VERSION 5.8 ;
BUSBITCHARS "[]" ;
DIVIDERCHAR "/" ;
UNITS
    DATABASE MICRONS 1000 ;
END UNITS

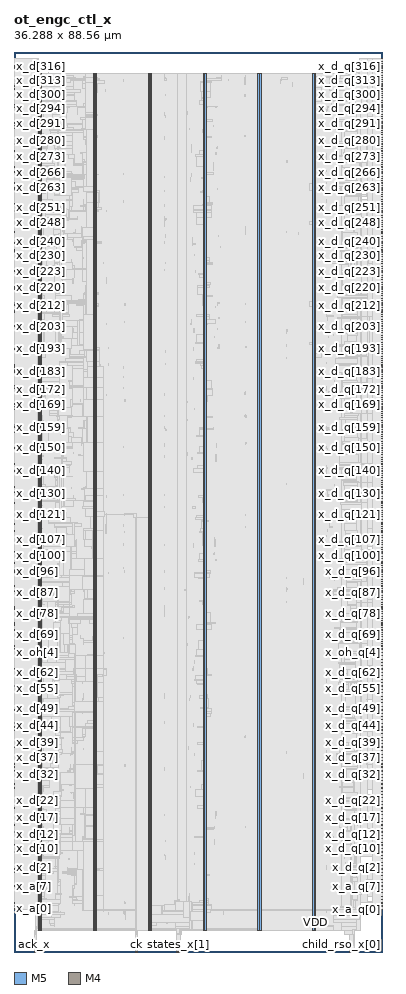
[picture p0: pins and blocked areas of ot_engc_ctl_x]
MACRO ot_engc_ctl_x
  FOREIGN ot_engc_ctl_x 0 0 ;
  CLASS BLOCK ;
  SIZE 36.288 BY 88.56 ;
  PIN ack_x
    DIRECTION OUTPUT ;
    USE SIGNAL ;
    PORT
      LAYER M5 ;
        RECT  2.016 0 2.04 0.084 ;
    END
  END ack_x
  PIN child_rso_x[0]
    DIRECTION INPUT ;
    USE SIGNAL ;
    PORT
      LAYER M5 ;
        RECT  33.024 0 33.048 0.084 ;
    END
  END child_rso_x[0]
  PIN child_rso_x[1]
    DIRECTION INPUT ;
    USE SIGNAL ;
    PORT
      LAYER M5 ;
        RECT  2.208 0 2.232 0.084 ;
    END
  END child_rso_x[1]
  PIN child_rso_x[2]
    DIRECTION INPUT ;
    USE SIGNAL ;
    PORT
      LAYER M5 ;
        RECT  33.12 0 33.144 0.084 ;
    END
  END child_rso_x[2]
  PIN child_rso_x[3]
    DIRECTION INPUT ;
    USE SIGNAL ;
    PORT
      LAYER M5 ;
        RECT  33.504 0 33.528 0.084 ;
    END
  END child_rso_x[3]
  PIN ck
    DIRECTION INPUT ;
    USE SIGNAL ;
    PORT
      LAYER M5 ;
        RECT  12 0 12.024 0.084 ;
    END
  END ck
  PIN rst
    DIRECTION INPUT ;
    USE SIGNAL ;
    PORT
      LAYER M5 ;
        RECT  12.096 0 12.12 0.084 ;
    END
  END rst
  PIN rst_io_n
    DIRECTION OUTPUT ;
    USE SIGNAL ;
    PORT
      LAYER M5 ;
        RECT  33.216 0 33.24 0.084 ;
    END
  END rst_io_n
  PIN rst_pb0_n
    DIRECTION OUTPUT ;
    USE SIGNAL ;
    PORT
      LAYER M5 ;
        RECT  33.312 0 33.336 0.084 ;
    END
  END rst_pb0_n
  PIN rst_pb1_n
    DIRECTION OUTPUT ;
    USE SIGNAL ;
    PORT
      LAYER M5 ;
        RECT  2.112 0 2.136 0.084 ;
    END
  END rst_pb1_n
  PIN rst_pb2_n
    DIRECTION OUTPUT ;
    USE SIGNAL ;
    PORT
      LAYER M5 ;
        RECT  33.408 0 33.432 0.084 ;
    END
  END rst_pb2_n
  PIN states_x[0]
    DIRECTION OUTPUT ;
    USE SIGNAL ;
    PORT
      LAYER M5 ;
        RECT  16.032 0 16.056 0.084 ;
    END
  END states_x[0]
  PIN states_x[1]
    DIRECTION OUTPUT ;
    USE SIGNAL ;
    PORT
      LAYER M5 ;
        RECT  16.128 0 16.152 0.084 ;
    END
  END states_x[1]
  PIN states_x[2]
    DIRECTION OUTPUT ;
    USE SIGNAL ;
    PORT
      LAYER M5 ;
        RECT  16.224 0 16.248 0.084 ;
    END
  END states_x[2]
  PIN states_x[3]
    DIRECTION OUTPUT ;
    USE SIGNAL ;
    PORT
      LAYER M5 ;
        RECT  16.32 0 16.344 0.084 ;
    END
  END states_x[3]
  PIN x_a[0]
    DIRECTION INPUT ;
    USE SIGNAL ;
    PORT
      LAYER M4 ;
        RECT  0 4.224 0.084 4.248 ;
    END
  END x_a[0]
  PIN x_a[1]
    DIRECTION INPUT ;
    USE SIGNAL ;
    PORT
      LAYER M4 ;
        RECT  0 4.512 0.084 4.536 ;
    END
  END x_a[1]
  PIN x_a[2]
    DIRECTION INPUT ;
    USE SIGNAL ;
    PORT
      LAYER M4 ;
        RECT  0 4.8 0.084 4.824 ;
    END
  END x_a[2]
  PIN x_a[3]
    DIRECTION INPUT ;
    USE SIGNAL ;
    PORT
      LAYER M4 ;
        RECT  0 5.136 0.084 5.16 ;
    END
  END x_a[3]
  PIN x_a[4]
    DIRECTION INPUT ;
    USE SIGNAL ;
    PORT
      LAYER M4 ;
        RECT  0 5.472 0.084 5.496 ;
    END
  END x_a[4]
  PIN x_a[5]
    DIRECTION INPUT ;
    USE SIGNAL ;
    PORT
      LAYER M4 ;
        RECT  0 5.856 0.084 5.88 ;
    END
  END x_a[5]
  PIN x_a[6]
    DIRECTION INPUT ;
    USE SIGNAL ;
    PORT
      LAYER M4 ;
        RECT  0 6.144 0.084 6.168 ;
    END
  END x_a[6]
  PIN x_a[7]
    DIRECTION INPUT ;
    USE SIGNAL ;
    PORT
      LAYER M4 ;
        RECT  0 6.48 0.084 6.504 ;
    END
  END x_a[7]
  PIN x_a_q[0]
    DIRECTION OUTPUT ;
    USE SIGNAL ;
    PORT
      LAYER M4 ;
        RECT  36.204 4.176 36.288 4.2 ;
    END
  END x_a_q[0]
  PIN x_a_q[1]
    DIRECTION OUTPUT ;
    USE SIGNAL ;
    PORT
      LAYER M4 ;
        RECT  36.204 4.512 36.288 4.536 ;
    END
  END x_a_q[1]
  PIN x_a_q[2]
    DIRECTION OUTPUT ;
    USE SIGNAL ;
    PORT
      LAYER M4 ;
        RECT  36.204 4.8 36.288 4.824 ;
    END
  END x_a_q[2]
  PIN x_a_q[3]
    DIRECTION OUTPUT ;
    USE SIGNAL ;
    PORT
      LAYER M4 ;
        RECT  36.204 5.136 36.288 5.16 ;
    END
  END x_a_q[3]
  PIN x_a_q[4]
    DIRECTION OUTPUT ;
    USE SIGNAL ;
    PORT
      LAYER M4 ;
        RECT  36.204 5.472 36.288 5.496 ;
    END
  END x_a_q[4]
  PIN x_a_q[5]
    DIRECTION OUTPUT ;
    USE SIGNAL ;
    PORT
      LAYER M4 ;
        RECT  36.204 5.808 36.288 5.832 ;
    END
  END x_a_q[5]
  PIN x_a_q[6]
    DIRECTION OUTPUT ;
    USE SIGNAL ;
    PORT
      LAYER M4 ;
        RECT  36.204 6.144 36.288 6.168 ;
    END
  END x_a_q[6]
  PIN x_a_q[7]
    DIRECTION OUTPUT ;
    USE SIGNAL ;
    PORT
      LAYER M4 ;
        RECT  36.204 6.48 36.288 6.504 ;
    END
  END x_a_q[7]
  PIN x_d[0]
    DIRECTION INPUT ;
    USE SIGNAL ;
    PORT
      LAYER M4 ;
        RECT  0 6.816 0.084 6.84 ;
    END
  END x_d[0]
  PIN x_d[100]
    DIRECTION INPUT ;
    USE SIGNAL ;
    PORT
      LAYER M4 ;
        RECT  0 38.256 0.084 38.28 ;
    END
  END x_d[100]
  PIN x_d[101]
    DIRECTION INPUT ;
    USE SIGNAL ;
    PORT
      LAYER M4 ;
        RECT  0 38.448 0.084 38.472 ;
    END
  END x_d[101]
  PIN x_d[102]
    DIRECTION INPUT ;
    USE SIGNAL ;
    PORT
      LAYER M4 ;
        RECT  0 38.736 0.084 38.76 ;
    END
  END x_d[102]
  PIN x_d[103]
    DIRECTION INPUT ;
    USE SIGNAL ;
    PORT
      LAYER M4 ;
        RECT  0 38.928 0.084 38.952 ;
    END
  END x_d[103]
  PIN x_d[104]
    DIRECTION INPUT ;
    USE SIGNAL ;
    PORT
      LAYER M4 ;
        RECT  0 39.168 0.084 39.192 ;
    END
  END x_d[104]
  PIN x_d[105]
    DIRECTION INPUT ;
    USE SIGNAL ;
    PORT
      LAYER M4 ;
        RECT  0 39.36 0.084 39.384 ;
    END
  END x_d[105]
  PIN x_d[106]
    DIRECTION INPUT ;
    USE SIGNAL ;
    PORT
      LAYER M4 ;
        RECT  0 39.6 0.084 39.624 ;
    END
  END x_d[106]
  PIN x_d[107]
    DIRECTION INPUT ;
    USE SIGNAL ;
    PORT
      LAYER M4 ;
        RECT  0 39.792 0.084 39.816 ;
    END
  END x_d[107]
  PIN x_d[108]
    DIRECTION INPUT ;
    USE SIGNAL ;
    PORT
      LAYER M4 ;
        RECT  0 40.08 0.084 40.104 ;
    END
  END x_d[108]
  PIN x_d[109]
    DIRECTION INPUT ;
    USE SIGNAL ;
    PORT
      LAYER M4 ;
        RECT  0 40.32 0.084 40.344 ;
    END
  END x_d[109]
  PIN x_d[10]
    DIRECTION INPUT ;
    USE SIGNAL ;
    PORT
      LAYER M4 ;
        RECT  0 10.176 0.084 10.2 ;
    END
  END x_d[10]
  PIN x_d[110]
    DIRECTION INPUT ;
    USE SIGNAL ;
    PORT
      LAYER M4 ;
        RECT  0 40.512 0.084 40.536 ;
    END
  END x_d[110]
  PIN x_d[111]
    DIRECTION INPUT ;
    USE SIGNAL ;
    PORT
      LAYER M4 ;
        RECT  0 40.752 0.084 40.776 ;
    END
  END x_d[111]
  PIN x_d[112]
    DIRECTION INPUT ;
    USE SIGNAL ;
    PORT
      LAYER M4 ;
        RECT  0 40.944 0.084 40.968 ;
    END
  END x_d[112]
  PIN x_d[113]
    DIRECTION INPUT ;
    USE SIGNAL ;
    PORT
      LAYER M4 ;
        RECT  0 41.232 0.084 41.256 ;
    END
  END x_d[113]
  PIN x_d[114]
    DIRECTION INPUT ;
    USE SIGNAL ;
    PORT
      LAYER M4 ;
        RECT  0 41.424 0.084 41.448 ;
    END
  END x_d[114]
  PIN x_d[115]
    DIRECTION INPUT ;
    USE SIGNAL ;
    PORT
      LAYER M4 ;
        RECT  0 41.664 0.084 41.688 ;
    END
  END x_d[115]
  PIN x_d[116]
    DIRECTION INPUT ;
    USE SIGNAL ;
    PORT
      LAYER M4 ;
        RECT  0 41.856 0.084 41.88 ;
    END
  END x_d[116]
  PIN x_d[117]
    DIRECTION INPUT ;
    USE SIGNAL ;
    PORT
      LAYER M4 ;
        RECT  0 42.096 0.084 42.12 ;
    END
  END x_d[117]
  PIN x_d[118]
    DIRECTION INPUT ;
    USE SIGNAL ;
    PORT
      LAYER M4 ;
        RECT  0 42.288 0.084 42.312 ;
    END
  END x_d[118]
  PIN x_d[119]
    DIRECTION INPUT ;
    USE SIGNAL ;
    PORT
      LAYER M4 ;
        RECT  0 42.576 0.084 42.6 ;
    END
  END x_d[119]
  PIN x_d[11]
    DIRECTION INPUT ;
    USE SIGNAL ;
    PORT
      LAYER M4 ;
        RECT  0 10.512 0.084 10.536 ;
    END
  END x_d[11]
  PIN x_d[120]
    DIRECTION INPUT ;
    USE SIGNAL ;
    PORT
      LAYER M4 ;
        RECT  0 42.816 0.084 42.84 ;
    END
  END x_d[120]
  PIN x_d[121]
    DIRECTION INPUT ;
    USE SIGNAL ;
    PORT
      LAYER M4 ;
        RECT  0 43.008 0.084 43.032 ;
    END
  END x_d[121]
  PIN x_d[122]
    DIRECTION INPUT ;
    USE SIGNAL ;
    PORT
      LAYER M4 ;
        RECT  0 43.248 0.084 43.272 ;
    END
  END x_d[122]
  PIN x_d[123]
    DIRECTION INPUT ;
    USE SIGNAL ;
    PORT
      LAYER M4 ;
        RECT  0 43.44 0.084 43.464 ;
    END
  END x_d[123]
  PIN x_d[124]
    DIRECTION INPUT ;
    USE SIGNAL ;
    PORT
      LAYER M4 ;
        RECT  0 43.728 0.084 43.752 ;
    END
  END x_d[124]
  PIN x_d[125]
    DIRECTION INPUT ;
    USE SIGNAL ;
    PORT
      LAYER M4 ;
        RECT  0 43.92 0.084 43.944 ;
    END
  END x_d[125]
  PIN x_d[126]
    DIRECTION INPUT ;
    USE SIGNAL ;
    PORT
      LAYER M4 ;
        RECT  0 44.16 0.084 44.184 ;
    END
  END x_d[126]
  PIN x_d[127]
    DIRECTION INPUT ;
    USE SIGNAL ;
    PORT
      LAYER M4 ;
        RECT  0 44.352 0.084 44.376 ;
    END
  END x_d[127]
  PIN x_d[128]
    DIRECTION INPUT ;
    USE SIGNAL ;
    PORT
      LAYER M4 ;
        RECT  0 44.592 0.084 44.616 ;
    END
  END x_d[128]
  PIN x_d[129]
    DIRECTION INPUT ;
    USE SIGNAL ;
    PORT
      LAYER M4 ;
        RECT  0 44.832 0.084 44.856 ;
    END
  END x_d[129]
  PIN x_d[12]
    DIRECTION INPUT ;
    USE SIGNAL ;
    PORT
      LAYER M4 ;
        RECT  0 10.8 0.084 10.824 ;
    END
  END x_d[12]
  PIN x_d[130]
    DIRECTION INPUT ;
    USE SIGNAL ;
    PORT
      LAYER M4 ;
        RECT  0 45.072 0.084 45.096 ;
    END
  END x_d[130]
  PIN x_d[131]
    DIRECTION INPUT ;
    USE SIGNAL ;
    PORT
      LAYER M4 ;
        RECT  0 45.264 0.084 45.288 ;
    END
  END x_d[131]
  PIN x_d[132]
    DIRECTION INPUT ;
    USE SIGNAL ;
    PORT
      LAYER M4 ;
        RECT  0 45.504 0.084 45.528 ;
    END
  END x_d[132]
  PIN x_d[133]
    DIRECTION INPUT ;
    USE SIGNAL ;
    PORT
      LAYER M4 ;
        RECT  0 45.744 0.084 45.768 ;
    END
  END x_d[133]
  PIN x_d[134]
    DIRECTION INPUT ;
    USE SIGNAL ;
    PORT
      LAYER M4 ;
        RECT  0 45.984 0.084 46.008 ;
    END
  END x_d[134]
  PIN x_d[135]
    DIRECTION INPUT ;
    USE SIGNAL ;
    PORT
      LAYER M4 ;
        RECT  0 46.176 0.084 46.2 ;
    END
  END x_d[135]
  PIN x_d[136]
    DIRECTION INPUT ;
    USE SIGNAL ;
    PORT
      LAYER M4 ;
        RECT  0 46.416 0.084 46.44 ;
    END
  END x_d[136]
  PIN x_d[137]
    DIRECTION INPUT ;
    USE SIGNAL ;
    PORT
      LAYER M4 ;
        RECT  0 46.656 0.084 46.68 ;
    END
  END x_d[137]
  PIN x_d[138]
    DIRECTION INPUT ;
    USE SIGNAL ;
    PORT
      LAYER M4 ;
        RECT  0 46.848 0.084 46.872 ;
    END
  END x_d[138]
  PIN x_d[139]
    DIRECTION INPUT ;
    USE SIGNAL ;
    PORT
      LAYER M4 ;
        RECT  0 47.088 0.084 47.112 ;
    END
  END x_d[139]
  PIN x_d[13]
    DIRECTION INPUT ;
    USE SIGNAL ;
    PORT
      LAYER M4 ;
        RECT  0 11.136 0.084 11.16 ;
    END
  END x_d[13]
  PIN x_d[140]
    DIRECTION INPUT ;
    USE SIGNAL ;
    PORT
      LAYER M4 ;
        RECT  0 47.328 0.084 47.352 ;
    END
  END x_d[140]
  PIN x_d[141]
    DIRECTION INPUT ;
    USE SIGNAL ;
    PORT
      LAYER M4 ;
        RECT  0 47.568 0.084 47.592 ;
    END
  END x_d[141]
  PIN x_d[142]
    DIRECTION INPUT ;
    USE SIGNAL ;
    PORT
      LAYER M4 ;
        RECT  0 47.76 0.084 47.784 ;
    END
  END x_d[142]
  PIN x_d[143]
    DIRECTION INPUT ;
    USE SIGNAL ;
    PORT
      LAYER M4 ;
        RECT  0 48 0.084 48.024 ;
    END
  END x_d[143]
  PIN x_d[144]
    DIRECTION INPUT ;
    USE SIGNAL ;
    PORT
      LAYER M4 ;
        RECT  0 48.24 0.084 48.264 ;
    END
  END x_d[144]
  PIN x_d[145]
    DIRECTION INPUT ;
    USE SIGNAL ;
    PORT
      LAYER M4 ;
        RECT  0 48.432 0.084 48.456 ;
    END
  END x_d[145]
  PIN x_d[146]
    DIRECTION INPUT ;
    USE SIGNAL ;
    PORT
      LAYER M4 ;
        RECT  0 48.672 0.084 48.696 ;
    END
  END x_d[146]
  PIN x_d[147]
    DIRECTION INPUT ;
    USE SIGNAL ;
    PORT
      LAYER M4 ;
        RECT  0 48.912 0.084 48.936 ;
    END
  END x_d[147]
  PIN x_d[148]
    DIRECTION INPUT ;
    USE SIGNAL ;
    PORT
      LAYER M4 ;
        RECT  0 49.152 0.084 49.176 ;
    END
  END x_d[148]
  PIN x_d[149]
    DIRECTION INPUT ;
    USE SIGNAL ;
    PORT
      LAYER M4 ;
        RECT  0 49.344 0.084 49.368 ;
    END
  END x_d[149]
  PIN x_d[14]
    DIRECTION INPUT ;
    USE SIGNAL ;
    PORT
      LAYER M4 ;
        RECT  0 11.472 0.084 11.496 ;
    END
  END x_d[14]
  PIN x_d[150]
    DIRECTION INPUT ;
    USE SIGNAL ;
    PORT
      LAYER M4 ;
        RECT  0 49.584 0.084 49.608 ;
    END
  END x_d[150]
  PIN x_d[151]
    DIRECTION INPUT ;
    USE SIGNAL ;
    PORT
      LAYER M4 ;
        RECT  0 49.824 0.084 49.848 ;
    END
  END x_d[151]
  PIN x_d[152]
    DIRECTION INPUT ;
    USE SIGNAL ;
    PORT
      LAYER M4 ;
        RECT  0 50.016 0.084 50.04 ;
    END
  END x_d[152]
  PIN x_d[153]
    DIRECTION INPUT ;
    USE SIGNAL ;
    PORT
      LAYER M4 ;
        RECT  0 50.256 0.084 50.28 ;
    END
  END x_d[153]
  PIN x_d[154]
    DIRECTION INPUT ;
    USE SIGNAL ;
    PORT
      LAYER M4 ;
        RECT  0 50.496 0.084 50.52 ;
    END
  END x_d[154]
  PIN x_d[155]
    DIRECTION INPUT ;
    USE SIGNAL ;
    PORT
      LAYER M4 ;
        RECT  0 50.736 0.084 50.76 ;
    END
  END x_d[155]
  PIN x_d[156]
    DIRECTION INPUT ;
    USE SIGNAL ;
    PORT
      LAYER M4 ;
        RECT  0 50.928 0.084 50.952 ;
    END
  END x_d[156]
  PIN x_d[157]
    DIRECTION INPUT ;
    USE SIGNAL ;
    PORT
      LAYER M4 ;
        RECT  0 51.168 0.084 51.192 ;
    END
  END x_d[157]
  PIN x_d[158]
    DIRECTION INPUT ;
    USE SIGNAL ;
    PORT
      LAYER M4 ;
        RECT  0 51.408 0.084 51.432 ;
    END
  END x_d[158]
  PIN x_d[159]
    DIRECTION INPUT ;
    USE SIGNAL ;
    PORT
      LAYER M4 ;
        RECT  0 51.648 0.084 51.672 ;
    END
  END x_d[159]
  PIN x_d[15]
    DIRECTION INPUT ;
    USE SIGNAL ;
    PORT
      LAYER M4 ;
        RECT  0 11.808 0.084 11.832 ;
    END
  END x_d[15]
  PIN x_d[160]
    DIRECTION INPUT ;
    USE SIGNAL ;
    PORT
      LAYER M4 ;
        RECT  0 51.84 0.084 51.864 ;
    END
  END x_d[160]
  PIN x_d[161]
    DIRECTION INPUT ;
    USE SIGNAL ;
    PORT
      LAYER M4 ;
        RECT  0 52.08 0.084 52.104 ;
    END
  END x_d[161]
  PIN x_d[162]
    DIRECTION INPUT ;
    USE SIGNAL ;
    PORT
      LAYER M4 ;
        RECT  0 52.272 0.084 52.296 ;
    END
  END x_d[162]
  PIN x_d[163]
    DIRECTION INPUT ;
    USE SIGNAL ;
    PORT
      LAYER M4 ;
        RECT  0 52.56 0.084 52.584 ;
    END
  END x_d[163]
  PIN x_d[164]
    DIRECTION INPUT ;
    USE SIGNAL ;
    PORT
      LAYER M4 ;
        RECT  0 52.752 0.084 52.776 ;
    END
  END x_d[164]
  PIN x_d[165]
    DIRECTION INPUT ;
    USE SIGNAL ;
    PORT
      LAYER M4 ;
        RECT  0 52.992 0.084 53.016 ;
    END
  END x_d[165]
  PIN x_d[166]
    DIRECTION INPUT ;
    USE SIGNAL ;
    PORT
      LAYER M4 ;
        RECT  0 53.184 0.084 53.208 ;
    END
  END x_d[166]
  PIN x_d[167]
    DIRECTION INPUT ;
    USE SIGNAL ;
    PORT
      LAYER M4 ;
        RECT  0 53.424 0.084 53.448 ;
    END
  END x_d[167]
  PIN x_d[168]
    DIRECTION INPUT ;
    USE SIGNAL ;
    PORT
      LAYER M4 ;
        RECT  0 53.616 0.084 53.64 ;
    END
  END x_d[168]
  PIN x_d[169]
    DIRECTION INPUT ;
    USE SIGNAL ;
    PORT
      LAYER M4 ;
        RECT  0 53.904 0.084 53.928 ;
    END
  END x_d[169]
  PIN x_d[16]
    DIRECTION INPUT ;
    USE SIGNAL ;
    PORT
      LAYER M4 ;
        RECT  0 12.144 0.084 12.168 ;
    END
  END x_d[16]
  PIN x_d[170]
    DIRECTION INPUT ;
    USE SIGNAL ;
    PORT
      LAYER M4 ;
        RECT  0 54.144 0.084 54.168 ;
    END
  END x_d[170]
  PIN x_d[171]
    DIRECTION INPUT ;
    USE SIGNAL ;
    PORT
      LAYER M4 ;
        RECT  0 54.336 0.084 54.36 ;
    END
  END x_d[171]
  PIN x_d[172]
    DIRECTION INPUT ;
    USE SIGNAL ;
    PORT
      LAYER M4 ;
        RECT  0 54.576 0.084 54.6 ;
    END
  END x_d[172]
  PIN x_d[173]
    DIRECTION INPUT ;
    USE SIGNAL ;
    PORT
      LAYER M4 ;
        RECT  0 54.768 0.084 54.792 ;
    END
  END x_d[173]
  PIN x_d[174]
    DIRECTION INPUT ;
    USE SIGNAL ;
    PORT
      LAYER M4 ;
        RECT  0 55.056 0.084 55.08 ;
    END
  END x_d[174]
  PIN x_d[175]
    DIRECTION INPUT ;
    USE SIGNAL ;
    PORT
      LAYER M4 ;
        RECT  0 55.248 0.084 55.272 ;
    END
  END x_d[175]
  PIN x_d[176]
    DIRECTION INPUT ;
    USE SIGNAL ;
    PORT
      LAYER M4 ;
        RECT  0 55.488 0.084 55.512 ;
    END
  END x_d[176]
  PIN x_d[177]
    DIRECTION INPUT ;
    USE SIGNAL ;
    PORT
      LAYER M4 ;
        RECT  0 55.68 0.084 55.704 ;
    END
  END x_d[177]
  PIN x_d[178]
    DIRECTION INPUT ;
    USE SIGNAL ;
    PORT
      LAYER M4 ;
        RECT  0 55.92 0.084 55.944 ;
    END
  END x_d[178]
  PIN x_d[179]
    DIRECTION INPUT ;
    USE SIGNAL ;
    PORT
      LAYER M4 ;
        RECT  0 56.112 0.084 56.136 ;
    END
  END x_d[179]
  PIN x_d[17]
    DIRECTION INPUT ;
    USE SIGNAL ;
    PORT
      LAYER M4 ;
        RECT  0 12.48 0.084 12.504 ;
    END
  END x_d[17]
  PIN x_d[180]
    DIRECTION INPUT ;
    USE SIGNAL ;
    PORT
      LAYER M4 ;
        RECT  0 56.4 0.084 56.424 ;
    END
  END x_d[180]
  PIN x_d[181]
    DIRECTION INPUT ;
    USE SIGNAL ;
    PORT
      LAYER M4 ;
        RECT  0 56.592 0.084 56.616 ;
    END
  END x_d[181]
  PIN x_d[182]
    DIRECTION INPUT ;
    USE SIGNAL ;
    PORT
      LAYER M4 ;
        RECT  0 56.832 0.084 56.856 ;
    END
  END x_d[182]
  PIN x_d[183]
    DIRECTION INPUT ;
    USE SIGNAL ;
    PORT
      LAYER M4 ;
        RECT  0 57.072 0.084 57.096 ;
    END
  END x_d[183]
  PIN x_d[184]
    DIRECTION INPUT ;
    USE SIGNAL ;
    PORT
      LAYER M4 ;
        RECT  0 57.264 0.084 57.288 ;
    END
  END x_d[184]
  PIN x_d[185]
    DIRECTION INPUT ;
    USE SIGNAL ;
    PORT
      LAYER M4 ;
        RECT  0 57.552 0.084 57.576 ;
    END
  END x_d[185]
  PIN x_d[186]
    DIRECTION INPUT ;
    USE SIGNAL ;
    PORT
      LAYER M4 ;
        RECT  0 57.744 0.084 57.768 ;
    END
  END x_d[186]
  PIN x_d[187]
    DIRECTION INPUT ;
    USE SIGNAL ;
    PORT
      LAYER M4 ;
        RECT  0 57.984 0.084 58.008 ;
    END
  END x_d[187]
  PIN x_d[188]
    DIRECTION INPUT ;
    USE SIGNAL ;
    PORT
      LAYER M4 ;
        RECT  0 58.176 0.084 58.2 ;
    END
  END x_d[188]
  PIN x_d[189]
    DIRECTION INPUT ;
    USE SIGNAL ;
    PORT
      LAYER M4 ;
        RECT  0 58.416 0.084 58.44 ;
    END
  END x_d[189]
  PIN x_d[18]
    DIRECTION INPUT ;
    USE SIGNAL ;
    PORT
      LAYER M4 ;
        RECT  0 12.816 0.084 12.84 ;
    END
  END x_d[18]
  PIN x_d[190]
    DIRECTION INPUT ;
    USE SIGNAL ;
    PORT
      LAYER M4 ;
        RECT  0 58.608 0.084 58.632 ;
    END
  END x_d[190]
  PIN x_d[191]
    DIRECTION INPUT ;
    USE SIGNAL ;
    PORT
      LAYER M4 ;
        RECT  0 58.896 0.084 58.92 ;
    END
  END x_d[191]
  PIN x_d[192]
    DIRECTION INPUT ;
    USE SIGNAL ;
    PORT
      LAYER M4 ;
        RECT  0 59.088 0.084 59.112 ;
    END
  END x_d[192]
  PIN x_d[193]
    DIRECTION INPUT ;
    USE SIGNAL ;
    PORT
      LAYER M4 ;
        RECT  0 59.328 0.084 59.352 ;
    END
  END x_d[193]
  PIN x_d[194]
    DIRECTION INPUT ;
    USE SIGNAL ;
    PORT
      LAYER M4 ;
        RECT  0 59.568 0.084 59.592 ;
    END
  END x_d[194]
  PIN x_d[195]
    DIRECTION INPUT ;
    USE SIGNAL ;
    PORT
      LAYER M4 ;
        RECT  0 59.76 0.084 59.784 ;
    END
  END x_d[195]
  PIN x_d[196]
    DIRECTION INPUT ;
    USE SIGNAL ;
    PORT
      LAYER M4 ;
        RECT  0 60 0.084 60.024 ;
    END
  END x_d[196]
  PIN x_d[197]
    DIRECTION INPUT ;
    USE SIGNAL ;
    PORT
      LAYER M4 ;
        RECT  0 60.24 0.084 60.264 ;
    END
  END x_d[197]
  PIN x_d[198]
    DIRECTION INPUT ;
    USE SIGNAL ;
    PORT
      LAYER M4 ;
        RECT  0 60.48 0.084 60.504 ;
    END
  END x_d[198]
  PIN x_d[199]
    DIRECTION INPUT ;
    USE SIGNAL ;
    PORT
      LAYER M4 ;
        RECT  0 60.672 0.084 60.696 ;
    END
  END x_d[199]
  PIN x_d[19]
    DIRECTION INPUT ;
    USE SIGNAL ;
    PORT
      LAYER M4 ;
        RECT  0 13.2 0.084 13.224 ;
    END
  END x_d[19]
  PIN x_d[1]
    DIRECTION INPUT ;
    USE SIGNAL ;
    PORT
      LAYER M4 ;
        RECT  0 7.152 0.084 7.176 ;
    END
  END x_d[1]
  PIN x_d[200]
    DIRECTION INPUT ;
    USE SIGNAL ;
    PORT
      LAYER M4 ;
        RECT  0 60.912 0.084 60.936 ;
    END
  END x_d[200]
  PIN x_d[201]
    DIRECTION INPUT ;
    USE SIGNAL ;
    PORT
      LAYER M4 ;
        RECT  0 61.152 0.084 61.176 ;
    END
  END x_d[201]
  PIN x_d[202]
    DIRECTION INPUT ;
    USE SIGNAL ;
    PORT
      LAYER M4 ;
        RECT  0 61.344 0.084 61.368 ;
    END
  END x_d[202]
  PIN x_d[203]
    DIRECTION INPUT ;
    USE SIGNAL ;
    PORT
      LAYER M4 ;
        RECT  0 61.584 0.084 61.608 ;
    END
  END x_d[203]
  PIN x_d[204]
    DIRECTION INPUT ;
    USE SIGNAL ;
    PORT
      LAYER M4 ;
        RECT  0 61.824 0.084 61.848 ;
    END
  END x_d[204]
  PIN x_d[205]
    DIRECTION INPUT ;
    USE SIGNAL ;
    PORT
      LAYER M4 ;
        RECT  0 62.064 0.084 62.088 ;
    END
  END x_d[205]
  PIN x_d[206]
    DIRECTION INPUT ;
    USE SIGNAL ;
    PORT
      LAYER M4 ;
        RECT  0 62.256 0.084 62.28 ;
    END
  END x_d[206]
  PIN x_d[207]
    DIRECTION INPUT ;
    USE SIGNAL ;
    PORT
      LAYER M4 ;
        RECT  0 62.496 0.084 62.52 ;
    END
  END x_d[207]
  PIN x_d[208]
    DIRECTION INPUT ;
    USE SIGNAL ;
    PORT
      LAYER M4 ;
        RECT  0 62.736 0.084 62.76 ;
    END
  END x_d[208]
  PIN x_d[209]
    DIRECTION INPUT ;
    USE SIGNAL ;
    PORT
      LAYER M4 ;
        RECT  0 62.976 0.084 63 ;
    END
  END x_d[209]
  PIN x_d[20]
    DIRECTION INPUT ;
    USE SIGNAL ;
    PORT
      LAYER M4 ;
        RECT  0 13.488 0.084 13.512 ;
    END
  END x_d[20]
  PIN x_d[210]
    DIRECTION INPUT ;
    USE SIGNAL ;
    PORT
      LAYER M4 ;
        RECT  0 63.168 0.084 63.192 ;
    END
  END x_d[210]
  PIN x_d[211]
    DIRECTION INPUT ;
    USE SIGNAL ;
    PORT
      LAYER M4 ;
        RECT  0 63.408 0.084 63.432 ;
    END
  END x_d[211]
  PIN x_d[212]
    DIRECTION INPUT ;
    USE SIGNAL ;
    PORT
      LAYER M4 ;
        RECT  0 63.648 0.084 63.672 ;
    END
  END x_d[212]
  PIN x_d[213]
    DIRECTION INPUT ;
    USE SIGNAL ;
    PORT
      LAYER M4 ;
        RECT  0 63.84 0.084 63.864 ;
    END
  END x_d[213]
  PIN x_d[214]
    DIRECTION INPUT ;
    USE SIGNAL ;
    PORT
      LAYER M4 ;
        RECT  0 64.08 0.084 64.104 ;
    END
  END x_d[214]
  PIN x_d[215]
    DIRECTION INPUT ;
    USE SIGNAL ;
    PORT
      LAYER M4 ;
        RECT  0 64.32 0.084 64.344 ;
    END
  END x_d[215]
  PIN x_d[216]
    DIRECTION INPUT ;
    USE SIGNAL ;
    PORT
      LAYER M4 ;
        RECT  0 64.56 0.084 64.584 ;
    END
  END x_d[216]
  PIN x_d[217]
    DIRECTION INPUT ;
    USE SIGNAL ;
    PORT
      LAYER M4 ;
        RECT  0 64.752 0.084 64.776 ;
    END
  END x_d[217]
  PIN x_d[218]
    DIRECTION INPUT ;
    USE SIGNAL ;
    PORT
      LAYER M4 ;
        RECT  0 64.992 0.084 65.016 ;
    END
  END x_d[218]
  PIN x_d[219]
    DIRECTION INPUT ;
    USE SIGNAL ;
    PORT
      LAYER M4 ;
        RECT  0 65.232 0.084 65.256 ;
    END
  END x_d[219]
  PIN x_d[21]
    DIRECTION INPUT ;
    USE SIGNAL ;
    PORT
      LAYER M4 ;
        RECT  0 13.824 0.084 13.848 ;
    END
  END x_d[21]
  PIN x_d[220]
    DIRECTION INPUT ;
    USE SIGNAL ;
    PORT
      LAYER M4 ;
        RECT  0 65.424 0.084 65.448 ;
    END
  END x_d[220]
  PIN x_d[221]
    DIRECTION INPUT ;
    USE SIGNAL ;
    PORT
      LAYER M4 ;
        RECT  0 65.664 0.084 65.688 ;
    END
  END x_d[221]
  PIN x_d[222]
    DIRECTION INPUT ;
    USE SIGNAL ;
    PORT
      LAYER M4 ;
        RECT  0 65.904 0.084 65.928 ;
    END
  END x_d[222]
  PIN x_d[223]
    DIRECTION INPUT ;
    USE SIGNAL ;
    PORT
      LAYER M4 ;
        RECT  0 66.144 0.084 66.168 ;
    END
  END x_d[223]
  PIN x_d[224]
    DIRECTION INPUT ;
    USE SIGNAL ;
    PORT
      LAYER M4 ;
        RECT  0 66.384 0.084 66.408 ;
    END
  END x_d[224]
  PIN x_d[225]
    DIRECTION INPUT ;
    USE SIGNAL ;
    PORT
      LAYER M4 ;
        RECT  0 66.576 0.084 66.6 ;
    END
  END x_d[225]
  PIN x_d[226]
    DIRECTION INPUT ;
    USE SIGNAL ;
    PORT
      LAYER M4 ;
        RECT  0 66.816 0.084 66.84 ;
    END
  END x_d[226]
  PIN x_d[227]
    DIRECTION INPUT ;
    USE SIGNAL ;
    PORT
      LAYER M4 ;
        RECT  0 67.008 0.084 67.032 ;
    END
  END x_d[227]
  PIN x_d[228]
    DIRECTION INPUT ;
    USE SIGNAL ;
    PORT
      LAYER M4 ;
        RECT  0 67.248 0.084 67.272 ;
    END
  END x_d[228]
  PIN x_d[229]
    DIRECTION INPUT ;
    USE SIGNAL ;
    PORT
      LAYER M4 ;
        RECT  0 67.44 0.084 67.464 ;
    END
  END x_d[229]
  PIN x_d[22]
    DIRECTION INPUT ;
    USE SIGNAL ;
    PORT
      LAYER M4 ;
        RECT  0 14.16 0.084 14.184 ;
    END
  END x_d[22]
  PIN x_d[230]
    DIRECTION INPUT ;
    USE SIGNAL ;
    PORT
      LAYER M4 ;
        RECT  0 67.728 0.084 67.752 ;
    END
  END x_d[230]
  PIN x_d[231]
    DIRECTION INPUT ;
    USE SIGNAL ;
    PORT
      LAYER M4 ;
        RECT  0 67.92 0.084 67.944 ;
    END
  END x_d[231]
  PIN x_d[232]
    DIRECTION INPUT ;
    USE SIGNAL ;
    PORT
      LAYER M4 ;
        RECT  0 68.16 0.084 68.184 ;
    END
  END x_d[232]
  PIN x_d[233]
    DIRECTION INPUT ;
    USE SIGNAL ;
    PORT
      LAYER M4 ;
        RECT  0 68.4 0.084 68.424 ;
    END
  END x_d[233]
  PIN x_d[234]
    DIRECTION INPUT ;
    USE SIGNAL ;
    PORT
      LAYER M4 ;
        RECT  0 68.592 0.084 68.616 ;
    END
  END x_d[234]
  PIN x_d[235]
    DIRECTION INPUT ;
    USE SIGNAL ;
    PORT
      LAYER M4 ;
        RECT  0 68.88 0.084 68.904 ;
    END
  END x_d[235]
  PIN x_d[236]
    DIRECTION INPUT ;
    USE SIGNAL ;
    PORT
      LAYER M4 ;
        RECT  0 69.072 0.084 69.096 ;
    END
  END x_d[236]
  PIN x_d[237]
    DIRECTION INPUT ;
    USE SIGNAL ;
    PORT
      LAYER M4 ;
        RECT  0 69.312 0.084 69.336 ;
    END
  END x_d[237]
  PIN x_d[238]
    DIRECTION INPUT ;
    USE SIGNAL ;
    PORT
      LAYER M4 ;
        RECT  0 69.504 0.084 69.528 ;
    END
  END x_d[238]
  PIN x_d[239]
    DIRECTION INPUT ;
    USE SIGNAL ;
    PORT
      LAYER M4 ;
        RECT  0 69.744 0.084 69.768 ;
    END
  END x_d[239]
  PIN x_d[23]
    DIRECTION INPUT ;
    USE SIGNAL ;
    PORT
      LAYER M4 ;
        RECT  0 14.496 0.084 14.52 ;
    END
  END x_d[23]
  PIN x_d[240]
    DIRECTION INPUT ;
    USE SIGNAL ;
    PORT
      LAYER M4 ;
        RECT  0 69.936 0.084 69.96 ;
    END
  END x_d[240]
  PIN x_d[241]
    DIRECTION INPUT ;
    USE SIGNAL ;
    PORT
      LAYER M4 ;
        RECT  0 70.224 0.084 70.248 ;
    END
  END x_d[241]
  PIN x_d[242]
    DIRECTION INPUT ;
    USE SIGNAL ;
    PORT
      LAYER M4 ;
        RECT  0 70.416 0.084 70.44 ;
    END
  END x_d[242]
  PIN x_d[243]
    DIRECTION INPUT ;
    USE SIGNAL ;
    PORT
      LAYER M4 ;
        RECT  0 70.656 0.084 70.68 ;
    END
  END x_d[243]
  PIN x_d[244]
    DIRECTION INPUT ;
    USE SIGNAL ;
    PORT
      LAYER M4 ;
        RECT  0 70.848 0.084 70.872 ;
    END
  END x_d[244]
  PIN x_d[245]
    DIRECTION INPUT ;
    USE SIGNAL ;
    PORT
      LAYER M4 ;
        RECT  0 71.088 0.084 71.112 ;
    END
  END x_d[245]
  PIN x_d[246]
    DIRECTION INPUT ;
    USE SIGNAL ;
    PORT
      LAYER M4 ;
        RECT  0 71.376 0.084 71.4 ;
    END
  END x_d[246]
  PIN x_d[247]
    DIRECTION INPUT ;
    USE SIGNAL ;
    PORT
      LAYER M4 ;
        RECT  0 71.568 0.084 71.592 ;
    END
  END x_d[247]
  PIN x_d[248]
    DIRECTION INPUT ;
    USE SIGNAL ;
    PORT
      LAYER M4 ;
        RECT  0 71.808 0.084 71.832 ;
    END
  END x_d[248]
  PIN x_d[249]
    DIRECTION INPUT ;
    USE SIGNAL ;
    PORT
      LAYER M4 ;
        RECT  0 72 0.084 72.024 ;
    END
  END x_d[249]
  PIN x_d[24]
    DIRECTION INPUT ;
    USE SIGNAL ;
    PORT
      LAYER M4 ;
        RECT  0 14.832 0.084 14.856 ;
    END
  END x_d[24]
  PIN x_d[250]
    DIRECTION INPUT ;
    USE SIGNAL ;
    PORT
      LAYER M4 ;
        RECT  0 72.24 0.084 72.264 ;
    END
  END x_d[250]
  PIN x_d[251]
    DIRECTION INPUT ;
    USE SIGNAL ;
    PORT
      LAYER M4 ;
        RECT  0 72.432 0.084 72.456 ;
    END
  END x_d[251]
  PIN x_d[252]
    DIRECTION INPUT ;
    USE SIGNAL ;
    PORT
      LAYER M4 ;
        RECT  0 72.72 0.084 72.744 ;
    END
  END x_d[252]
  PIN x_d[253]
    DIRECTION INPUT ;
    USE SIGNAL ;
    PORT
      LAYER M4 ;
        RECT  0 72.912 0.084 72.936 ;
    END
  END x_d[253]
  PIN x_d[254]
    DIRECTION INPUT ;
    USE SIGNAL ;
    PORT
      LAYER M4 ;
        RECT  0 73.152 0.084 73.176 ;
    END
  END x_d[254]
  PIN x_d[255]
    DIRECTION INPUT ;
    USE SIGNAL ;
    PORT
      LAYER M4 ;
        RECT  0 73.344 0.084 73.368 ;
    END
  END x_d[255]
  PIN x_d[256]
    DIRECTION INPUT ;
    USE SIGNAL ;
    PORT
      LAYER M4 ;
        RECT  0 73.584 0.084 73.608 ;
    END
  END x_d[256]
  PIN x_d[257]
    DIRECTION INPUT ;
    USE SIGNAL ;
    PORT
      LAYER M4 ;
        RECT  0 73.824 0.084 73.848 ;
    END
  END x_d[257]
  PIN x_d[258]
    DIRECTION INPUT ;
    USE SIGNAL ;
    PORT
      LAYER M4 ;
        RECT  0 74.064 0.084 74.088 ;
    END
  END x_d[258]
  PIN x_d[259]
    DIRECTION INPUT ;
    USE SIGNAL ;
    PORT
      LAYER M4 ;
        RECT  0 74.304 0.084 74.328 ;
    END
  END x_d[259]
  PIN x_d[25]
    DIRECTION INPUT ;
    USE SIGNAL ;
    PORT
      LAYER M4 ;
        RECT  0 15.168 0.084 15.192 ;
    END
  END x_d[25]
  PIN x_d[260]
    DIRECTION INPUT ;
    USE SIGNAL ;
    PORT
      LAYER M4 ;
        RECT  0 74.496 0.084 74.52 ;
    END
  END x_d[260]
  PIN x_d[261]
    DIRECTION INPUT ;
    USE SIGNAL ;
    PORT
      LAYER M4 ;
        RECT  0 74.736 0.084 74.76 ;
    END
  END x_d[261]
  PIN x_d[262]
    DIRECTION INPUT ;
    USE SIGNAL ;
    PORT
      LAYER M4 ;
        RECT  0 74.976 0.084 75 ;
    END
  END x_d[262]
  PIN x_d[263]
    DIRECTION INPUT ;
    USE SIGNAL ;
    PORT
      LAYER M4 ;
        RECT  0 75.168 0.084 75.192 ;
    END
  END x_d[263]
  PIN x_d[264]
    DIRECTION INPUT ;
    USE SIGNAL ;
    PORT
      LAYER M4 ;
        RECT  0 75.408 0.084 75.432 ;
    END
  END x_d[264]
  PIN x_d[265]
    DIRECTION INPUT ;
    USE SIGNAL ;
    PORT
      LAYER M4 ;
        RECT  0 75.648 0.084 75.672 ;
    END
  END x_d[265]
  PIN x_d[266]
    DIRECTION INPUT ;
    USE SIGNAL ;
    PORT
      LAYER M4 ;
        RECT  0 75.888 0.084 75.912 ;
    END
  END x_d[266]
  PIN x_d[267]
    DIRECTION INPUT ;
    USE SIGNAL ;
    PORT
      LAYER M4 ;
        RECT  0 76.08 0.084 76.104 ;
    END
  END x_d[267]
  PIN x_d[268]
    DIRECTION INPUT ;
    USE SIGNAL ;
    PORT
      LAYER M4 ;
        RECT  0 76.32 0.084 76.344 ;
    END
  END x_d[268]
  PIN x_d[269]
    DIRECTION INPUT ;
    USE SIGNAL ;
    PORT
      LAYER M4 ;
        RECT  0 76.56 0.084 76.584 ;
    END
  END x_d[269]
  PIN x_d[26]
    DIRECTION INPUT ;
    USE SIGNAL ;
    PORT
      LAYER M4 ;
        RECT  0 15.504 0.084 15.528 ;
    END
  END x_d[26]
  PIN x_d[270]
    DIRECTION INPUT ;
    USE SIGNAL ;
    PORT
      LAYER M4 ;
        RECT  0 76.752 0.084 76.776 ;
    END
  END x_d[270]
  PIN x_d[271]
    DIRECTION INPUT ;
    USE SIGNAL ;
    PORT
      LAYER M4 ;
        RECT  0 76.992 0.084 77.016 ;
    END
  END x_d[271]
  PIN x_d[272]
    DIRECTION INPUT ;
    USE SIGNAL ;
    PORT
      LAYER M4 ;
        RECT  0 77.232 0.084 77.256 ;
    END
  END x_d[272]
  PIN x_d[273]
    DIRECTION INPUT ;
    USE SIGNAL ;
    PORT
      LAYER M4 ;
        RECT  0 77.472 0.084 77.496 ;
    END
  END x_d[273]
  PIN x_d[274]
    DIRECTION INPUT ;
    USE SIGNAL ;
    PORT
      LAYER M4 ;
        RECT  0 77.664 0.084 77.688 ;
    END
  END x_d[274]
  PIN x_d[275]
    DIRECTION INPUT ;
    USE SIGNAL ;
    PORT
      LAYER M4 ;
        RECT  0 77.904 0.084 77.928 ;
    END
  END x_d[275]
  PIN x_d[276]
    DIRECTION INPUT ;
    USE SIGNAL ;
    PORT
      LAYER M4 ;
        RECT  0 78.144 0.084 78.168 ;
    END
  END x_d[276]
  PIN x_d[277]
    DIRECTION INPUT ;
    USE SIGNAL ;
    PORT
      LAYER M4 ;
        RECT  0 78.336 0.084 78.36 ;
    END
  END x_d[277]
  PIN x_d[278]
    DIRECTION INPUT ;
    USE SIGNAL ;
    PORT
      LAYER M4 ;
        RECT  0 78.576 0.084 78.6 ;
    END
  END x_d[278]
  PIN x_d[279]
    DIRECTION INPUT ;
    USE SIGNAL ;
    PORT
      LAYER M4 ;
        RECT  0 78.816 0.084 78.84 ;
    END
  END x_d[279]
  PIN x_d[27]
    DIRECTION INPUT ;
    USE SIGNAL ;
    PORT
      LAYER M4 ;
        RECT  0 15.792 0.084 15.816 ;
    END
  END x_d[27]
  PIN x_d[280]
    DIRECTION INPUT ;
    USE SIGNAL ;
    PORT
      LAYER M4 ;
        RECT  0 79.056 0.084 79.08 ;
    END
  END x_d[280]
  PIN x_d[281]
    DIRECTION INPUT ;
    USE SIGNAL ;
    PORT
      LAYER M4 ;
        RECT  0 79.248 0.084 79.272 ;
    END
  END x_d[281]
  PIN x_d[282]
    DIRECTION INPUT ;
    USE SIGNAL ;
    PORT
      LAYER M4 ;
        RECT  0 79.488 0.084 79.512 ;
    END
  END x_d[282]
  PIN x_d[283]
    DIRECTION INPUT ;
    USE SIGNAL ;
    PORT
      LAYER M4 ;
        RECT  0 79.728 0.084 79.752 ;
    END
  END x_d[283]
  PIN x_d[284]
    DIRECTION INPUT ;
    USE SIGNAL ;
    PORT
      LAYER M4 ;
        RECT  0 79.968 0.084 79.992 ;
    END
  END x_d[284]
  PIN x_d[285]
    DIRECTION INPUT ;
    USE SIGNAL ;
    PORT
      LAYER M4 ;
        RECT  0 80.16 0.084 80.184 ;
    END
  END x_d[285]
  PIN x_d[286]
    DIRECTION INPUT ;
    USE SIGNAL ;
    PORT
      LAYER M4 ;
        RECT  0 80.4 0.084 80.424 ;
    END
  END x_d[286]
  PIN x_d[287]
    DIRECTION INPUT ;
    USE SIGNAL ;
    PORT
      LAYER M4 ;
        RECT  0 80.64 0.084 80.664 ;
    END
  END x_d[287]
  PIN x_d[288]
    DIRECTION INPUT ;
    USE SIGNAL ;
    PORT
      LAYER M4 ;
        RECT  0 80.832 0.084 80.856 ;
    END
  END x_d[288]
  PIN x_d[289]
    DIRECTION INPUT ;
    USE SIGNAL ;
    PORT
      LAYER M4 ;
        RECT  0 81.072 0.084 81.096 ;
    END
  END x_d[289]
  PIN x_d[28]
    DIRECTION INPUT ;
    USE SIGNAL ;
    PORT
      LAYER M4 ;
        RECT  0 16.128 0.084 16.152 ;
    END
  END x_d[28]
  PIN x_d[290]
    DIRECTION INPUT ;
    USE SIGNAL ;
    PORT
      LAYER M4 ;
        RECT  0 81.264 0.084 81.288 ;
    END
  END x_d[290]
  PIN x_d[291]
    DIRECTION INPUT ;
    USE SIGNAL ;
    PORT
      LAYER M4 ;
        RECT  0 81.552 0.084 81.576 ;
    END
  END x_d[291]
  PIN x_d[292]
    DIRECTION INPUT ;
    USE SIGNAL ;
    PORT
      LAYER M4 ;
        RECT  0 81.744 0.084 81.768 ;
    END
  END x_d[292]
  PIN x_d[293]
    DIRECTION INPUT ;
    USE SIGNAL ;
    PORT
      LAYER M4 ;
        RECT  0 81.984 0.084 82.008 ;
    END
  END x_d[293]
  PIN x_d[294]
    DIRECTION INPUT ;
    USE SIGNAL ;
    PORT
      LAYER M4 ;
        RECT  0 82.176 0.084 82.2 ;
    END
  END x_d[294]
  PIN x_d[295]
    DIRECTION INPUT ;
    USE SIGNAL ;
    PORT
      LAYER M4 ;
        RECT  0 82.416 0.084 82.44 ;
    END
  END x_d[295]
  PIN x_d[296]
    DIRECTION INPUT ;
    USE SIGNAL ;
    PORT
      LAYER M4 ;
        RECT  0 82.704 0.084 82.728 ;
    END
  END x_d[296]
  PIN x_d[297]
    DIRECTION INPUT ;
    USE SIGNAL ;
    PORT
      LAYER M4 ;
        RECT  0 82.896 0.084 82.92 ;
    END
  END x_d[297]
  PIN x_d[298]
    DIRECTION INPUT ;
    USE SIGNAL ;
    PORT
      LAYER M4 ;
        RECT  0 83.136 0.084 83.16 ;
    END
  END x_d[298]
  PIN x_d[299]
    DIRECTION INPUT ;
    USE SIGNAL ;
    PORT
      LAYER M4 ;
        RECT  0 83.328 0.084 83.352 ;
    END
  END x_d[299]
  PIN x_d[29]
    DIRECTION INPUT ;
    USE SIGNAL ;
    PORT
      LAYER M4 ;
        RECT  0 16.512 0.084 16.536 ;
    END
  END x_d[29]
  PIN x_d[2]
    DIRECTION INPUT ;
    USE SIGNAL ;
    PORT
      LAYER M4 ;
        RECT  0 7.488 0.084 7.512 ;
    END
  END x_d[2]
  PIN x_d[300]
    DIRECTION INPUT ;
    USE SIGNAL ;
    PORT
      LAYER M4 ;
        RECT  0 83.568 0.084 83.592 ;
    END
  END x_d[300]
  PIN x_d[301]
    DIRECTION INPUT ;
    USE SIGNAL ;
    PORT
      LAYER M4 ;
        RECT  0 83.76 0.084 83.784 ;
    END
  END x_d[301]
  PIN x_d[302]
    DIRECTION INPUT ;
    USE SIGNAL ;
    PORT
      LAYER M4 ;
        RECT  0 84.048 0.084 84.072 ;
    END
  END x_d[302]
  PIN x_d[303]
    DIRECTION INPUT ;
    USE SIGNAL ;
    PORT
      LAYER M4 ;
        RECT  0 84.24 0.084 84.264 ;
    END
  END x_d[303]
  PIN x_d[304]
    DIRECTION INPUT ;
    USE SIGNAL ;
    PORT
      LAYER M4 ;
        RECT  0 84.48 0.084 84.504 ;
    END
  END x_d[304]
  PIN x_d[305]
    DIRECTION INPUT ;
    USE SIGNAL ;
    PORT
      LAYER M4 ;
        RECT  0 84.672 0.084 84.696 ;
    END
  END x_d[305]
  PIN x_d[306]
    DIRECTION INPUT ;
    USE SIGNAL ;
    PORT
      LAYER M4 ;
        RECT  0 84.912 0.084 84.936 ;
    END
  END x_d[306]
  PIN x_d[307]
    DIRECTION INPUT ;
    USE SIGNAL ;
    PORT
      LAYER M4 ;
        RECT  0 85.2 0.084 85.224 ;
    END
  END x_d[307]
  PIN x_d[308]
    DIRECTION INPUT ;
    USE SIGNAL ;
    PORT
      LAYER M4 ;
        RECT  0 85.392 0.084 85.416 ;
    END
  END x_d[308]
  PIN x_d[309]
    DIRECTION INPUT ;
    USE SIGNAL ;
    PORT
      LAYER M4 ;
        RECT  0 85.632 0.084 85.656 ;
    END
  END x_d[309]
  PIN x_d[30]
    DIRECTION INPUT ;
    USE SIGNAL ;
    PORT
      LAYER M4 ;
        RECT  0 16.848 0.084 16.872 ;
    END
  END x_d[30]
  PIN x_d[310]
    DIRECTION INPUT ;
    USE SIGNAL ;
    PORT
      LAYER M4 ;
        RECT  0 85.824 0.084 85.848 ;
    END
  END x_d[310]
  PIN x_d[311]
    DIRECTION INPUT ;
    USE SIGNAL ;
    PORT
      LAYER M4 ;
        RECT  0 86.064 0.084 86.088 ;
    END
  END x_d[311]
  PIN x_d[312]
    DIRECTION INPUT ;
    USE SIGNAL ;
    PORT
      LAYER M4 ;
        RECT  0 86.256 0.084 86.28 ;
    END
  END x_d[312]
  PIN x_d[313]
    DIRECTION INPUT ;
    USE SIGNAL ;
    PORT
      LAYER M4 ;
        RECT  0 86.544 0.084 86.568 ;
    END
  END x_d[313]
  PIN x_d[314]
    DIRECTION INPUT ;
    USE SIGNAL ;
    PORT
      LAYER M4 ;
        RECT  0 86.736 0.084 86.76 ;
    END
  END x_d[314]
  PIN x_d[315]
    DIRECTION INPUT ;
    USE SIGNAL ;
    PORT
      LAYER M4 ;
        RECT  0 86.976 0.084 87 ;
    END
  END x_d[315]
  PIN x_d[316]
    DIRECTION INPUT ;
    USE SIGNAL ;
    PORT
      LAYER M4 ;
        RECT  0 87.168 0.084 87.192 ;
    END
  END x_d[316]
  PIN x_d[317]
    DIRECTION INPUT ;
    USE SIGNAL ;
    PORT
      LAYER M4 ;
        RECT  0 87.408 0.084 87.432 ;
    END
  END x_d[317]
  PIN x_d[318]
    DIRECTION INPUT ;
    USE SIGNAL ;
    PORT
      LAYER M4 ;
        RECT  0 87.6 0.084 87.624 ;
    END
  END x_d[318]
  PIN x_d[319]
    DIRECTION INPUT ;
    USE SIGNAL ;
    PORT
      LAYER M4 ;
        RECT  0 87.888 0.084 87.912 ;
    END
  END x_d[319]
  PIN x_d[31]
    DIRECTION INPUT ;
    USE SIGNAL ;
    PORT
      LAYER M4 ;
        RECT  0 17.136 0.084 17.16 ;
    END
  END x_d[31]
  PIN x_d[32]
    DIRECTION INPUT ;
    USE SIGNAL ;
    PORT
      LAYER M4 ;
        RECT  0 17.472 0.084 17.496 ;
    END
  END x_d[32]
  PIN x_d[33]
    DIRECTION INPUT ;
    USE SIGNAL ;
    PORT
      LAYER M4 ;
        RECT  0 17.808 0.084 17.832 ;
    END
  END x_d[33]
  PIN x_d[34]
    DIRECTION INPUT ;
    USE SIGNAL ;
    PORT
      LAYER M4 ;
        RECT  0 18.192 0.084 18.216 ;
    END
  END x_d[34]
  PIN x_d[35]
    DIRECTION INPUT ;
    USE SIGNAL ;
    PORT
      LAYER M4 ;
        RECT  0 18.48 0.084 18.504 ;
    END
  END x_d[35]
  PIN x_d[36]
    DIRECTION INPUT ;
    USE SIGNAL ;
    PORT
      LAYER M4 ;
        RECT  0 18.864 0.084 18.888 ;
    END
  END x_d[36]
  PIN x_d[37]
    DIRECTION INPUT ;
    USE SIGNAL ;
    PORT
      LAYER M4 ;
        RECT  0 19.152 0.084 19.176 ;
    END
  END x_d[37]
  PIN x_d[38]
    DIRECTION INPUT ;
    USE SIGNAL ;
    PORT
      LAYER M4 ;
        RECT  0 19.44 0.084 19.464 ;
    END
  END x_d[38]
  PIN x_d[39]
    DIRECTION INPUT ;
    USE SIGNAL ;
    PORT
      LAYER M4 ;
        RECT  0 19.824 0.084 19.848 ;
    END
  END x_d[39]
  PIN x_d[3]
    DIRECTION INPUT ;
    USE SIGNAL ;
    PORT
      LAYER M4 ;
        RECT  0 7.872 0.084 7.896 ;
    END
  END x_d[3]
  PIN x_d[40]
    DIRECTION INPUT ;
    USE SIGNAL ;
    PORT
      LAYER M4 ;
        RECT  0 20.16 0.084 20.184 ;
    END
  END x_d[40]
  PIN x_d[41]
    DIRECTION INPUT ;
    USE SIGNAL ;
    PORT
      LAYER M4 ;
        RECT  0 20.496 0.084 20.52 ;
    END
  END x_d[41]
  PIN x_d[42]
    DIRECTION INPUT ;
    USE SIGNAL ;
    PORT
      LAYER M4 ;
        RECT  0 20.784 0.084 20.808 ;
    END
  END x_d[42]
  PIN x_d[43]
    DIRECTION INPUT ;
    USE SIGNAL ;
    PORT
      LAYER M4 ;
        RECT  0 21.12 0.084 21.144 ;
    END
  END x_d[43]
  PIN x_d[44]
    DIRECTION INPUT ;
    USE SIGNAL ;
    PORT
      LAYER M4 ;
        RECT  0 21.504 0.084 21.528 ;
    END
  END x_d[44]
  PIN x_d[45]
    DIRECTION INPUT ;
    USE SIGNAL ;
    PORT
      LAYER M4 ;
        RECT  0 21.84 0.084 21.864 ;
    END
  END x_d[45]
  PIN x_d[46]
    DIRECTION INPUT ;
    USE SIGNAL ;
    PORT
      LAYER M4 ;
        RECT  0 22.128 0.084 22.152 ;
    END
  END x_d[46]
  PIN x_d[47]
    DIRECTION INPUT ;
    USE SIGNAL ;
    PORT
      LAYER M4 ;
        RECT  0 22.512 0.084 22.536 ;
    END
  END x_d[47]
  PIN x_d[48]
    DIRECTION INPUT ;
    USE SIGNAL ;
    PORT
      LAYER M4 ;
        RECT  0 22.896 0.084 22.92 ;
    END
  END x_d[48]
  PIN x_d[49]
    DIRECTION INPUT ;
    USE SIGNAL ;
    PORT
      LAYER M4 ;
        RECT  0 23.184 0.084 23.208 ;
    END
  END x_d[49]
  PIN x_d[4]
    DIRECTION INPUT ;
    USE SIGNAL ;
    PORT
      LAYER M4 ;
        RECT  0 8.16 0.084 8.184 ;
    END
  END x_d[4]
  PIN x_d[50]
    DIRECTION INPUT ;
    USE SIGNAL ;
    PORT
      LAYER M4 ;
        RECT  0 23.472 0.084 23.496 ;
    END
  END x_d[50]
  PIN x_d[51]
    DIRECTION INPUT ;
    USE SIGNAL ;
    PORT
      LAYER M4 ;
        RECT  0 23.808 0.084 23.832 ;
    END
  END x_d[51]
  PIN x_d[52]
    DIRECTION INPUT ;
    USE SIGNAL ;
    PORT
      LAYER M4 ;
        RECT  0 24.144 0.084 24.168 ;
    END
  END x_d[52]
  PIN x_d[53]
    DIRECTION INPUT ;
    USE SIGNAL ;
    PORT
      LAYER M4 ;
        RECT  0 24.576 0.084 24.6 ;
    END
  END x_d[53]
  PIN x_d[54]
    DIRECTION INPUT ;
    USE SIGNAL ;
    PORT
      LAYER M4 ;
        RECT  0 24.816 0.084 24.84 ;
    END
  END x_d[54]
  PIN x_d[55]
    DIRECTION INPUT ;
    USE SIGNAL ;
    PORT
      LAYER M4 ;
        RECT  0 25.152 0.084 25.176 ;
    END
  END x_d[55]
  PIN x_d[56]
    DIRECTION INPUT ;
    USE SIGNAL ;
    PORT
      LAYER M4 ;
        RECT  0 25.488 0.084 25.512 ;
    END
  END x_d[56]
  PIN x_d[57]
    DIRECTION INPUT ;
    USE SIGNAL ;
    PORT
      LAYER M4 ;
        RECT  0 25.824 0.084 25.848 ;
    END
  END x_d[57]
  PIN x_d[58]
    DIRECTION INPUT ;
    USE SIGNAL ;
    PORT
      LAYER M4 ;
        RECT  0 26.16 0.084 26.184 ;
    END
  END x_d[58]
  PIN x_d[59]
    DIRECTION INPUT ;
    USE SIGNAL ;
    PORT
      LAYER M4 ;
        RECT  0 26.496 0.084 26.52 ;
    END
  END x_d[59]
  PIN x_d[5]
    DIRECTION INPUT ;
    USE SIGNAL ;
    PORT
      LAYER M4 ;
        RECT  0 8.496 0.084 8.52 ;
    END
  END x_d[5]
  PIN x_d[60]
    DIRECTION INPUT ;
    USE SIGNAL ;
    PORT
      LAYER M4 ;
        RECT  0 26.832 0.084 26.856 ;
    END
  END x_d[60]
  PIN x_d[61]
    DIRECTION INPUT ;
    USE SIGNAL ;
    PORT
      LAYER M4 ;
        RECT  0 27.168 0.084 27.192 ;
    END
  END x_d[61]
  PIN x_d[62]
    DIRECTION INPUT ;
    USE SIGNAL ;
    PORT
      LAYER M4 ;
        RECT  0 27.504 0.084 27.528 ;
    END
  END x_d[62]
  PIN x_d[63]
    DIRECTION INPUT ;
    USE SIGNAL ;
    PORT
      LAYER M4 ;
        RECT  0 27.84 0.084 27.864 ;
    END
  END x_d[63]
  PIN x_d[64]
    DIRECTION INPUT ;
    USE SIGNAL ;
    PORT
      LAYER M4 ;
        RECT  0 30.096 0.084 30.12 ;
    END
  END x_d[64]
  PIN x_d[65]
    DIRECTION INPUT ;
    USE SIGNAL ;
    PORT
      LAYER M4 ;
        RECT  0 30.336 0.084 30.36 ;
    END
  END x_d[65]
  PIN x_d[66]
    DIRECTION INPUT ;
    USE SIGNAL ;
    PORT
      LAYER M4 ;
        RECT  0 30.576 0.084 30.6 ;
    END
  END x_d[66]
  PIN x_d[67]
    DIRECTION INPUT ;
    USE SIGNAL ;
    PORT
      LAYER M4 ;
        RECT  0 30.768 0.084 30.792 ;
    END
  END x_d[67]
  PIN x_d[68]
    DIRECTION INPUT ;
    USE SIGNAL ;
    PORT
      LAYER M4 ;
        RECT  0 31.008 0.084 31.032 ;
    END
  END x_d[68]
  PIN x_d[69]
    DIRECTION INPUT ;
    USE SIGNAL ;
    PORT
      LAYER M4 ;
        RECT  0 31.248 0.084 31.272 ;
    END
  END x_d[69]
  PIN x_d[6]
    DIRECTION INPUT ;
    USE SIGNAL ;
    PORT
      LAYER M4 ;
        RECT  0 8.832 0.084 8.856 ;
    END
  END x_d[6]
  PIN x_d[70]
    DIRECTION INPUT ;
    USE SIGNAL ;
    PORT
      LAYER M4 ;
        RECT  0 31.44 0.084 31.464 ;
    END
  END x_d[70]
  PIN x_d[71]
    DIRECTION INPUT ;
    USE SIGNAL ;
    PORT
      LAYER M4 ;
        RECT  0 31.68 0.084 31.704 ;
    END
  END x_d[71]
  PIN x_d[72]
    DIRECTION INPUT ;
    USE SIGNAL ;
    PORT
      LAYER M4 ;
        RECT  0 31.92 0.084 31.944 ;
    END
  END x_d[72]
  PIN x_d[73]
    DIRECTION INPUT ;
    USE SIGNAL ;
    PORT
      LAYER M4 ;
        RECT  0 32.16 0.084 32.184 ;
    END
  END x_d[73]
  PIN x_d[74]
    DIRECTION INPUT ;
    USE SIGNAL ;
    PORT
      LAYER M4 ;
        RECT  0 32.352 0.084 32.376 ;
    END
  END x_d[74]
  PIN x_d[75]
    DIRECTION INPUT ;
    USE SIGNAL ;
    PORT
      LAYER M4 ;
        RECT  0 32.592 0.084 32.616 ;
    END
  END x_d[75]
  PIN x_d[76]
    DIRECTION INPUT ;
    USE SIGNAL ;
    PORT
      LAYER M4 ;
        RECT  0 32.832 0.084 32.856 ;
    END
  END x_d[76]
  PIN x_d[77]
    DIRECTION INPUT ;
    USE SIGNAL ;
    PORT
      LAYER M4 ;
        RECT  0 33.024 0.084 33.048 ;
    END
  END x_d[77]
  PIN x_d[78]
    DIRECTION INPUT ;
    USE SIGNAL ;
    PORT
      LAYER M4 ;
        RECT  0 33.264 0.084 33.288 ;
    END
  END x_d[78]
  PIN x_d[79]
    DIRECTION INPUT ;
    USE SIGNAL ;
    PORT
      LAYER M4 ;
        RECT  0 33.504 0.084 33.528 ;
    END
  END x_d[79]
  PIN x_d[7]
    DIRECTION INPUT ;
    USE SIGNAL ;
    PORT
      LAYER M4 ;
        RECT  0 9.168 0.084 9.192 ;
    END
  END x_d[7]
  PIN x_d[80]
    DIRECTION INPUT ;
    USE SIGNAL ;
    PORT
      LAYER M4 ;
        RECT  0 33.744 0.084 33.768 ;
    END
  END x_d[80]
  PIN x_d[81]
    DIRECTION INPUT ;
    USE SIGNAL ;
    PORT
      LAYER M4 ;
        RECT  0 33.936 0.084 33.96 ;
    END
  END x_d[81]
  PIN x_d[82]
    DIRECTION INPUT ;
    USE SIGNAL ;
    PORT
      LAYER M4 ;
        RECT  0 34.176 0.084 34.2 ;
    END
  END x_d[82]
  PIN x_d[83]
    DIRECTION INPUT ;
    USE SIGNAL ;
    PORT
      LAYER M4 ;
        RECT  0 34.416 0.084 34.44 ;
    END
  END x_d[83]
  PIN x_d[84]
    DIRECTION INPUT ;
    USE SIGNAL ;
    PORT
      LAYER M4 ;
        RECT  0 34.656 0.084 34.68 ;
    END
  END x_d[84]
  PIN x_d[85]
    DIRECTION INPUT ;
    USE SIGNAL ;
    PORT
      LAYER M4 ;
        RECT  0 34.848 0.084 34.872 ;
    END
  END x_d[85]
  PIN x_d[86]
    DIRECTION INPUT ;
    USE SIGNAL ;
    PORT
      LAYER M4 ;
        RECT  0 35.088 0.084 35.112 ;
    END
  END x_d[86]
  PIN x_d[87]
    DIRECTION INPUT ;
    USE SIGNAL ;
    PORT
      LAYER M4 ;
        RECT  0 35.328 0.084 35.352 ;
    END
  END x_d[87]
  PIN x_d[88]
    DIRECTION INPUT ;
    USE SIGNAL ;
    PORT
      LAYER M4 ;
        RECT  0 35.52 0.084 35.544 ;
    END
  END x_d[88]
  PIN x_d[89]
    DIRECTION INPUT ;
    USE SIGNAL ;
    PORT
      LAYER M4 ;
        RECT  0 35.76 0.084 35.784 ;
    END
  END x_d[89]
  PIN x_d[8]
    DIRECTION INPUT ;
    USE SIGNAL ;
    PORT
      LAYER M4 ;
        RECT  0 9.504 0.084 9.528 ;
    END
  END x_d[8]
  PIN x_d[90]
    DIRECTION INPUT ;
    USE SIGNAL ;
    PORT
      LAYER M4 ;
        RECT  0 36 0.084 36.024 ;
    END
  END x_d[90]
  PIN x_d[91]
    DIRECTION INPUT ;
    USE SIGNAL ;
    PORT
      LAYER M4 ;
        RECT  0 36.24 0.084 36.264 ;
    END
  END x_d[91]
  PIN x_d[92]
    DIRECTION INPUT ;
    USE SIGNAL ;
    PORT
      LAYER M4 ;
        RECT  0 36.432 0.084 36.456 ;
    END
  END x_d[92]
  PIN x_d[93]
    DIRECTION INPUT ;
    USE SIGNAL ;
    PORT
      LAYER M4 ;
        RECT  0 36.672 0.084 36.696 ;
    END
  END x_d[93]
  PIN x_d[94]
    DIRECTION INPUT ;
    USE SIGNAL ;
    PORT
      LAYER M4 ;
        RECT  0 36.912 0.084 36.936 ;
    END
  END x_d[94]
  PIN x_d[95]
    DIRECTION INPUT ;
    USE SIGNAL ;
    PORT
      LAYER M4 ;
        RECT  0 37.104 0.084 37.128 ;
    END
  END x_d[95]
  PIN x_d[96]
    DIRECTION INPUT ;
    USE SIGNAL ;
    PORT
      LAYER M4 ;
        RECT  0 37.392 0.084 37.416 ;
    END
  END x_d[96]
  PIN x_d[97]
    DIRECTION INPUT ;
    USE SIGNAL ;
    PORT
      LAYER M4 ;
        RECT  0 37.584 0.084 37.608 ;
    END
  END x_d[97]
  PIN x_d[98]
    DIRECTION INPUT ;
    USE SIGNAL ;
    PORT
      LAYER M4 ;
        RECT  0 37.824 0.084 37.848 ;
    END
  END x_d[98]
  PIN x_d[99]
    DIRECTION INPUT ;
    USE SIGNAL ;
    PORT
      LAYER M4 ;
        RECT  0 38.016 0.084 38.04 ;
    END
  END x_d[99]
  PIN x_d[9]
    DIRECTION INPUT ;
    USE SIGNAL ;
    PORT
      LAYER M4 ;
        RECT  0 9.84 0.084 9.864 ;
    END
  END x_d[9]
  PIN x_d_q[0]
    DIRECTION OUTPUT ;
    USE SIGNAL ;
    PORT
      LAYER M4 ;
        RECT  36.204 6.816 36.288 6.84 ;
    END
  END x_d_q[0]
  PIN x_d_q[100]
    DIRECTION OUTPUT ;
    USE SIGNAL ;
    PORT
      LAYER M4 ;
        RECT  36.204 38.256 36.288 38.28 ;
    END
  END x_d_q[100]
  PIN x_d_q[101]
    DIRECTION OUTPUT ;
    USE SIGNAL ;
    PORT
      LAYER M4 ;
        RECT  36.204 38.448 36.288 38.472 ;
    END
  END x_d_q[101]
  PIN x_d_q[102]
    DIRECTION OUTPUT ;
    USE SIGNAL ;
    PORT
      LAYER M4 ;
        RECT  36.204 38.736 36.288 38.76 ;
    END
  END x_d_q[102]
  PIN x_d_q[103]
    DIRECTION OUTPUT ;
    USE SIGNAL ;
    PORT
      LAYER M4 ;
        RECT  36.204 38.928 36.288 38.952 ;
    END
  END x_d_q[103]
  PIN x_d_q[104]
    DIRECTION OUTPUT ;
    USE SIGNAL ;
    PORT
      LAYER M4 ;
        RECT  36.204 39.168 36.288 39.192 ;
    END
  END x_d_q[104]
  PIN x_d_q[105]
    DIRECTION OUTPUT ;
    USE SIGNAL ;
    PORT
      LAYER M4 ;
        RECT  36.204 39.36 36.288 39.384 ;
    END
  END x_d_q[105]
  PIN x_d_q[106]
    DIRECTION OUTPUT ;
    USE SIGNAL ;
    PORT
      LAYER M4 ;
        RECT  36.204 39.6 36.288 39.624 ;
    END
  END x_d_q[106]
  PIN x_d_q[107]
    DIRECTION OUTPUT ;
    USE SIGNAL ;
    PORT
      LAYER M4 ;
        RECT  36.204 39.792 36.288 39.816 ;
    END
  END x_d_q[107]
  PIN x_d_q[108]
    DIRECTION OUTPUT ;
    USE SIGNAL ;
    PORT
      LAYER M4 ;
        RECT  36.204 40.08 36.288 40.104 ;
    END
  END x_d_q[108]
  PIN x_d_q[109]
    DIRECTION OUTPUT ;
    USE SIGNAL ;
    PORT
      LAYER M4 ;
        RECT  36.204 40.32 36.288 40.344 ;
    END
  END x_d_q[109]
  PIN x_d_q[10]
    DIRECTION OUTPUT ;
    USE SIGNAL ;
    PORT
      LAYER M4 ;
        RECT  36.204 10.176 36.288 10.2 ;
    END
  END x_d_q[10]
  PIN x_d_q[110]
    DIRECTION OUTPUT ;
    USE SIGNAL ;
    PORT
      LAYER M4 ;
        RECT  36.204 40.512 36.288 40.536 ;
    END
  END x_d_q[110]
  PIN x_d_q[111]
    DIRECTION OUTPUT ;
    USE SIGNAL ;
    PORT
      LAYER M4 ;
        RECT  36.204 40.752 36.288 40.776 ;
    END
  END x_d_q[111]
  PIN x_d_q[112]
    DIRECTION OUTPUT ;
    USE SIGNAL ;
    PORT
      LAYER M4 ;
        RECT  36.204 40.944 36.288 40.968 ;
    END
  END x_d_q[112]
  PIN x_d_q[113]
    DIRECTION OUTPUT ;
    USE SIGNAL ;
    PORT
      LAYER M4 ;
        RECT  36.204 41.232 36.288 41.256 ;
    END
  END x_d_q[113]
  PIN x_d_q[114]
    DIRECTION OUTPUT ;
    USE SIGNAL ;
    PORT
      LAYER M4 ;
        RECT  36.204 41.424 36.288 41.448 ;
    END
  END x_d_q[114]
  PIN x_d_q[115]
    DIRECTION OUTPUT ;
    USE SIGNAL ;
    PORT
      LAYER M4 ;
        RECT  36.204 41.664 36.288 41.688 ;
    END
  END x_d_q[115]
  PIN x_d_q[116]
    DIRECTION OUTPUT ;
    USE SIGNAL ;
    PORT
      LAYER M4 ;
        RECT  36.204 41.856 36.288 41.88 ;
    END
  END x_d_q[116]
  PIN x_d_q[117]
    DIRECTION OUTPUT ;
    USE SIGNAL ;
    PORT
      LAYER M4 ;
        RECT  36.204 42.096 36.288 42.12 ;
    END
  END x_d_q[117]
  PIN x_d_q[118]
    DIRECTION OUTPUT ;
    USE SIGNAL ;
    PORT
      LAYER M4 ;
        RECT  36.204 42.288 36.288 42.312 ;
    END
  END x_d_q[118]
  PIN x_d_q[119]
    DIRECTION OUTPUT ;
    USE SIGNAL ;
    PORT
      LAYER M4 ;
        RECT  36.204 42.576 36.288 42.6 ;
    END
  END x_d_q[119]
  PIN x_d_q[11]
    DIRECTION OUTPUT ;
    USE SIGNAL ;
    PORT
      LAYER M4 ;
        RECT  36.204 10.512 36.288 10.536 ;
    END
  END x_d_q[11]
  PIN x_d_q[120]
    DIRECTION OUTPUT ;
    USE SIGNAL ;
    PORT
      LAYER M4 ;
        RECT  36.204 42.816 36.288 42.84 ;
    END
  END x_d_q[120]
  PIN x_d_q[121]
    DIRECTION OUTPUT ;
    USE SIGNAL ;
    PORT
      LAYER M4 ;
        RECT  36.204 43.008 36.288 43.032 ;
    END
  END x_d_q[121]
  PIN x_d_q[122]
    DIRECTION OUTPUT ;
    USE SIGNAL ;
    PORT
      LAYER M4 ;
        RECT  36.204 43.248 36.288 43.272 ;
    END
  END x_d_q[122]
  PIN x_d_q[123]
    DIRECTION OUTPUT ;
    USE SIGNAL ;
    PORT
      LAYER M4 ;
        RECT  36.204 43.44 36.288 43.464 ;
    END
  END x_d_q[123]
  PIN x_d_q[124]
    DIRECTION OUTPUT ;
    USE SIGNAL ;
    PORT
      LAYER M4 ;
        RECT  36.204 43.728 36.288 43.752 ;
    END
  END x_d_q[124]
  PIN x_d_q[125]
    DIRECTION OUTPUT ;
    USE SIGNAL ;
    PORT
      LAYER M4 ;
        RECT  36.204 43.92 36.288 43.944 ;
    END
  END x_d_q[125]
  PIN x_d_q[126]
    DIRECTION OUTPUT ;
    USE SIGNAL ;
    PORT
      LAYER M4 ;
        RECT  36.204 44.16 36.288 44.184 ;
    END
  END x_d_q[126]
  PIN x_d_q[127]
    DIRECTION OUTPUT ;
    USE SIGNAL ;
    PORT
      LAYER M4 ;
        RECT  36.204 44.352 36.288 44.376 ;
    END
  END x_d_q[127]
  PIN x_d_q[128]
    DIRECTION OUTPUT ;
    USE SIGNAL ;
    PORT
      LAYER M4 ;
        RECT  36.204 44.592 36.288 44.616 ;
    END
  END x_d_q[128]
  PIN x_d_q[129]
    DIRECTION OUTPUT ;
    USE SIGNAL ;
    PORT
      LAYER M4 ;
        RECT  36.204 44.832 36.288 44.856 ;
    END
  END x_d_q[129]
  PIN x_d_q[12]
    DIRECTION OUTPUT ;
    USE SIGNAL ;
    PORT
      LAYER M4 ;
        RECT  36.204 10.8 36.288 10.824 ;
    END
  END x_d_q[12]
  PIN x_d_q[130]
    DIRECTION OUTPUT ;
    USE SIGNAL ;
    PORT
      LAYER M4 ;
        RECT  36.204 45.072 36.288 45.096 ;
    END
  END x_d_q[130]
  PIN x_d_q[131]
    DIRECTION OUTPUT ;
    USE SIGNAL ;
    PORT
      LAYER M4 ;
        RECT  36.204 45.264 36.288 45.288 ;
    END
  END x_d_q[131]
  PIN x_d_q[132]
    DIRECTION OUTPUT ;
    USE SIGNAL ;
    PORT
      LAYER M4 ;
        RECT  36.204 45.504 36.288 45.528 ;
    END
  END x_d_q[132]
  PIN x_d_q[133]
    DIRECTION OUTPUT ;
    USE SIGNAL ;
    PORT
      LAYER M4 ;
        RECT  36.204 45.744 36.288 45.768 ;
    END
  END x_d_q[133]
  PIN x_d_q[134]
    DIRECTION OUTPUT ;
    USE SIGNAL ;
    PORT
      LAYER M4 ;
        RECT  36.204 45.984 36.288 46.008 ;
    END
  END x_d_q[134]
  PIN x_d_q[135]
    DIRECTION OUTPUT ;
    USE SIGNAL ;
    PORT
      LAYER M4 ;
        RECT  36.204 46.176 36.288 46.2 ;
    END
  END x_d_q[135]
  PIN x_d_q[136]
    DIRECTION OUTPUT ;
    USE SIGNAL ;
    PORT
      LAYER M4 ;
        RECT  36.204 46.416 36.288 46.44 ;
    END
  END x_d_q[136]
  PIN x_d_q[137]
    DIRECTION OUTPUT ;
    USE SIGNAL ;
    PORT
      LAYER M4 ;
        RECT  36.204 46.656 36.288 46.68 ;
    END
  END x_d_q[137]
  PIN x_d_q[138]
    DIRECTION OUTPUT ;
    USE SIGNAL ;
    PORT
      LAYER M4 ;
        RECT  36.204 46.848 36.288 46.872 ;
    END
  END x_d_q[138]
  PIN x_d_q[139]
    DIRECTION OUTPUT ;
    USE SIGNAL ;
    PORT
      LAYER M4 ;
        RECT  36.204 47.088 36.288 47.112 ;
    END
  END x_d_q[139]
  PIN x_d_q[13]
    DIRECTION OUTPUT ;
    USE SIGNAL ;
    PORT
      LAYER M4 ;
        RECT  36.204 11.136 36.288 11.16 ;
    END
  END x_d_q[13]
  PIN x_d_q[140]
    DIRECTION OUTPUT ;
    USE SIGNAL ;
    PORT
      LAYER M4 ;
        RECT  36.204 47.328 36.288 47.352 ;
    END
  END x_d_q[140]
  PIN x_d_q[141]
    DIRECTION OUTPUT ;
    USE SIGNAL ;
    PORT
      LAYER M4 ;
        RECT  36.204 47.568 36.288 47.592 ;
    END
  END x_d_q[141]
  PIN x_d_q[142]
    DIRECTION OUTPUT ;
    USE SIGNAL ;
    PORT
      LAYER M4 ;
        RECT  36.204 47.76 36.288 47.784 ;
    END
  END x_d_q[142]
  PIN x_d_q[143]
    DIRECTION OUTPUT ;
    USE SIGNAL ;
    PORT
      LAYER M4 ;
        RECT  36.204 48 36.288 48.024 ;
    END
  END x_d_q[143]
  PIN x_d_q[144]
    DIRECTION OUTPUT ;
    USE SIGNAL ;
    PORT
      LAYER M4 ;
        RECT  36.204 48.24 36.288 48.264 ;
    END
  END x_d_q[144]
  PIN x_d_q[145]
    DIRECTION OUTPUT ;
    USE SIGNAL ;
    PORT
      LAYER M4 ;
        RECT  36.204 48.432 36.288 48.456 ;
    END
  END x_d_q[145]
  PIN x_d_q[146]
    DIRECTION OUTPUT ;
    USE SIGNAL ;
    PORT
      LAYER M4 ;
        RECT  36.204 48.672 36.288 48.696 ;
    END
  END x_d_q[146]
  PIN x_d_q[147]
    DIRECTION OUTPUT ;
    USE SIGNAL ;
    PORT
      LAYER M4 ;
        RECT  36.204 48.912 36.288 48.936 ;
    END
  END x_d_q[147]
  PIN x_d_q[148]
    DIRECTION OUTPUT ;
    USE SIGNAL ;
    PORT
      LAYER M4 ;
        RECT  36.204 49.152 36.288 49.176 ;
    END
  END x_d_q[148]
  PIN x_d_q[149]
    DIRECTION OUTPUT ;
    USE SIGNAL ;
    PORT
      LAYER M4 ;
        RECT  36.204 49.344 36.288 49.368 ;
    END
  END x_d_q[149]
  PIN x_d_q[14]
    DIRECTION OUTPUT ;
    USE SIGNAL ;
    PORT
      LAYER M4 ;
        RECT  36.204 11.472 36.288 11.496 ;
    END
  END x_d_q[14]
  PIN x_d_q[150]
    DIRECTION OUTPUT ;
    USE SIGNAL ;
    PORT
      LAYER M4 ;
        RECT  36.204 49.584 36.288 49.608 ;
    END
  END x_d_q[150]
  PIN x_d_q[151]
    DIRECTION OUTPUT ;
    USE SIGNAL ;
    PORT
      LAYER M4 ;
        RECT  36.204 49.824 36.288 49.848 ;
    END
  END x_d_q[151]
  PIN x_d_q[152]
    DIRECTION OUTPUT ;
    USE SIGNAL ;
    PORT
      LAYER M4 ;
        RECT  36.204 50.016 36.288 50.04 ;
    END
  END x_d_q[152]
  PIN x_d_q[153]
    DIRECTION OUTPUT ;
    USE SIGNAL ;
    PORT
      LAYER M4 ;
        RECT  36.204 50.256 36.288 50.28 ;
    END
  END x_d_q[153]
  PIN x_d_q[154]
    DIRECTION OUTPUT ;
    USE SIGNAL ;
    PORT
      LAYER M4 ;
        RECT  36.204 50.496 36.288 50.52 ;
    END
  END x_d_q[154]
  PIN x_d_q[155]
    DIRECTION OUTPUT ;
    USE SIGNAL ;
    PORT
      LAYER M4 ;
        RECT  36.204 50.736 36.288 50.76 ;
    END
  END x_d_q[155]
  PIN x_d_q[156]
    DIRECTION OUTPUT ;
    USE SIGNAL ;
    PORT
      LAYER M4 ;
        RECT  36.204 50.928 36.288 50.952 ;
    END
  END x_d_q[156]
  PIN x_d_q[157]
    DIRECTION OUTPUT ;
    USE SIGNAL ;
    PORT
      LAYER M4 ;
        RECT  36.204 51.168 36.288 51.192 ;
    END
  END x_d_q[157]
  PIN x_d_q[158]
    DIRECTION OUTPUT ;
    USE SIGNAL ;
    PORT
      LAYER M4 ;
        RECT  36.204 51.408 36.288 51.432 ;
    END
  END x_d_q[158]
  PIN x_d_q[159]
    DIRECTION OUTPUT ;
    USE SIGNAL ;
    PORT
      LAYER M4 ;
        RECT  36.204 51.648 36.288 51.672 ;
    END
  END x_d_q[159]
  PIN x_d_q[15]
    DIRECTION OUTPUT ;
    USE SIGNAL ;
    PORT
      LAYER M4 ;
        RECT  36.204 11.808 36.288 11.832 ;
    END
  END x_d_q[15]
  PIN x_d_q[160]
    DIRECTION OUTPUT ;
    USE SIGNAL ;
    PORT
      LAYER M4 ;
        RECT  36.204 51.84 36.288 51.864 ;
    END
  END x_d_q[160]
  PIN x_d_q[161]
    DIRECTION OUTPUT ;
    USE SIGNAL ;
    PORT
      LAYER M4 ;
        RECT  36.204 52.08 36.288 52.104 ;
    END
  END x_d_q[161]
  PIN x_d_q[162]
    DIRECTION OUTPUT ;
    USE SIGNAL ;
    PORT
      LAYER M4 ;
        RECT  36.204 52.272 36.288 52.296 ;
    END
  END x_d_q[162]
  PIN x_d_q[163]
    DIRECTION OUTPUT ;
    USE SIGNAL ;
    PORT
      LAYER M4 ;
        RECT  36.204 52.56 36.288 52.584 ;
    END
  END x_d_q[163]
  PIN x_d_q[164]
    DIRECTION OUTPUT ;
    USE SIGNAL ;
    PORT
      LAYER M4 ;
        RECT  36.204 52.752 36.288 52.776 ;
    END
  END x_d_q[164]
  PIN x_d_q[165]
    DIRECTION OUTPUT ;
    USE SIGNAL ;
    PORT
      LAYER M4 ;
        RECT  36.204 52.992 36.288 53.016 ;
    END
  END x_d_q[165]
  PIN x_d_q[166]
    DIRECTION OUTPUT ;
    USE SIGNAL ;
    PORT
      LAYER M4 ;
        RECT  36.204 53.184 36.288 53.208 ;
    END
  END x_d_q[166]
  PIN x_d_q[167]
    DIRECTION OUTPUT ;
    USE SIGNAL ;
    PORT
      LAYER M4 ;
        RECT  36.204 53.424 36.288 53.448 ;
    END
  END x_d_q[167]
  PIN x_d_q[168]
    DIRECTION OUTPUT ;
    USE SIGNAL ;
    PORT
      LAYER M4 ;
        RECT  36.204 53.616 36.288 53.64 ;
    END
  END x_d_q[168]
  PIN x_d_q[169]
    DIRECTION OUTPUT ;
    USE SIGNAL ;
    PORT
      LAYER M4 ;
        RECT  36.204 53.904 36.288 53.928 ;
    END
  END x_d_q[169]
  PIN x_d_q[16]
    DIRECTION OUTPUT ;
    USE SIGNAL ;
    PORT
      LAYER M4 ;
        RECT  36.204 12.144 36.288 12.168 ;
    END
  END x_d_q[16]
  PIN x_d_q[170]
    DIRECTION OUTPUT ;
    USE SIGNAL ;
    PORT
      LAYER M4 ;
        RECT  36.204 54.144 36.288 54.168 ;
    END
  END x_d_q[170]
  PIN x_d_q[171]
    DIRECTION OUTPUT ;
    USE SIGNAL ;
    PORT
      LAYER M4 ;
        RECT  36.204 54.336 36.288 54.36 ;
    END
  END x_d_q[171]
  PIN x_d_q[172]
    DIRECTION OUTPUT ;
    USE SIGNAL ;
    PORT
      LAYER M4 ;
        RECT  36.204 54.576 36.288 54.6 ;
    END
  END x_d_q[172]
  PIN x_d_q[173]
    DIRECTION OUTPUT ;
    USE SIGNAL ;
    PORT
      LAYER M4 ;
        RECT  36.204 54.768 36.288 54.792 ;
    END
  END x_d_q[173]
  PIN x_d_q[174]
    DIRECTION OUTPUT ;
    USE SIGNAL ;
    PORT
      LAYER M4 ;
        RECT  36.204 55.056 36.288 55.08 ;
    END
  END x_d_q[174]
  PIN x_d_q[175]
    DIRECTION OUTPUT ;
    USE SIGNAL ;
    PORT
      LAYER M4 ;
        RECT  36.204 55.248 36.288 55.272 ;
    END
  END x_d_q[175]
  PIN x_d_q[176]
    DIRECTION OUTPUT ;
    USE SIGNAL ;
    PORT
      LAYER M4 ;
        RECT  36.204 55.488 36.288 55.512 ;
    END
  END x_d_q[176]
  PIN x_d_q[177]
    DIRECTION OUTPUT ;
    USE SIGNAL ;
    PORT
      LAYER M4 ;
        RECT  36.204 55.68 36.288 55.704 ;
    END
  END x_d_q[177]
  PIN x_d_q[178]
    DIRECTION OUTPUT ;
    USE SIGNAL ;
    PORT
      LAYER M4 ;
        RECT  36.204 55.92 36.288 55.944 ;
    END
  END x_d_q[178]
  PIN x_d_q[179]
    DIRECTION OUTPUT ;
    USE SIGNAL ;
    PORT
      LAYER M4 ;
        RECT  36.204 56.112 36.288 56.136 ;
    END
  END x_d_q[179]
  PIN x_d_q[17]
    DIRECTION OUTPUT ;
    USE SIGNAL ;
    PORT
      LAYER M4 ;
        RECT  36.204 12.48 36.288 12.504 ;
    END
  END x_d_q[17]
  PIN x_d_q[180]
    DIRECTION OUTPUT ;
    USE SIGNAL ;
    PORT
      LAYER M4 ;
        RECT  36.204 56.4 36.288 56.424 ;
    END
  END x_d_q[180]
  PIN x_d_q[181]
    DIRECTION OUTPUT ;
    USE SIGNAL ;
    PORT
      LAYER M4 ;
        RECT  36.204 56.592 36.288 56.616 ;
    END
  END x_d_q[181]
  PIN x_d_q[182]
    DIRECTION OUTPUT ;
    USE SIGNAL ;
    PORT
      LAYER M4 ;
        RECT  36.204 56.832 36.288 56.856 ;
    END
  END x_d_q[182]
  PIN x_d_q[183]
    DIRECTION OUTPUT ;
    USE SIGNAL ;
    PORT
      LAYER M4 ;
        RECT  36.204 57.072 36.288 57.096 ;
    END
  END x_d_q[183]
  PIN x_d_q[184]
    DIRECTION OUTPUT ;
    USE SIGNAL ;
    PORT
      LAYER M4 ;
        RECT  36.204 57.264 36.288 57.288 ;
    END
  END x_d_q[184]
  PIN x_d_q[185]
    DIRECTION OUTPUT ;
    USE SIGNAL ;
    PORT
      LAYER M4 ;
        RECT  36.204 57.552 36.288 57.576 ;
    END
  END x_d_q[185]
  PIN x_d_q[186]
    DIRECTION OUTPUT ;
    USE SIGNAL ;
    PORT
      LAYER M4 ;
        RECT  36.204 57.744 36.288 57.768 ;
    END
  END x_d_q[186]
  PIN x_d_q[187]
    DIRECTION OUTPUT ;
    USE SIGNAL ;
    PORT
      LAYER M4 ;
        RECT  36.204 57.984 36.288 58.008 ;
    END
  END x_d_q[187]
  PIN x_d_q[188]
    DIRECTION OUTPUT ;
    USE SIGNAL ;
    PORT
      LAYER M4 ;
        RECT  36.204 58.176 36.288 58.2 ;
    END
  END x_d_q[188]
  PIN x_d_q[189]
    DIRECTION OUTPUT ;
    USE SIGNAL ;
    PORT
      LAYER M4 ;
        RECT  36.204 58.416 36.288 58.44 ;
    END
  END x_d_q[189]
  PIN x_d_q[18]
    DIRECTION OUTPUT ;
    USE SIGNAL ;
    PORT
      LAYER M4 ;
        RECT  36.204 12.816 36.288 12.84 ;
    END
  END x_d_q[18]
  PIN x_d_q[190]
    DIRECTION OUTPUT ;
    USE SIGNAL ;
    PORT
      LAYER M4 ;
        RECT  36.204 58.608 36.288 58.632 ;
    END
  END x_d_q[190]
  PIN x_d_q[191]
    DIRECTION OUTPUT ;
    USE SIGNAL ;
    PORT
      LAYER M4 ;
        RECT  36.204 58.896 36.288 58.92 ;
    END
  END x_d_q[191]
  PIN x_d_q[192]
    DIRECTION OUTPUT ;
    USE SIGNAL ;
    PORT
      LAYER M4 ;
        RECT  36.204 59.088 36.288 59.112 ;
    END
  END x_d_q[192]
  PIN x_d_q[193]
    DIRECTION OUTPUT ;
    USE SIGNAL ;
    PORT
      LAYER M4 ;
        RECT  36.204 59.328 36.288 59.352 ;
    END
  END x_d_q[193]
  PIN x_d_q[194]
    DIRECTION OUTPUT ;
    USE SIGNAL ;
    PORT
      LAYER M4 ;
        RECT  36.204 59.568 36.288 59.592 ;
    END
  END x_d_q[194]
  PIN x_d_q[195]
    DIRECTION OUTPUT ;
    USE SIGNAL ;
    PORT
      LAYER M4 ;
        RECT  36.204 59.76 36.288 59.784 ;
    END
  END x_d_q[195]
  PIN x_d_q[196]
    DIRECTION OUTPUT ;
    USE SIGNAL ;
    PORT
      LAYER M4 ;
        RECT  36.204 60 36.288 60.024 ;
    END
  END x_d_q[196]
  PIN x_d_q[197]
    DIRECTION OUTPUT ;
    USE SIGNAL ;
    PORT
      LAYER M4 ;
        RECT  36.204 60.24 36.288 60.264 ;
    END
  END x_d_q[197]
  PIN x_d_q[198]
    DIRECTION OUTPUT ;
    USE SIGNAL ;
    PORT
      LAYER M4 ;
        RECT  36.204 60.48 36.288 60.504 ;
    END
  END x_d_q[198]
  PIN x_d_q[199]
    DIRECTION OUTPUT ;
    USE SIGNAL ;
    PORT
      LAYER M4 ;
        RECT  36.204 60.672 36.288 60.696 ;
    END
  END x_d_q[199]
  PIN x_d_q[19]
    DIRECTION OUTPUT ;
    USE SIGNAL ;
    PORT
      LAYER M4 ;
        RECT  36.204 13.152 36.288 13.176 ;
    END
  END x_d_q[19]
  PIN x_d_q[1]
    DIRECTION OUTPUT ;
    USE SIGNAL ;
    PORT
      LAYER M4 ;
        RECT  36.204 7.152 36.288 7.176 ;
    END
  END x_d_q[1]
  PIN x_d_q[200]
    DIRECTION OUTPUT ;
    USE SIGNAL ;
    PORT
      LAYER M4 ;
        RECT  36.204 60.912 36.288 60.936 ;
    END
  END x_d_q[200]
  PIN x_d_q[201]
    DIRECTION OUTPUT ;
    USE SIGNAL ;
    PORT
      LAYER M4 ;
        RECT  36.204 61.152 36.288 61.176 ;
    END
  END x_d_q[201]
  PIN x_d_q[202]
    DIRECTION OUTPUT ;
    USE SIGNAL ;
    PORT
      LAYER M4 ;
        RECT  36.204 61.344 36.288 61.368 ;
    END
  END x_d_q[202]
  PIN x_d_q[203]
    DIRECTION OUTPUT ;
    USE SIGNAL ;
    PORT
      LAYER M4 ;
        RECT  36.204 61.584 36.288 61.608 ;
    END
  END x_d_q[203]
  PIN x_d_q[204]
    DIRECTION OUTPUT ;
    USE SIGNAL ;
    PORT
      LAYER M4 ;
        RECT  36.204 61.824 36.288 61.848 ;
    END
  END x_d_q[204]
  PIN x_d_q[205]
    DIRECTION OUTPUT ;
    USE SIGNAL ;
    PORT
      LAYER M4 ;
        RECT  36.204 62.064 36.288 62.088 ;
    END
  END x_d_q[205]
  PIN x_d_q[206]
    DIRECTION OUTPUT ;
    USE SIGNAL ;
    PORT
      LAYER M4 ;
        RECT  36.204 62.256 36.288 62.28 ;
    END
  END x_d_q[206]
  PIN x_d_q[207]
    DIRECTION OUTPUT ;
    USE SIGNAL ;
    PORT
      LAYER M4 ;
        RECT  36.204 62.496 36.288 62.52 ;
    END
  END x_d_q[207]
  PIN x_d_q[208]
    DIRECTION OUTPUT ;
    USE SIGNAL ;
    PORT
      LAYER M4 ;
        RECT  36.204 62.736 36.288 62.76 ;
    END
  END x_d_q[208]
  PIN x_d_q[209]
    DIRECTION OUTPUT ;
    USE SIGNAL ;
    PORT
      LAYER M4 ;
        RECT  36.204 62.976 36.288 63 ;
    END
  END x_d_q[209]
  PIN x_d_q[20]
    DIRECTION OUTPUT ;
    USE SIGNAL ;
    PORT
      LAYER M4 ;
        RECT  36.204 13.488 36.288 13.512 ;
    END
  END x_d_q[20]
  PIN x_d_q[210]
    DIRECTION OUTPUT ;
    USE SIGNAL ;
    PORT
      LAYER M4 ;
        RECT  36.204 63.168 36.288 63.192 ;
    END
  END x_d_q[210]
  PIN x_d_q[211]
    DIRECTION OUTPUT ;
    USE SIGNAL ;
    PORT
      LAYER M4 ;
        RECT  36.204 63.408 36.288 63.432 ;
    END
  END x_d_q[211]
  PIN x_d_q[212]
    DIRECTION OUTPUT ;
    USE SIGNAL ;
    PORT
      LAYER M4 ;
        RECT  36.204 63.648 36.288 63.672 ;
    END
  END x_d_q[212]
  PIN x_d_q[213]
    DIRECTION OUTPUT ;
    USE SIGNAL ;
    PORT
      LAYER M4 ;
        RECT  36.204 63.84 36.288 63.864 ;
    END
  END x_d_q[213]
  PIN x_d_q[214]
    DIRECTION OUTPUT ;
    USE SIGNAL ;
    PORT
      LAYER M4 ;
        RECT  36.204 64.08 36.288 64.104 ;
    END
  END x_d_q[214]
  PIN x_d_q[215]
    DIRECTION OUTPUT ;
    USE SIGNAL ;
    PORT
      LAYER M4 ;
        RECT  36.204 64.32 36.288 64.344 ;
    END
  END x_d_q[215]
  PIN x_d_q[216]
    DIRECTION OUTPUT ;
    USE SIGNAL ;
    PORT
      LAYER M4 ;
        RECT  36.204 64.56 36.288 64.584 ;
    END
  END x_d_q[216]
  PIN x_d_q[217]
    DIRECTION OUTPUT ;
    USE SIGNAL ;
    PORT
      LAYER M4 ;
        RECT  36.204 64.752 36.288 64.776 ;
    END
  END x_d_q[217]
  PIN x_d_q[218]
    DIRECTION OUTPUT ;
    USE SIGNAL ;
    PORT
      LAYER M4 ;
        RECT  36.204 64.992 36.288 65.016 ;
    END
  END x_d_q[218]
  PIN x_d_q[219]
    DIRECTION OUTPUT ;
    USE SIGNAL ;
    PORT
      LAYER M4 ;
        RECT  36.204 65.232 36.288 65.256 ;
    END
  END x_d_q[219]
  PIN x_d_q[21]
    DIRECTION OUTPUT ;
    USE SIGNAL ;
    PORT
      LAYER M4 ;
        RECT  36.204 13.824 36.288 13.848 ;
    END
  END x_d_q[21]
  PIN x_d_q[220]
    DIRECTION OUTPUT ;
    USE SIGNAL ;
    PORT
      LAYER M4 ;
        RECT  36.204 65.424 36.288 65.448 ;
    END
  END x_d_q[220]
  PIN x_d_q[221]
    DIRECTION OUTPUT ;
    USE SIGNAL ;
    PORT
      LAYER M4 ;
        RECT  36.204 65.664 36.288 65.688 ;
    END
  END x_d_q[221]
  PIN x_d_q[222]
    DIRECTION OUTPUT ;
    USE SIGNAL ;
    PORT
      LAYER M4 ;
        RECT  36.204 65.904 36.288 65.928 ;
    END
  END x_d_q[222]
  PIN x_d_q[223]
    DIRECTION OUTPUT ;
    USE SIGNAL ;
    PORT
      LAYER M4 ;
        RECT  36.204 66.144 36.288 66.168 ;
    END
  END x_d_q[223]
  PIN x_d_q[224]
    DIRECTION OUTPUT ;
    USE SIGNAL ;
    PORT
      LAYER M4 ;
        RECT  36.204 66.384 36.288 66.408 ;
    END
  END x_d_q[224]
  PIN x_d_q[225]
    DIRECTION OUTPUT ;
    USE SIGNAL ;
    PORT
      LAYER M4 ;
        RECT  36.204 66.576 36.288 66.6 ;
    END
  END x_d_q[225]
  PIN x_d_q[226]
    DIRECTION OUTPUT ;
    USE SIGNAL ;
    PORT
      LAYER M4 ;
        RECT  36.204 66.816 36.288 66.84 ;
    END
  END x_d_q[226]
  PIN x_d_q[227]
    DIRECTION OUTPUT ;
    USE SIGNAL ;
    PORT
      LAYER M4 ;
        RECT  36.204 67.008 36.288 67.032 ;
    END
  END x_d_q[227]
  PIN x_d_q[228]
    DIRECTION OUTPUT ;
    USE SIGNAL ;
    PORT
      LAYER M4 ;
        RECT  36.204 67.248 36.288 67.272 ;
    END
  END x_d_q[228]
  PIN x_d_q[229]
    DIRECTION OUTPUT ;
    USE SIGNAL ;
    PORT
      LAYER M4 ;
        RECT  36.204 67.44 36.288 67.464 ;
    END
  END x_d_q[229]
  PIN x_d_q[22]
    DIRECTION OUTPUT ;
    USE SIGNAL ;
    PORT
      LAYER M4 ;
        RECT  36.204 14.16 36.288 14.184 ;
    END
  END x_d_q[22]
  PIN x_d_q[230]
    DIRECTION OUTPUT ;
    USE SIGNAL ;
    PORT
      LAYER M4 ;
        RECT  36.204 67.728 36.288 67.752 ;
    END
  END x_d_q[230]
  PIN x_d_q[231]
    DIRECTION OUTPUT ;
    USE SIGNAL ;
    PORT
      LAYER M4 ;
        RECT  36.204 67.92 36.288 67.944 ;
    END
  END x_d_q[231]
  PIN x_d_q[232]
    DIRECTION OUTPUT ;
    USE SIGNAL ;
    PORT
      LAYER M4 ;
        RECT  36.204 68.16 36.288 68.184 ;
    END
  END x_d_q[232]
  PIN x_d_q[233]
    DIRECTION OUTPUT ;
    USE SIGNAL ;
    PORT
      LAYER M4 ;
        RECT  36.204 68.4 36.288 68.424 ;
    END
  END x_d_q[233]
  PIN x_d_q[234]
    DIRECTION OUTPUT ;
    USE SIGNAL ;
    PORT
      LAYER M4 ;
        RECT  36.204 68.592 36.288 68.616 ;
    END
  END x_d_q[234]
  PIN x_d_q[235]
    DIRECTION OUTPUT ;
    USE SIGNAL ;
    PORT
      LAYER M4 ;
        RECT  36.204 68.88 36.288 68.904 ;
    END
  END x_d_q[235]
  PIN x_d_q[236]
    DIRECTION OUTPUT ;
    USE SIGNAL ;
    PORT
      LAYER M4 ;
        RECT  36.204 69.072 36.288 69.096 ;
    END
  END x_d_q[236]
  PIN x_d_q[237]
    DIRECTION OUTPUT ;
    USE SIGNAL ;
    PORT
      LAYER M4 ;
        RECT  36.204 69.312 36.288 69.336 ;
    END
  END x_d_q[237]
  PIN x_d_q[238]
    DIRECTION OUTPUT ;
    USE SIGNAL ;
    PORT
      LAYER M4 ;
        RECT  36.204 69.504 36.288 69.528 ;
    END
  END x_d_q[238]
  PIN x_d_q[239]
    DIRECTION OUTPUT ;
    USE SIGNAL ;
    PORT
      LAYER M4 ;
        RECT  36.204 69.744 36.288 69.768 ;
    END
  END x_d_q[239]
  PIN x_d_q[23]
    DIRECTION OUTPUT ;
    USE SIGNAL ;
    PORT
      LAYER M4 ;
        RECT  36.204 14.496 36.288 14.52 ;
    END
  END x_d_q[23]
  PIN x_d_q[240]
    DIRECTION OUTPUT ;
    USE SIGNAL ;
    PORT
      LAYER M4 ;
        RECT  36.204 69.936 36.288 69.96 ;
    END
  END x_d_q[240]
  PIN x_d_q[241]
    DIRECTION OUTPUT ;
    USE SIGNAL ;
    PORT
      LAYER M4 ;
        RECT  36.204 70.224 36.288 70.248 ;
    END
  END x_d_q[241]
  PIN x_d_q[242]
    DIRECTION OUTPUT ;
    USE SIGNAL ;
    PORT
      LAYER M4 ;
        RECT  36.204 70.416 36.288 70.44 ;
    END
  END x_d_q[242]
  PIN x_d_q[243]
    DIRECTION OUTPUT ;
    USE SIGNAL ;
    PORT
      LAYER M4 ;
        RECT  36.204 70.656 36.288 70.68 ;
    END
  END x_d_q[243]
  PIN x_d_q[244]
    DIRECTION OUTPUT ;
    USE SIGNAL ;
    PORT
      LAYER M4 ;
        RECT  36.204 70.848 36.288 70.872 ;
    END
  END x_d_q[244]
  PIN x_d_q[245]
    DIRECTION OUTPUT ;
    USE SIGNAL ;
    PORT
      LAYER M4 ;
        RECT  36.204 71.088 36.288 71.112 ;
    END
  END x_d_q[245]
  PIN x_d_q[246]
    DIRECTION OUTPUT ;
    USE SIGNAL ;
    PORT
      LAYER M4 ;
        RECT  36.204 71.376 36.288 71.4 ;
    END
  END x_d_q[246]
  PIN x_d_q[247]
    DIRECTION OUTPUT ;
    USE SIGNAL ;
    PORT
      LAYER M4 ;
        RECT  36.204 71.568 36.288 71.592 ;
    END
  END x_d_q[247]
  PIN x_d_q[248]
    DIRECTION OUTPUT ;
    USE SIGNAL ;
    PORT
      LAYER M4 ;
        RECT  36.204 71.808 36.288 71.832 ;
    END
  END x_d_q[248]
  PIN x_d_q[249]
    DIRECTION OUTPUT ;
    USE SIGNAL ;
    PORT
      LAYER M4 ;
        RECT  36.204 72 36.288 72.024 ;
    END
  END x_d_q[249]
  PIN x_d_q[24]
    DIRECTION OUTPUT ;
    USE SIGNAL ;
    PORT
      LAYER M4 ;
        RECT  36.204 14.832 36.288 14.856 ;
    END
  END x_d_q[24]
  PIN x_d_q[250]
    DIRECTION OUTPUT ;
    USE SIGNAL ;
    PORT
      LAYER M4 ;
        RECT  36.204 72.24 36.288 72.264 ;
    END
  END x_d_q[250]
  PIN x_d_q[251]
    DIRECTION OUTPUT ;
    USE SIGNAL ;
    PORT
      LAYER M4 ;
        RECT  36.204 72.432 36.288 72.456 ;
    END
  END x_d_q[251]
  PIN x_d_q[252]
    DIRECTION OUTPUT ;
    USE SIGNAL ;
    PORT
      LAYER M4 ;
        RECT  36.204 72.72 36.288 72.744 ;
    END
  END x_d_q[252]
  PIN x_d_q[253]
    DIRECTION OUTPUT ;
    USE SIGNAL ;
    PORT
      LAYER M4 ;
        RECT  36.204 72.912 36.288 72.936 ;
    END
  END x_d_q[253]
  PIN x_d_q[254]
    DIRECTION OUTPUT ;
    USE SIGNAL ;
    PORT
      LAYER M4 ;
        RECT  36.204 73.152 36.288 73.176 ;
    END
  END x_d_q[254]
  PIN x_d_q[255]
    DIRECTION OUTPUT ;
    USE SIGNAL ;
    PORT
      LAYER M4 ;
        RECT  36.204 73.344 36.288 73.368 ;
    END
  END x_d_q[255]
  PIN x_d_q[256]
    DIRECTION OUTPUT ;
    USE SIGNAL ;
    PORT
      LAYER M4 ;
        RECT  36.204 73.584 36.288 73.608 ;
    END
  END x_d_q[256]
  PIN x_d_q[257]
    DIRECTION OUTPUT ;
    USE SIGNAL ;
    PORT
      LAYER M4 ;
        RECT  36.204 73.824 36.288 73.848 ;
    END
  END x_d_q[257]
  PIN x_d_q[258]
    DIRECTION OUTPUT ;
    USE SIGNAL ;
    PORT
      LAYER M4 ;
        RECT  36.204 74.064 36.288 74.088 ;
    END
  END x_d_q[258]
  PIN x_d_q[259]
    DIRECTION OUTPUT ;
    USE SIGNAL ;
    PORT
      LAYER M4 ;
        RECT  36.204 74.304 36.288 74.328 ;
    END
  END x_d_q[259]
  PIN x_d_q[25]
    DIRECTION OUTPUT ;
    USE SIGNAL ;
    PORT
      LAYER M4 ;
        RECT  36.204 15.168 36.288 15.192 ;
    END
  END x_d_q[25]
  PIN x_d_q[260]
    DIRECTION OUTPUT ;
    USE SIGNAL ;
    PORT
      LAYER M4 ;
        RECT  36.204 74.496 36.288 74.52 ;
    END
  END x_d_q[260]
  PIN x_d_q[261]
    DIRECTION OUTPUT ;
    USE SIGNAL ;
    PORT
      LAYER M4 ;
        RECT  36.204 74.736 36.288 74.76 ;
    END
  END x_d_q[261]
  PIN x_d_q[262]
    DIRECTION OUTPUT ;
    USE SIGNAL ;
    PORT
      LAYER M4 ;
        RECT  36.204 74.976 36.288 75 ;
    END
  END x_d_q[262]
  PIN x_d_q[263]
    DIRECTION OUTPUT ;
    USE SIGNAL ;
    PORT
      LAYER M4 ;
        RECT  36.204 75.168 36.288 75.192 ;
    END
  END x_d_q[263]
  PIN x_d_q[264]
    DIRECTION OUTPUT ;
    USE SIGNAL ;
    PORT
      LAYER M4 ;
        RECT  36.204 75.408 36.288 75.432 ;
    END
  END x_d_q[264]
  PIN x_d_q[265]
    DIRECTION OUTPUT ;
    USE SIGNAL ;
    PORT
      LAYER M4 ;
        RECT  36.204 75.648 36.288 75.672 ;
    END
  END x_d_q[265]
  PIN x_d_q[266]
    DIRECTION OUTPUT ;
    USE SIGNAL ;
    PORT
      LAYER M4 ;
        RECT  36.204 75.888 36.288 75.912 ;
    END
  END x_d_q[266]
  PIN x_d_q[267]
    DIRECTION OUTPUT ;
    USE SIGNAL ;
    PORT
      LAYER M4 ;
        RECT  36.204 76.08 36.288 76.104 ;
    END
  END x_d_q[267]
  PIN x_d_q[268]
    DIRECTION OUTPUT ;
    USE SIGNAL ;
    PORT
      LAYER M4 ;
        RECT  36.204 76.32 36.288 76.344 ;
    END
  END x_d_q[268]
  PIN x_d_q[269]
    DIRECTION OUTPUT ;
    USE SIGNAL ;
    PORT
      LAYER M4 ;
        RECT  36.204 76.56 36.288 76.584 ;
    END
  END x_d_q[269]
  PIN x_d_q[26]
    DIRECTION OUTPUT ;
    USE SIGNAL ;
    PORT
      LAYER M4 ;
        RECT  36.204 15.504 36.288 15.528 ;
    END
  END x_d_q[26]
  PIN x_d_q[270]
    DIRECTION OUTPUT ;
    USE SIGNAL ;
    PORT
      LAYER M4 ;
        RECT  36.204 76.752 36.288 76.776 ;
    END
  END x_d_q[270]
  PIN x_d_q[271]
    DIRECTION OUTPUT ;
    USE SIGNAL ;
    PORT
      LAYER M4 ;
        RECT  36.204 76.992 36.288 77.016 ;
    END
  END x_d_q[271]
  PIN x_d_q[272]
    DIRECTION OUTPUT ;
    USE SIGNAL ;
    PORT
      LAYER M4 ;
        RECT  36.204 77.232 36.288 77.256 ;
    END
  END x_d_q[272]
  PIN x_d_q[273]
    DIRECTION OUTPUT ;
    USE SIGNAL ;
    PORT
      LAYER M4 ;
        RECT  36.204 77.472 36.288 77.496 ;
    END
  END x_d_q[273]
  PIN x_d_q[274]
    DIRECTION OUTPUT ;
    USE SIGNAL ;
    PORT
      LAYER M4 ;
        RECT  36.204 77.664 36.288 77.688 ;
    END
  END x_d_q[274]
  PIN x_d_q[275]
    DIRECTION OUTPUT ;
    USE SIGNAL ;
    PORT
      LAYER M4 ;
        RECT  36.204 77.904 36.288 77.928 ;
    END
  END x_d_q[275]
  PIN x_d_q[276]
    DIRECTION OUTPUT ;
    USE SIGNAL ;
    PORT
      LAYER M4 ;
        RECT  36.204 78.144 36.288 78.168 ;
    END
  END x_d_q[276]
  PIN x_d_q[277]
    DIRECTION OUTPUT ;
    USE SIGNAL ;
    PORT
      LAYER M4 ;
        RECT  36.204 78.336 36.288 78.36 ;
    END
  END x_d_q[277]
  PIN x_d_q[278]
    DIRECTION OUTPUT ;
    USE SIGNAL ;
    PORT
      LAYER M4 ;
        RECT  36.204 78.576 36.288 78.6 ;
    END
  END x_d_q[278]
  PIN x_d_q[279]
    DIRECTION OUTPUT ;
    USE SIGNAL ;
    PORT
      LAYER M4 ;
        RECT  36.204 78.816 36.288 78.84 ;
    END
  END x_d_q[279]
  PIN x_d_q[27]
    DIRECTION OUTPUT ;
    USE SIGNAL ;
    PORT
      LAYER M4 ;
        RECT  36.204 15.792 36.288 15.816 ;
    END
  END x_d_q[27]
  PIN x_d_q[280]
    DIRECTION OUTPUT ;
    USE SIGNAL ;
    PORT
      LAYER M4 ;
        RECT  36.204 79.056 36.288 79.08 ;
    END
  END x_d_q[280]
  PIN x_d_q[281]
    DIRECTION OUTPUT ;
    USE SIGNAL ;
    PORT
      LAYER M4 ;
        RECT  36.204 79.248 36.288 79.272 ;
    END
  END x_d_q[281]
  PIN x_d_q[282]
    DIRECTION OUTPUT ;
    USE SIGNAL ;
    PORT
      LAYER M4 ;
        RECT  36.204 79.488 36.288 79.512 ;
    END
  END x_d_q[282]
  PIN x_d_q[283]
    DIRECTION OUTPUT ;
    USE SIGNAL ;
    PORT
      LAYER M4 ;
        RECT  36.204 79.728 36.288 79.752 ;
    END
  END x_d_q[283]
  PIN x_d_q[284]
    DIRECTION OUTPUT ;
    USE SIGNAL ;
    PORT
      LAYER M4 ;
        RECT  36.204 79.968 36.288 79.992 ;
    END
  END x_d_q[284]
  PIN x_d_q[285]
    DIRECTION OUTPUT ;
    USE SIGNAL ;
    PORT
      LAYER M4 ;
        RECT  36.204 80.16 36.288 80.184 ;
    END
  END x_d_q[285]
  PIN x_d_q[286]
    DIRECTION OUTPUT ;
    USE SIGNAL ;
    PORT
      LAYER M4 ;
        RECT  36.204 80.4 36.288 80.424 ;
    END
  END x_d_q[286]
  PIN x_d_q[287]
    DIRECTION OUTPUT ;
    USE SIGNAL ;
    PORT
      LAYER M4 ;
        RECT  36.204 80.64 36.288 80.664 ;
    END
  END x_d_q[287]
  PIN x_d_q[288]
    DIRECTION OUTPUT ;
    USE SIGNAL ;
    PORT
      LAYER M4 ;
        RECT  36.204 80.832 36.288 80.856 ;
    END
  END x_d_q[288]
  PIN x_d_q[289]
    DIRECTION OUTPUT ;
    USE SIGNAL ;
    PORT
      LAYER M4 ;
        RECT  36.204 81.072 36.288 81.096 ;
    END
  END x_d_q[289]
  PIN x_d_q[28]
    DIRECTION OUTPUT ;
    USE SIGNAL ;
    PORT
      LAYER M4 ;
        RECT  36.204 16.128 36.288 16.152 ;
    END
  END x_d_q[28]
  PIN x_d_q[290]
    DIRECTION OUTPUT ;
    USE SIGNAL ;
    PORT
      LAYER M4 ;
        RECT  36.204 81.264 36.288 81.288 ;
    END
  END x_d_q[290]
  PIN x_d_q[291]
    DIRECTION OUTPUT ;
    USE SIGNAL ;
    PORT
      LAYER M4 ;
        RECT  36.204 81.552 36.288 81.576 ;
    END
  END x_d_q[291]
  PIN x_d_q[292]
    DIRECTION OUTPUT ;
    USE SIGNAL ;
    PORT
      LAYER M4 ;
        RECT  36.204 81.744 36.288 81.768 ;
    END
  END x_d_q[292]
  PIN x_d_q[293]
    DIRECTION OUTPUT ;
    USE SIGNAL ;
    PORT
      LAYER M4 ;
        RECT  36.204 81.984 36.288 82.008 ;
    END
  END x_d_q[293]
  PIN x_d_q[294]
    DIRECTION OUTPUT ;
    USE SIGNAL ;
    PORT
      LAYER M4 ;
        RECT  36.204 82.176 36.288 82.2 ;
    END
  END x_d_q[294]
  PIN x_d_q[295]
    DIRECTION OUTPUT ;
    USE SIGNAL ;
    PORT
      LAYER M4 ;
        RECT  36.204 82.416 36.288 82.44 ;
    END
  END x_d_q[295]
  PIN x_d_q[296]
    DIRECTION OUTPUT ;
    USE SIGNAL ;
    PORT
      LAYER M4 ;
        RECT  36.204 82.704 36.288 82.728 ;
    END
  END x_d_q[296]
  PIN x_d_q[297]
    DIRECTION OUTPUT ;
    USE SIGNAL ;
    PORT
      LAYER M4 ;
        RECT  36.204 82.896 36.288 82.92 ;
    END
  END x_d_q[297]
  PIN x_d_q[298]
    DIRECTION OUTPUT ;
    USE SIGNAL ;
    PORT
      LAYER M4 ;
        RECT  36.204 83.136 36.288 83.16 ;
    END
  END x_d_q[298]
  PIN x_d_q[299]
    DIRECTION OUTPUT ;
    USE SIGNAL ;
    PORT
      LAYER M4 ;
        RECT  36.204 83.328 36.288 83.352 ;
    END
  END x_d_q[299]
  PIN x_d_q[29]
    DIRECTION OUTPUT ;
    USE SIGNAL ;
    PORT
      LAYER M4 ;
        RECT  36.204 16.512 36.288 16.536 ;
    END
  END x_d_q[29]
  PIN x_d_q[2]
    DIRECTION OUTPUT ;
    USE SIGNAL ;
    PORT
      LAYER M4 ;
        RECT  36.204 7.488 36.288 7.512 ;
    END
  END x_d_q[2]
  PIN x_d_q[300]
    DIRECTION OUTPUT ;
    USE SIGNAL ;
    PORT
      LAYER M4 ;
        RECT  36.204 83.568 36.288 83.592 ;
    END
  END x_d_q[300]
  PIN x_d_q[301]
    DIRECTION OUTPUT ;
    USE SIGNAL ;
    PORT
      LAYER M4 ;
        RECT  36.204 83.76 36.288 83.784 ;
    END
  END x_d_q[301]
  PIN x_d_q[302]
    DIRECTION OUTPUT ;
    USE SIGNAL ;
    PORT
      LAYER M4 ;
        RECT  36.204 84.048 36.288 84.072 ;
    END
  END x_d_q[302]
  PIN x_d_q[303]
    DIRECTION OUTPUT ;
    USE SIGNAL ;
    PORT
      LAYER M4 ;
        RECT  36.204 84.24 36.288 84.264 ;
    END
  END x_d_q[303]
  PIN x_d_q[304]
    DIRECTION OUTPUT ;
    USE SIGNAL ;
    PORT
      LAYER M4 ;
        RECT  36.204 84.48 36.288 84.504 ;
    END
  END x_d_q[304]
  PIN x_d_q[305]
    DIRECTION OUTPUT ;
    USE SIGNAL ;
    PORT
      LAYER M4 ;
        RECT  36.204 84.672 36.288 84.696 ;
    END
  END x_d_q[305]
  PIN x_d_q[306]
    DIRECTION OUTPUT ;
    USE SIGNAL ;
    PORT
      LAYER M4 ;
        RECT  36.204 84.912 36.288 84.936 ;
    END
  END x_d_q[306]
  PIN x_d_q[307]
    DIRECTION OUTPUT ;
    USE SIGNAL ;
    PORT
      LAYER M4 ;
        RECT  36.204 85.2 36.288 85.224 ;
    END
  END x_d_q[307]
  PIN x_d_q[308]
    DIRECTION OUTPUT ;
    USE SIGNAL ;
    PORT
      LAYER M4 ;
        RECT  36.204 85.392 36.288 85.416 ;
    END
  END x_d_q[308]
  PIN x_d_q[309]
    DIRECTION OUTPUT ;
    USE SIGNAL ;
    PORT
      LAYER M4 ;
        RECT  36.204 85.632 36.288 85.656 ;
    END
  END x_d_q[309]
  PIN x_d_q[30]
    DIRECTION OUTPUT ;
    USE SIGNAL ;
    PORT
      LAYER M4 ;
        RECT  36.204 16.848 36.288 16.872 ;
    END
  END x_d_q[30]
  PIN x_d_q[310]
    DIRECTION OUTPUT ;
    USE SIGNAL ;
    PORT
      LAYER M4 ;
        RECT  36.204 85.824 36.288 85.848 ;
    END
  END x_d_q[310]
  PIN x_d_q[311]
    DIRECTION OUTPUT ;
    USE SIGNAL ;
    PORT
      LAYER M4 ;
        RECT  36.204 86.064 36.288 86.088 ;
    END
  END x_d_q[311]
  PIN x_d_q[312]
    DIRECTION OUTPUT ;
    USE SIGNAL ;
    PORT
      LAYER M4 ;
        RECT  36.204 86.256 36.288 86.28 ;
    END
  END x_d_q[312]
  PIN x_d_q[313]
    DIRECTION OUTPUT ;
    USE SIGNAL ;
    PORT
      LAYER M4 ;
        RECT  36.204 86.544 36.288 86.568 ;
    END
  END x_d_q[313]
  PIN x_d_q[314]
    DIRECTION OUTPUT ;
    USE SIGNAL ;
    PORT
      LAYER M4 ;
        RECT  36.204 86.736 36.288 86.76 ;
    END
  END x_d_q[314]
  PIN x_d_q[315]
    DIRECTION OUTPUT ;
    USE SIGNAL ;
    PORT
      LAYER M4 ;
        RECT  36.204 86.976 36.288 87 ;
    END
  END x_d_q[315]
  PIN x_d_q[316]
    DIRECTION OUTPUT ;
    USE SIGNAL ;
    PORT
      LAYER M4 ;
        RECT  36.204 87.168 36.288 87.192 ;
    END
  END x_d_q[316]
  PIN x_d_q[317]
    DIRECTION OUTPUT ;
    USE SIGNAL ;
    PORT
      LAYER M4 ;
        RECT  36.204 87.408 36.288 87.432 ;
    END
  END x_d_q[317]
  PIN x_d_q[318]
    DIRECTION OUTPUT ;
    USE SIGNAL ;
    PORT
      LAYER M4 ;
        RECT  36.204 87.6 36.288 87.624 ;
    END
  END x_d_q[318]
  PIN x_d_q[319]
    DIRECTION OUTPUT ;
    USE SIGNAL ;
    PORT
      LAYER M4 ;
        RECT  36.204 87.888 36.288 87.912 ;
    END
  END x_d_q[319]
  PIN x_d_q[31]
    DIRECTION OUTPUT ;
    USE SIGNAL ;
    PORT
      LAYER M4 ;
        RECT  36.204 17.136 36.288 17.16 ;
    END
  END x_d_q[31]
  PIN x_d_q[32]
    DIRECTION OUTPUT ;
    USE SIGNAL ;
    PORT
      LAYER M4 ;
        RECT  36.204 17.472 36.288 17.496 ;
    END
  END x_d_q[32]
  PIN x_d_q[33]
    DIRECTION OUTPUT ;
    USE SIGNAL ;
    PORT
      LAYER M4 ;
        RECT  36.204 17.808 36.288 17.832 ;
    END
  END x_d_q[33]
  PIN x_d_q[34]
    DIRECTION OUTPUT ;
    USE SIGNAL ;
    PORT
      LAYER M4 ;
        RECT  36.204 18.192 36.288 18.216 ;
    END
  END x_d_q[34]
  PIN x_d_q[35]
    DIRECTION OUTPUT ;
    USE SIGNAL ;
    PORT
      LAYER M4 ;
        RECT  36.204 18.48 36.288 18.504 ;
    END
  END x_d_q[35]
  PIN x_d_q[36]
    DIRECTION OUTPUT ;
    USE SIGNAL ;
    PORT
      LAYER M4 ;
        RECT  36.204 18.816 36.288 18.84 ;
    END
  END x_d_q[36]
  PIN x_d_q[37]
    DIRECTION OUTPUT ;
    USE SIGNAL ;
    PORT
      LAYER M4 ;
        RECT  36.204 19.152 36.288 19.176 ;
    END
  END x_d_q[37]
  PIN x_d_q[38]
    DIRECTION OUTPUT ;
    USE SIGNAL ;
    PORT
      LAYER M4 ;
        RECT  36.204 19.44 36.288 19.464 ;
    END
  END x_d_q[38]
  PIN x_d_q[39]
    DIRECTION OUTPUT ;
    USE SIGNAL ;
    PORT
      LAYER M4 ;
        RECT  36.204 19.824 36.288 19.848 ;
    END
  END x_d_q[39]
  PIN x_d_q[3]
    DIRECTION OUTPUT ;
    USE SIGNAL ;
    PORT
      LAYER M4 ;
        RECT  36.204 7.824 36.288 7.848 ;
    END
  END x_d_q[3]
  PIN x_d_q[40]
    DIRECTION OUTPUT ;
    USE SIGNAL ;
    PORT
      LAYER M4 ;
        RECT  36.204 20.16 36.288 20.184 ;
    END
  END x_d_q[40]
  PIN x_d_q[41]
    DIRECTION OUTPUT ;
    USE SIGNAL ;
    PORT
      LAYER M4 ;
        RECT  36.204 20.496 36.288 20.52 ;
    END
  END x_d_q[41]
  PIN x_d_q[42]
    DIRECTION OUTPUT ;
    USE SIGNAL ;
    PORT
      LAYER M4 ;
        RECT  36.204 20.784 36.288 20.808 ;
    END
  END x_d_q[42]
  PIN x_d_q[43]
    DIRECTION OUTPUT ;
    USE SIGNAL ;
    PORT
      LAYER M4 ;
        RECT  36.204 21.12 36.288 21.144 ;
    END
  END x_d_q[43]
  PIN x_d_q[44]
    DIRECTION OUTPUT ;
    USE SIGNAL ;
    PORT
      LAYER M4 ;
        RECT  36.204 21.504 36.288 21.528 ;
    END
  END x_d_q[44]
  PIN x_d_q[45]
    DIRECTION OUTPUT ;
    USE SIGNAL ;
    PORT
      LAYER M4 ;
        RECT  36.204 21.84 36.288 21.864 ;
    END
  END x_d_q[45]
  PIN x_d_q[46]
    DIRECTION OUTPUT ;
    USE SIGNAL ;
    PORT
      LAYER M4 ;
        RECT  36.204 22.128 36.288 22.152 ;
    END
  END x_d_q[46]
  PIN x_d_q[47]
    DIRECTION OUTPUT ;
    USE SIGNAL ;
    PORT
      LAYER M4 ;
        RECT  36.204 22.464 36.288 22.488 ;
    END
  END x_d_q[47]
  PIN x_d_q[48]
    DIRECTION OUTPUT ;
    USE SIGNAL ;
    PORT
      LAYER M4 ;
        RECT  36.204 22.848 36.288 22.872 ;
    END
  END x_d_q[48]
  PIN x_d_q[49]
    DIRECTION OUTPUT ;
    USE SIGNAL ;
    PORT
      LAYER M4 ;
        RECT  36.204 23.184 36.288 23.208 ;
    END
  END x_d_q[49]
  PIN x_d_q[4]
    DIRECTION OUTPUT ;
    USE SIGNAL ;
    PORT
      LAYER M4 ;
        RECT  36.204 8.16 36.288 8.184 ;
    END
  END x_d_q[4]
  PIN x_d_q[50]
    DIRECTION OUTPUT ;
    USE SIGNAL ;
    PORT
      LAYER M4 ;
        RECT  36.204 23.472 36.288 23.496 ;
    END
  END x_d_q[50]
  PIN x_d_q[51]
    DIRECTION OUTPUT ;
    USE SIGNAL ;
    PORT
      LAYER M4 ;
        RECT  36.204 23.808 36.288 23.832 ;
    END
  END x_d_q[51]
  PIN x_d_q[52]
    DIRECTION OUTPUT ;
    USE SIGNAL ;
    PORT
      LAYER M4 ;
        RECT  36.204 24.144 36.288 24.168 ;
    END
  END x_d_q[52]
  PIN x_d_q[53]
    DIRECTION OUTPUT ;
    USE SIGNAL ;
    PORT
      LAYER M4 ;
        RECT  36.204 24.528 36.288 24.552 ;
    END
  END x_d_q[53]
  PIN x_d_q[54]
    DIRECTION OUTPUT ;
    USE SIGNAL ;
    PORT
      LAYER M4 ;
        RECT  36.204 24.816 36.288 24.84 ;
    END
  END x_d_q[54]
  PIN x_d_q[55]
    DIRECTION OUTPUT ;
    USE SIGNAL ;
    PORT
      LAYER M4 ;
        RECT  36.204 25.152 36.288 25.176 ;
    END
  END x_d_q[55]
  PIN x_d_q[56]
    DIRECTION OUTPUT ;
    USE SIGNAL ;
    PORT
      LAYER M4 ;
        RECT  36.204 25.488 36.288 25.512 ;
    END
  END x_d_q[56]
  PIN x_d_q[57]
    DIRECTION OUTPUT ;
    USE SIGNAL ;
    PORT
      LAYER M4 ;
        RECT  36.204 25.824 36.288 25.848 ;
    END
  END x_d_q[57]
  PIN x_d_q[58]
    DIRECTION OUTPUT ;
    USE SIGNAL ;
    PORT
      LAYER M4 ;
        RECT  36.204 26.16 36.288 26.184 ;
    END
  END x_d_q[58]
  PIN x_d_q[59]
    DIRECTION OUTPUT ;
    USE SIGNAL ;
    PORT
      LAYER M4 ;
        RECT  36.204 26.496 36.288 26.52 ;
    END
  END x_d_q[59]
  PIN x_d_q[5]
    DIRECTION OUTPUT ;
    USE SIGNAL ;
    PORT
      LAYER M4 ;
        RECT  36.204 8.496 36.288 8.52 ;
    END
  END x_d_q[5]
  PIN x_d_q[60]
    DIRECTION OUTPUT ;
    USE SIGNAL ;
    PORT
      LAYER M4 ;
        RECT  36.204 26.832 36.288 26.856 ;
    END
  END x_d_q[60]
  PIN x_d_q[61]
    DIRECTION OUTPUT ;
    USE SIGNAL ;
    PORT
      LAYER M4 ;
        RECT  36.204 27.168 36.288 27.192 ;
    END
  END x_d_q[61]
  PIN x_d_q[62]
    DIRECTION OUTPUT ;
    USE SIGNAL ;
    PORT
      LAYER M4 ;
        RECT  36.204 27.504 36.288 27.528 ;
    END
  END x_d_q[62]
  PIN x_d_q[63]
    DIRECTION OUTPUT ;
    USE SIGNAL ;
    PORT
      LAYER M4 ;
        RECT  36.204 27.84 36.288 27.864 ;
    END
  END x_d_q[63]
  PIN x_d_q[64]
    DIRECTION OUTPUT ;
    USE SIGNAL ;
    PORT
      LAYER M4 ;
        RECT  36.204 30.096 36.288 30.12 ;
    END
  END x_d_q[64]
  PIN x_d_q[65]
    DIRECTION OUTPUT ;
    USE SIGNAL ;
    PORT
      LAYER M4 ;
        RECT  36.204 30.336 36.288 30.36 ;
    END
  END x_d_q[65]
  PIN x_d_q[66]
    DIRECTION OUTPUT ;
    USE SIGNAL ;
    PORT
      LAYER M4 ;
        RECT  36.204 30.576 36.288 30.6 ;
    END
  END x_d_q[66]
  PIN x_d_q[67]
    DIRECTION OUTPUT ;
    USE SIGNAL ;
    PORT
      LAYER M4 ;
        RECT  36.204 30.768 36.288 30.792 ;
    END
  END x_d_q[67]
  PIN x_d_q[68]
    DIRECTION OUTPUT ;
    USE SIGNAL ;
    PORT
      LAYER M4 ;
        RECT  36.204 31.008 36.288 31.032 ;
    END
  END x_d_q[68]
  PIN x_d_q[69]
    DIRECTION OUTPUT ;
    USE SIGNAL ;
    PORT
      LAYER M4 ;
        RECT  36.204 31.248 36.288 31.272 ;
    END
  END x_d_q[69]
  PIN x_d_q[6]
    DIRECTION OUTPUT ;
    USE SIGNAL ;
    PORT
      LAYER M4 ;
        RECT  36.204 8.832 36.288 8.856 ;
    END
  END x_d_q[6]
  PIN x_d_q[70]
    DIRECTION OUTPUT ;
    USE SIGNAL ;
    PORT
      LAYER M4 ;
        RECT  36.204 31.44 36.288 31.464 ;
    END
  END x_d_q[70]
  PIN x_d_q[71]
    DIRECTION OUTPUT ;
    USE SIGNAL ;
    PORT
      LAYER M4 ;
        RECT  36.204 31.68 36.288 31.704 ;
    END
  END x_d_q[71]
  PIN x_d_q[72]
    DIRECTION OUTPUT ;
    USE SIGNAL ;
    PORT
      LAYER M4 ;
        RECT  36.204 31.92 36.288 31.944 ;
    END
  END x_d_q[72]
  PIN x_d_q[73]
    DIRECTION OUTPUT ;
    USE SIGNAL ;
    PORT
      LAYER M4 ;
        RECT  36.204 32.16 36.288 32.184 ;
    END
  END x_d_q[73]
  PIN x_d_q[74]
    DIRECTION OUTPUT ;
    USE SIGNAL ;
    PORT
      LAYER M4 ;
        RECT  36.204 32.352 36.288 32.376 ;
    END
  END x_d_q[74]
  PIN x_d_q[75]
    DIRECTION OUTPUT ;
    USE SIGNAL ;
    PORT
      LAYER M4 ;
        RECT  36.204 32.592 36.288 32.616 ;
    END
  END x_d_q[75]
  PIN x_d_q[76]
    DIRECTION OUTPUT ;
    USE SIGNAL ;
    PORT
      LAYER M4 ;
        RECT  36.204 32.832 36.288 32.856 ;
    END
  END x_d_q[76]
  PIN x_d_q[77]
    DIRECTION OUTPUT ;
    USE SIGNAL ;
    PORT
      LAYER M4 ;
        RECT  36.204 33.024 36.288 33.048 ;
    END
  END x_d_q[77]
  PIN x_d_q[78]
    DIRECTION OUTPUT ;
    USE SIGNAL ;
    PORT
      LAYER M4 ;
        RECT  36.204 33.264 36.288 33.288 ;
    END
  END x_d_q[78]
  PIN x_d_q[79]
    DIRECTION OUTPUT ;
    USE SIGNAL ;
    PORT
      LAYER M4 ;
        RECT  36.204 33.504 36.288 33.528 ;
    END
  END x_d_q[79]
  PIN x_d_q[7]
    DIRECTION OUTPUT ;
    USE SIGNAL ;
    PORT
      LAYER M4 ;
        RECT  36.204 9.168 36.288 9.192 ;
    END
  END x_d_q[7]
  PIN x_d_q[80]
    DIRECTION OUTPUT ;
    USE SIGNAL ;
    PORT
      LAYER M4 ;
        RECT  36.204 33.744 36.288 33.768 ;
    END
  END x_d_q[80]
  PIN x_d_q[81]
    DIRECTION OUTPUT ;
    USE SIGNAL ;
    PORT
      LAYER M4 ;
        RECT  36.204 33.936 36.288 33.96 ;
    END
  END x_d_q[81]
  PIN x_d_q[82]
    DIRECTION OUTPUT ;
    USE SIGNAL ;
    PORT
      LAYER M4 ;
        RECT  36.204 34.176 36.288 34.2 ;
    END
  END x_d_q[82]
  PIN x_d_q[83]
    DIRECTION OUTPUT ;
    USE SIGNAL ;
    PORT
      LAYER M4 ;
        RECT  36.204 34.416 36.288 34.44 ;
    END
  END x_d_q[83]
  PIN x_d_q[84]
    DIRECTION OUTPUT ;
    USE SIGNAL ;
    PORT
      LAYER M4 ;
        RECT  36.204 34.656 36.288 34.68 ;
    END
  END x_d_q[84]
  PIN x_d_q[85]
    DIRECTION OUTPUT ;
    USE SIGNAL ;
    PORT
      LAYER M4 ;
        RECT  36.204 34.848 36.288 34.872 ;
    END
  END x_d_q[85]
  PIN x_d_q[86]
    DIRECTION OUTPUT ;
    USE SIGNAL ;
    PORT
      LAYER M4 ;
        RECT  36.204 35.088 36.288 35.112 ;
    END
  END x_d_q[86]
  PIN x_d_q[87]
    DIRECTION OUTPUT ;
    USE SIGNAL ;
    PORT
      LAYER M4 ;
        RECT  36.204 35.328 36.288 35.352 ;
    END
  END x_d_q[87]
  PIN x_d_q[88]
    DIRECTION OUTPUT ;
    USE SIGNAL ;
    PORT
      LAYER M4 ;
        RECT  36.204 35.52 36.288 35.544 ;
    END
  END x_d_q[88]
  PIN x_d_q[89]
    DIRECTION OUTPUT ;
    USE SIGNAL ;
    PORT
      LAYER M4 ;
        RECT  36.204 35.76 36.288 35.784 ;
    END
  END x_d_q[89]
  PIN x_d_q[8]
    DIRECTION OUTPUT ;
    USE SIGNAL ;
    PORT
      LAYER M4 ;
        RECT  36.204 9.504 36.288 9.528 ;
    END
  END x_d_q[8]
  PIN x_d_q[90]
    DIRECTION OUTPUT ;
    USE SIGNAL ;
    PORT
      LAYER M4 ;
        RECT  36.204 36 36.288 36.024 ;
    END
  END x_d_q[90]
  PIN x_d_q[91]
    DIRECTION OUTPUT ;
    USE SIGNAL ;
    PORT
      LAYER M4 ;
        RECT  36.204 36.24 36.288 36.264 ;
    END
  END x_d_q[91]
  PIN x_d_q[92]
    DIRECTION OUTPUT ;
    USE SIGNAL ;
    PORT
      LAYER M4 ;
        RECT  36.204 36.432 36.288 36.456 ;
    END
  END x_d_q[92]
  PIN x_d_q[93]
    DIRECTION OUTPUT ;
    USE SIGNAL ;
    PORT
      LAYER M4 ;
        RECT  36.204 36.672 36.288 36.696 ;
    END
  END x_d_q[93]
  PIN x_d_q[94]
    DIRECTION OUTPUT ;
    USE SIGNAL ;
    PORT
      LAYER M4 ;
        RECT  36.204 36.912 36.288 36.936 ;
    END
  END x_d_q[94]
  PIN x_d_q[95]
    DIRECTION OUTPUT ;
    USE SIGNAL ;
    PORT
      LAYER M4 ;
        RECT  36.204 37.104 36.288 37.128 ;
    END
  END x_d_q[95]
  PIN x_d_q[96]
    DIRECTION OUTPUT ;
    USE SIGNAL ;
    PORT
      LAYER M4 ;
        RECT  36.204 37.392 36.288 37.416 ;
    END
  END x_d_q[96]
  PIN x_d_q[97]
    DIRECTION OUTPUT ;
    USE SIGNAL ;
    PORT
      LAYER M4 ;
        RECT  36.204 37.584 36.288 37.608 ;
    END
  END x_d_q[97]
  PIN x_d_q[98]
    DIRECTION OUTPUT ;
    USE SIGNAL ;
    PORT
      LAYER M4 ;
        RECT  36.204 37.824 36.288 37.848 ;
    END
  END x_d_q[98]
  PIN x_d_q[99]
    DIRECTION OUTPUT ;
    USE SIGNAL ;
    PORT
      LAYER M4 ;
        RECT  36.204 38.016 36.288 38.04 ;
    END
  END x_d_q[99]
  PIN x_d_q[9]
    DIRECTION OUTPUT ;
    USE SIGNAL ;
    PORT
      LAYER M4 ;
        RECT  36.204 9.84 36.288 9.864 ;
    END
  END x_d_q[9]
  PIN x_oh[0]
    DIRECTION INPUT ;
    USE SIGNAL ;
    PORT
      LAYER M4 ;
        RECT  0 28.176 0.084 28.2 ;
    END
  END x_oh[0]
  PIN x_oh[1]
    DIRECTION INPUT ;
    USE SIGNAL ;
    PORT
      LAYER M4 ;
        RECT  0 28.512 0.084 28.536 ;
    END
  END x_oh[1]
  PIN x_oh[2]
    DIRECTION INPUT ;
    USE SIGNAL ;
    PORT
      LAYER M4 ;
        RECT  0 28.8 0.084 28.824 ;
    END
  END x_oh[2]
  PIN x_oh[3]
    DIRECTION INPUT ;
    USE SIGNAL ;
    PORT
      LAYER M4 ;
        RECT  0 29.136 0.084 29.16 ;
    END
  END x_oh[3]
  PIN x_oh[4]
    DIRECTION INPUT ;
    USE SIGNAL ;
    PORT
      LAYER M4 ;
        RECT  0 29.472 0.084 29.496 ;
    END
  END x_oh[4]
  PIN x_oh[5]
    DIRECTION INPUT ;
    USE SIGNAL ;
    PORT
      LAYER M4 ;
        RECT  0 29.808 0.084 29.832 ;
    END
  END x_oh[5]
  PIN x_oh_q[0]
    DIRECTION OUTPUT ;
    USE SIGNAL ;
    PORT
      LAYER M4 ;
        RECT  36.204 28.176 36.288 28.2 ;
    END
  END x_oh_q[0]
  PIN x_oh_q[1]
    DIRECTION OUTPUT ;
    USE SIGNAL ;
    PORT
      LAYER M4 ;
        RECT  36.204 28.512 36.288 28.536 ;
    END
  END x_oh_q[1]
  PIN x_oh_q[2]
    DIRECTION OUTPUT ;
    USE SIGNAL ;
    PORT
      LAYER M4 ;
        RECT  36.204 28.8 36.288 28.824 ;
    END
  END x_oh_q[2]
  PIN x_oh_q[3]
    DIRECTION OUTPUT ;
    USE SIGNAL ;
    PORT
      LAYER M4 ;
        RECT  36.204 29.136 36.288 29.16 ;
    END
  END x_oh_q[3]
  PIN x_oh_q[4]
    DIRECTION OUTPUT ;
    USE SIGNAL ;
    PORT
      LAYER M4 ;
        RECT  36.204 29.472 36.288 29.496 ;
    END
  END x_oh_q[4]
  PIN x_oh_q[5]
    DIRECTION OUTPUT ;
    USE SIGNAL ;
    PORT
      LAYER M4 ;
        RECT  36.204 29.808 36.288 29.832 ;
    END
  END x_oh_q[5]
  PIN VDD
    DIRECTION INOUT ;
    USE POWER ;
    PORT
      LAYER M5 ;
        RECT  29.592 2.151 29.712 86.409 ;
        RECT  24.192 2.151 24.312 86.409 ;
        RECT  18.792 2.151 18.912 86.409 ;
        RECT  13.392 2.151 13.512 86.409 ;
        RECT  7.992 2.151 8.112 86.409 ;
        RECT  2.592 2.151 2.712 86.409 ;
    END
  END VDD
  PIN VSS
    DIRECTION INOUT ;
    USE GROUND ;
    PORT
      LAYER M5 ;
        RECT  29.4 2.137 29.52 86.423 ;
        RECT  24 2.137 24.12 86.423 ;
        RECT  18.6 2.137 18.72 86.423 ;
        RECT  13.2 2.137 13.32 86.423 ;
        RECT  7.8 2.137 7.92 86.423 ;
        RECT  2.4 2.137 2.52 86.423 ;
    END
  END VSS
  # OT_OBS_CLOSED layer=M5 d_um=1.536 added=22
  OBS
    LAYER RVTN ;
     RECT  2.16 2.16 34.128 2.295 ;
     RECT  2.16 2.565 34.128 2.835 ;
     RECT  2.16 3.105 34.128 3.375 ;
     RECT  2.16 3.645 34.128 3.915 ;
     RECT  2.16 4.185 34.128 4.455 ;
     RECT  2.16 4.725 34.128 4.995 ;
     RECT  2.16 5.265 34.128 5.535 ;
     RECT  2.16 5.805 34.128 6.075 ;
     RECT  2.16 6.345 34.128 6.615 ;
     RECT  2.16 6.885 34.128 7.155 ;
     RECT  2.16 7.425 34.128 7.695 ;
     RECT  2.16 7.965 34.128 8.235 ;
     RECT  2.16 8.505 34.128 8.775 ;
     RECT  2.16 9.045 34.128 9.315 ;
     RECT  2.16 9.585 34.128 9.855 ;
     RECT  2.16 10.125 34.128 10.395 ;
     RECT  2.16 10.665 34.128 10.935 ;
     RECT  2.16 11.205 34.128 11.475 ;
     RECT  2.16 11.745 34.128 12.015 ;
     RECT  2.16 12.285 34.128 12.555 ;
     RECT  2.16 12.825 34.128 13.095 ;
     RECT  2.16 13.365 34.128 13.635 ;
     RECT  2.16 13.905 34.128 14.175 ;
     RECT  2.16 14.445 34.128 14.715 ;
     RECT  2.16 14.985 34.128 15.255 ;
     RECT  2.16 15.525 34.128 15.795 ;
     RECT  2.16 16.065 34.128 16.335 ;
     RECT  2.16 16.605 34.128 16.875 ;
     RECT  2.16 17.145 34.128 17.415 ;
     RECT  2.16 17.685 34.128 17.955 ;
     RECT  2.16 18.225 34.128 18.495 ;
     RECT  2.16 18.765 34.128 19.035 ;
     RECT  2.16 19.305 34.128 19.575 ;
     RECT  2.16 19.845 34.128 20.115 ;
     RECT  2.16 20.385 34.128 20.655 ;
     RECT  2.16 20.925 34.128 21.195 ;
     RECT  2.16 21.465 34.128 21.735 ;
     RECT  2.16 22.005 34.128 22.275 ;
     RECT  2.16 22.545 34.128 22.815 ;
     RECT  2.16 23.085 34.128 23.355 ;
     RECT  2.16 23.625 34.128 23.895 ;
     RECT  2.16 24.165 34.128 24.435 ;
     RECT  2.16 24.705 34.128 24.975 ;
     RECT  2.16 25.245 34.128 25.515 ;
     RECT  2.16 25.785 34.128 26.055 ;
     RECT  2.16 26.325 34.128 26.595 ;
     RECT  2.16 26.865 34.128 27.135 ;
     RECT  2.16 27.405 34.128 27.675 ;
     RECT  2.16 27.945 34.128 28.215 ;
     RECT  2.16 28.485 34.128 28.755 ;
     RECT  2.16 29.025 34.128 29.295 ;
     RECT  2.16 29.565 34.128 29.835 ;
     RECT  2.16 30.105 34.128 30.375 ;
     RECT  2.16 30.645 34.128 30.915 ;
     RECT  2.16 31.185 34.128 31.455 ;
     RECT  2.16 31.725 34.128 31.995 ;
     RECT  2.16 32.265 34.128 32.535 ;
     RECT  2.16 32.805 34.128 33.075 ;
     RECT  2.16 33.345 34.128 33.615 ;
     RECT  2.16 33.885 34.128 34.155 ;
     RECT  2.16 34.425 34.128 34.695 ;
     RECT  2.16 34.965 34.128 35.235 ;
     RECT  2.16 35.505 34.128 35.775 ;
     RECT  2.16 36.045 34.128 36.315 ;
     RECT  2.16 36.585 34.128 36.855 ;
     RECT  2.16 37.125 34.128 37.395 ;
     RECT  2.16 37.665 34.128 37.935 ;
     RECT  2.16 38.205 34.128 38.475 ;
     RECT  2.16 38.745 34.128 39.015 ;
     RECT  2.16 39.285 34.128 39.555 ;
     RECT  2.16 39.825 34.128 40.095 ;
     RECT  2.16 40.365 34.128 40.635 ;
     RECT  2.16 40.905 34.128 41.175 ;
     RECT  2.16 41.445 34.128 41.715 ;
     RECT  2.16 41.985 34.128 42.255 ;
     RECT  2.16 42.525 34.128 42.795 ;
     RECT  2.16 43.065 34.128 43.335 ;
     RECT  2.16 43.605 34.128 43.875 ;
     RECT  2.16 44.145 34.128 44.415 ;
     RECT  2.16 44.685 34.128 44.955 ;
     RECT  2.16 45.225 34.128 45.495 ;
     RECT  2.16 45.765 34.128 46.035 ;
     RECT  2.16 46.305 34.128 46.575 ;
     RECT  2.16 46.845 34.128 47.115 ;
     RECT  2.16 47.385 34.128 47.655 ;
     RECT  2.16 47.925 34.128 48.195 ;
     RECT  2.16 48.465 34.128 48.735 ;
     RECT  2.16 49.005 34.128 49.275 ;
     RECT  2.16 49.545 34.128 49.815 ;
     RECT  2.16 50.085 34.128 50.355 ;
     RECT  2.16 50.625 34.128 50.895 ;
     RECT  2.16 51.165 34.128 51.435 ;
     RECT  2.16 51.705 34.128 51.975 ;
     RECT  2.16 52.245 34.128 52.515 ;
     RECT  2.16 52.785 34.128 53.055 ;
     RECT  2.16 53.325 34.128 53.595 ;
     RECT  2.16 53.865 34.128 54.135 ;
     RECT  2.16 54.405 34.128 54.675 ;
     RECT  2.16 54.945 34.128 55.215 ;
     RECT  2.16 55.485 34.128 55.755 ;
     RECT  2.16 56.025 34.128 56.295 ;
     RECT  2.16 56.565 34.128 56.835 ;
     RECT  2.16 57.105 34.128 57.375 ;
     RECT  2.16 57.645 34.128 57.915 ;
     RECT  2.16 58.185 34.128 58.455 ;
     RECT  2.16 58.725 34.128 58.995 ;
     RECT  2.16 59.265 34.128 59.535 ;
     RECT  2.16 59.805 34.128 60.075 ;
     RECT  2.16 60.345 34.128 60.615 ;
     RECT  2.16 60.885 34.128 61.155 ;
     RECT  2.16 61.425 34.128 61.695 ;
     RECT  2.16 61.965 34.128 62.235 ;
     RECT  2.16 62.505 34.128 62.775 ;
     RECT  2.16 63.045 34.128 63.315 ;
     RECT  2.16 63.585 34.128 63.855 ;
     RECT  2.16 64.125 34.128 64.395 ;
     RECT  2.16 64.665 34.128 64.935 ;
     RECT  2.16 65.205 34.128 65.475 ;
     RECT  2.16 65.745 34.128 66.015 ;
     RECT  2.16 66.285 34.128 66.555 ;
     RECT  2.16 66.825 34.128 67.095 ;
     RECT  2.16 67.365 34.128 67.635 ;
     RECT  2.16 67.905 34.128 68.175 ;
     RECT  2.16 68.445 34.128 68.715 ;
     RECT  2.16 68.985 34.128 69.255 ;
     RECT  2.16 69.525 34.128 69.795 ;
     RECT  2.16 70.065 34.128 70.335 ;
     RECT  2.16 70.605 34.128 70.875 ;
     RECT  2.16 71.145 34.128 71.415 ;
     RECT  2.16 71.685 34.128 71.955 ;
     RECT  2.16 72.225 34.128 72.495 ;
     RECT  2.16 72.765 34.128 73.035 ;
     RECT  2.16 73.305 34.128 73.575 ;
     RECT  2.16 73.845 34.128 74.115 ;
     RECT  2.16 74.385 34.128 74.655 ;
     RECT  2.16 74.925 34.128 75.195 ;
     RECT  2.16 75.465 34.128 75.735 ;
     RECT  2.16 76.005 34.128 76.275 ;
     RECT  2.16 76.545 34.128 76.815 ;
     RECT  2.16 77.085 34.128 77.355 ;
     RECT  2.16 77.625 34.128 77.895 ;
     RECT  2.16 78.165 34.128 78.435 ;
     RECT  2.16 78.705 34.128 78.975 ;
     RECT  2.16 79.245 34.128 79.515 ;
     RECT  2.16 79.785 34.128 80.055 ;
     RECT  2.16 80.325 34.128 80.595 ;
     RECT  2.16 80.865 34.128 81.135 ;
     RECT  2.16 81.405 34.128 81.675 ;
     RECT  2.16 81.945 34.128 82.215 ;
     RECT  2.16 82.485 34.128 82.755 ;
     RECT  2.16 83.025 34.128 83.295 ;
     RECT  2.16 83.565 34.128 83.835 ;
     RECT  2.16 84.105 34.128 84.375 ;
     RECT  2.16 84.645 34.128 84.915 ;
     RECT  2.16 85.185 34.128 85.455 ;
     RECT  2.16 85.725 34.128 85.995 ;
     RECT  2.16 86.265 34.128 86.4 ;
    LAYER RVTP ;
     RECT  2.16 2.295 34.128 2.565 ;
     RECT  2.16 2.835 34.128 3.105 ;
     RECT  2.16 3.375 34.128 3.645 ;
     RECT  2.16 3.915 34.128 4.185 ;
     RECT  2.16 4.455 34.128 4.725 ;
     RECT  2.16 4.995 34.128 5.265 ;
     RECT  2.16 5.535 34.128 5.805 ;
     RECT  2.16 6.075 34.128 6.345 ;
     RECT  2.16 6.615 34.128 6.885 ;
     RECT  2.16 7.155 34.128 7.425 ;
     RECT  2.16 7.695 34.128 7.965 ;
     RECT  2.16 8.235 34.128 8.505 ;
     RECT  2.16 8.775 34.128 9.045 ;
     RECT  2.16 9.315 34.128 9.585 ;
     RECT  2.16 9.855 34.128 10.125 ;
     RECT  2.16 10.395 34.128 10.665 ;
     RECT  2.16 10.935 34.128 11.205 ;
     RECT  2.16 11.475 34.128 11.745 ;
     RECT  2.16 12.015 34.128 12.285 ;
     RECT  2.16 12.555 34.128 12.825 ;
     RECT  2.16 13.095 34.128 13.365 ;
     RECT  2.16 13.635 34.128 13.905 ;
     RECT  2.16 14.175 34.128 14.445 ;
     RECT  2.16 14.715 34.128 14.985 ;
     RECT  2.16 15.255 34.128 15.525 ;
     RECT  2.16 15.795 34.128 16.065 ;
     RECT  2.16 16.335 34.128 16.605 ;
     RECT  2.16 16.875 34.128 17.145 ;
     RECT  2.16 17.415 34.128 17.685 ;
     RECT  2.16 17.955 34.128 18.225 ;
     RECT  2.16 18.495 34.128 18.765 ;
     RECT  2.16 19.035 34.128 19.305 ;
     RECT  2.16 19.575 34.128 19.845 ;
     RECT  2.16 20.115 34.128 20.385 ;
     RECT  2.16 20.655 34.128 20.925 ;
     RECT  2.16 21.195 34.128 21.465 ;
     RECT  2.16 21.735 34.128 22.005 ;
     RECT  2.16 22.275 34.128 22.545 ;
     RECT  2.16 22.815 34.128 23.085 ;
     RECT  2.16 23.355 34.128 23.625 ;
     RECT  2.16 23.895 34.128 24.165 ;
     RECT  2.16 24.435 34.128 24.705 ;
     RECT  2.16 24.975 34.128 25.245 ;
     RECT  2.16 25.515 34.128 25.785 ;
     RECT  2.16 26.055 34.128 26.325 ;
     RECT  2.16 26.595 34.128 26.865 ;
     RECT  2.16 27.135 34.128 27.405 ;
     RECT  2.16 27.675 34.128 27.945 ;
     RECT  2.16 28.215 34.128 28.485 ;
     RECT  2.16 28.755 34.128 29.025 ;
     RECT  2.16 29.295 34.128 29.565 ;
     RECT  2.16 29.835 34.128 30.105 ;
     RECT  2.16 30.375 34.128 30.645 ;
     RECT  2.16 30.915 34.128 31.185 ;
     RECT  2.16 31.455 34.128 31.725 ;
     RECT  2.16 31.995 34.128 32.265 ;
     RECT  2.16 32.535 34.128 32.805 ;
     RECT  2.16 33.075 34.128 33.345 ;
     RECT  2.16 33.615 34.128 33.885 ;
     RECT  2.16 34.155 34.128 34.425 ;
     RECT  2.16 34.695 34.128 34.965 ;
     RECT  2.16 35.235 34.128 35.505 ;
     RECT  2.16 35.775 34.128 36.045 ;
     RECT  2.16 36.315 34.128 36.585 ;
     RECT  2.16 36.855 34.128 37.125 ;
     RECT  2.16 37.395 34.128 37.665 ;
     RECT  2.16 37.935 34.128 38.205 ;
     RECT  2.16 38.475 34.128 38.745 ;
     RECT  2.16 39.015 34.128 39.285 ;
     RECT  2.16 39.555 34.128 39.825 ;
     RECT  2.16 40.095 34.128 40.365 ;
     RECT  2.16 40.635 34.128 40.905 ;
     RECT  2.16 41.175 34.128 41.445 ;
     RECT  2.16 41.715 34.128 41.985 ;
     RECT  2.16 42.255 34.128 42.525 ;
     RECT  2.16 42.795 34.128 43.065 ;
     RECT  2.16 43.335 34.128 43.605 ;
     RECT  2.16 43.875 34.128 44.145 ;
     RECT  2.16 44.415 34.128 44.685 ;
     RECT  2.16 44.955 34.128 45.225 ;
     RECT  2.16 45.495 34.128 45.765 ;
     RECT  2.16 46.035 34.128 46.305 ;
     RECT  2.16 46.575 34.128 46.845 ;
     RECT  2.16 47.115 34.128 47.385 ;
     RECT  2.16 47.655 34.128 47.925 ;
     RECT  2.16 48.195 34.128 48.465 ;
     RECT  2.16 48.735 34.128 49.005 ;
     RECT  2.16 49.275 34.128 49.545 ;
     RECT  2.16 49.815 34.128 50.085 ;
     RECT  2.16 50.355 34.128 50.625 ;
     RECT  2.16 50.895 34.128 51.165 ;
     RECT  2.16 51.435 34.128 51.705 ;
     RECT  2.16 51.975 34.128 52.245 ;
     RECT  2.16 52.515 34.128 52.785 ;
     RECT  2.16 53.055 34.128 53.325 ;
     RECT  2.16 53.595 34.128 53.865 ;
     RECT  2.16 54.135 34.128 54.405 ;
     RECT  2.16 54.675 34.128 54.945 ;
     RECT  2.16 55.215 34.128 55.485 ;
     RECT  2.16 55.755 34.128 56.025 ;
     RECT  2.16 56.295 34.128 56.565 ;
     RECT  2.16 56.835 34.128 57.105 ;
     RECT  2.16 57.375 34.128 57.645 ;
     RECT  2.16 57.915 34.128 58.185 ;
     RECT  2.16 58.455 34.128 58.725 ;
     RECT  2.16 58.995 34.128 59.265 ;
     RECT  2.16 59.535 34.128 59.805 ;
     RECT  2.16 60.075 34.128 60.345 ;
     RECT  2.16 60.615 34.128 60.885 ;
     RECT  2.16 61.155 34.128 61.425 ;
     RECT  2.16 61.695 34.128 61.965 ;
     RECT  2.16 62.235 34.128 62.505 ;
     RECT  2.16 62.775 34.128 63.045 ;
     RECT  2.16 63.315 34.128 63.585 ;
     RECT  2.16 63.855 34.128 64.125 ;
     RECT  2.16 64.395 34.128 64.665 ;
     RECT  2.16 64.935 34.128 65.205 ;
     RECT  2.16 65.475 34.128 65.745 ;
     RECT  2.16 66.015 34.128 66.285 ;
     RECT  2.16 66.555 34.128 66.825 ;
     RECT  2.16 67.095 34.128 67.365 ;
     RECT  2.16 67.635 34.128 67.905 ;
     RECT  2.16 68.175 34.128 68.445 ;
     RECT  2.16 68.715 34.128 68.985 ;
     RECT  2.16 69.255 34.128 69.525 ;
     RECT  2.16 69.795 34.128 70.065 ;
     RECT  2.16 70.335 34.128 70.605 ;
     RECT  2.16 70.875 34.128 71.145 ;
     RECT  2.16 71.415 34.128 71.685 ;
     RECT  2.16 71.955 34.128 72.225 ;
     RECT  2.16 72.495 34.128 72.765 ;
     RECT  2.16 73.035 34.128 73.305 ;
     RECT  2.16 73.575 34.128 73.845 ;
     RECT  2.16 74.115 34.128 74.385 ;
     RECT  2.16 74.655 34.128 74.925 ;
     RECT  2.16 75.195 34.128 75.465 ;
     RECT  2.16 75.735 34.128 76.005 ;
     RECT  2.16 76.275 34.128 76.545 ;
     RECT  2.16 76.815 34.128 77.085 ;
     RECT  2.16 77.355 34.128 77.625 ;
     RECT  2.16 77.895 34.128 78.165 ;
     RECT  2.16 78.435 34.128 78.705 ;
     RECT  2.16 78.975 34.128 79.245 ;
     RECT  2.16 79.515 34.128 79.785 ;
     RECT  2.16 80.055 34.128 80.325 ;
     RECT  2.16 80.595 34.128 80.865 ;
     RECT  2.16 81.135 34.128 81.405 ;
     RECT  2.16 81.675 34.128 81.945 ;
     RECT  2.16 82.215 34.128 82.485 ;
     RECT  2.16 82.755 34.128 83.025 ;
     RECT  2.16 83.295 34.128 83.565 ;
     RECT  2.16 83.835 34.128 84.105 ;
     RECT  2.16 84.375 34.128 84.645 ;
     RECT  2.16 84.915 34.128 85.185 ;
     RECT  2.16 85.455 34.128 85.725 ;
     RECT  2.16 85.995 34.128 86.265 ;
    LAYER M1 ;
     RECT  2.16 2.151 34.128 86.409 ;
    LAYER M2 ;
     RECT  0.103 83.07 0.499 83.088 ;
     RECT  0.103 63.828 0.535 63.846 ;
     RECT  0.103 74.052 0.535 74.07 ;
     RECT  0.499 83.07 0.535 83.556 ;
     RECT  0.535 83.07 0.571 83.79 ;
     RECT  0.571 83.07 1.147 84.06 ;
     RECT  0.103 85.122 1.219 85.14 ;
     RECT  2.047 2.106 2.119 2.124 ;
     RECT  2.119 2.106 2.16 2.484 ;
     RECT  0.103 4.5 2.16 4.518 ;
     RECT  0.103 11.952 2.16 11.97 ;
     RECT  0.103 17.658 2.16 17.676 ;
     RECT  0.103 19.35 2.16 19.368 ;
     RECT  0.103 23.292 2.16 23.31 ;
     RECT  0.103 25.02 2.16 25.038 ;
     RECT  0.535 33.588 2.16 33.606 ;
     RECT  0.103 42.732 2.16 42.75 ;
     RECT  0.535 45.234 2.16 45.252 ;
     RECT  0.103 48.978 2.16 48.996 ;
     RECT  0.103 50.832 2.16 50.85 ;
     RECT  0.535 54.072 2.16 54.09 ;
     RECT  0.103 56.808 2.16 56.826 ;
     RECT  0.535 58.122 2.16 58.14 ;
     RECT  0.535 63.126 2.16 63.846 ;
     RECT  0.103 64.872 2.16 64.89 ;
     RECT  0.139 67.14 2.16 67.158 ;
     RECT  0.103 72.27 2.16 72.288 ;
     RECT  0.535 73.512 2.16 74.07 ;
     RECT  0.103 78.912 2.16 78.93 ;
     RECT  0.103 79.722 2.16 79.74 ;
     RECT  0.535 81.756 2.16 81.774 ;
     RECT  1.147 83.07 2.16 84.366 ;
     RECT  1.219 85.122 2.16 85.788 ;
     RECT  2.16 2.106 2.399 86.409 ;
     RECT  2.399 2.151 16.123 86.409 ;
     RECT  16.123 2.106 17.015 86.409 ;
     RECT  17.015 2.151 32.251 86.409 ;
     RECT  32.251 2.106 33.115 86.409 ;
     RECT  33.115 2.106 33.215 86.634 ;
     RECT  33.215 2.106 33.503 86.409 ;
     RECT  33.503 2.151 34.128 86.409 ;
     RECT  34.128 22.626 34.223 78.084 ;
     RECT  34.128 4.896 34.763 8.424 ;
     RECT  34.128 12.186 34.763 21.654 ;
     RECT  34.223 22.788 34.763 65.394 ;
     RECT  34.128 78.876 34.763 83.79 ;
     RECT  34.763 4.896 34.799 5.904 ;
     RECT  34.763 15.156 34.799 21.654 ;
     RECT  34.763 25.326 34.799 36.774 ;
     RECT  34.763 37.566 34.799 50.274 ;
     RECT  34.763 51.066 34.799 65.394 ;
     RECT  34.223 66.456 34.799 74.07 ;
     RECT  34.223 74.826 34.799 78.084 ;
     RECT  34.763 79.218 34.799 83.79 ;
     RECT  34.128 84.726 34.799 85.644 ;
     RECT  34.799 66.456 34.835 68.976 ;
     RECT  34.799 56.736 34.943 65.394 ;
     RECT  34.128 9.396 35.303 11.394 ;
     RECT  34.763 22.788 35.303 24.354 ;
     RECT  34.799 25.866 35.303 36.774 ;
     RECT  34.835 66.456 35.303 68.904 ;
     RECT  34.799 4.896 35.339 4.986 ;
     RECT  34.799 5.886 35.339 5.904 ;
     RECT  34.763 6.822 35.339 8.424 ;
     RECT  35.303 9.396 35.339 11.124 ;
     RECT  34.763 12.186 35.339 14.364 ;
     RECT  34.799 15.966 35.339 19.494 ;
     RECT  34.799 20.286 35.339 21.654 ;
     RECT  35.303 22.986 35.339 24.354 ;
     RECT  35.303 25.956 35.339 36.774 ;
     RECT  34.799 37.566 35.339 38.934 ;
     RECT  34.799 39.87 35.339 44.064 ;
     RECT  34.799 45.126 35.339 50.04 ;
     RECT  34.799 51.066 35.339 55.404 ;
     RECT  34.943 56.736 35.339 58.374 ;
     RECT  34.943 59.166 35.339 65.394 ;
     RECT  35.303 66.456 35.339 66.474 ;
     RECT  35.303 67.266 35.339 68.904 ;
     RECT  34.799 70.236 35.339 73.674 ;
     RECT  34.799 74.826 35.339 74.844 ;
     RECT  34.799 75.636 35.339 78.084 ;
     RECT  34.799 79.218 35.339 80.784 ;
     RECT  34.799 81.72 35.339 82.044 ;
     RECT  34.128 3.96 35.375 3.978 ;
     RECT  35.339 4.968 35.375 4.986 ;
     RECT  35.339 7.236 35.375 7.254 ;
     RECT  35.339 8.406 35.375 8.424 ;
     RECT  35.339 21.276 35.375 21.564 ;
     RECT  35.339 24.246 35.375 24.264 ;
     RECT  35.339 28.386 35.375 29.484 ;
     RECT  35.339 31.896 35.375 32.49 ;
     RECT  35.339 36.666 35.375 36.684 ;
     RECT  35.339 38.178 35.375 38.196 ;
     RECT  35.339 39.87 35.375 40.464 ;
     RECT  35.339 46.656 35.375 47.214 ;
     RECT  35.339 54.108 35.375 54.126 ;
     RECT  35.339 58.122 35.375 58.14 ;
     RECT  35.339 64.368 35.375 65.304 ;
     RECT  35.339 67.806 35.375 68.4 ;
     RECT  35.339 76.284 35.375 76.302 ;
     RECT  35.339 77.436 35.375 78.084 ;
     RECT  35.339 79.218 35.375 79.236 ;
     RECT  35.339 80.334 35.375 80.514 ;
     RECT  34.799 82.836 35.375 83.79 ;
     RECT  35.375 21.276 35.411 21.294 ;
     RECT  35.375 64.566 35.411 64.584 ;
     RECT  35.375 83.736 35.411 83.79 ;
     RECT  34.799 84.726 35.447 85.482 ;
     RECT  35.411 83.772 35.483 83.79 ;
     RECT  35.339 26.676 36.203 26.694 ;
     RECT  35.339 62.676 36.203 62.694 ;
     RECT  35.375 82.836 36.203 82.854 ;
    LAYER M3 ;
     RECT  33.012 0.091 33.03 0.571 ;
     RECT  33.012 0.571 33.498 1.723 ;
     RECT  2.052 1.723 2.07 1.771 ;
     RECT  2.052 1.771 2.142 2.101 ;
     RECT  16.02 1.723 16.47 2.101 ;
     RECT  32.544 1.723 33.498 2.101 ;
     RECT  2.052 2.101 2.394 2.129 ;
     RECT  2.124 2.129 2.394 2.143 ;
     RECT  32.256 2.101 33.498 2.155 ;
     RECT  16.02 2.101 17.01 2.227 ;
     RECT  24.015 2.143 24.105 2.227 ;
     RECT  12.132 1.723 12.15 2.255 ;
     RECT  16.02 2.227 17.298 2.263 ;
     RECT  23.904 2.227 24.105 2.285 ;
     RECT  2.124 2.143 2.505 2.413 ;
     RECT  7.815 2.143 7.905 2.413 ;
     RECT  13.215 2.143 13.305 2.413 ;
     RECT  18.615 2.143 18.705 2.413 ;
     RECT  24.015 2.285 24.105 2.413 ;
     RECT  29.415 2.143 29.505 2.413 ;
     RECT  15.876 2.263 17.298 2.461 ;
     RECT  18.615 2.413 18.897 2.461 ;
     RECT  31.392 2.191 31.41 2.461 ;
     RECT  2.124 2.413 2.697 2.489 ;
     RECT  32.256 2.155 33.714 2.533 ;
     RECT  2.304 2.489 2.697 2.605 ;
     RECT  13.215 2.413 13.497 2.605 ;
     RECT  30.78 2.461 31.41 2.633 ;
     RECT  3.96 2.461 3.978 2.641 ;
     RECT  12.204 2.371 12.258 2.641 ;
     RECT  13.215 2.605 13.77 2.641 ;
     RECT  2.304 2.605 2.754 2.831 ;
     RECT  12.204 2.641 12.33 2.831 ;
     RECT  3.6 2.641 3.978 2.839 ;
     RECT  13.215 2.641 13.986 2.875 ;
     RECT  15.048 2.839 15.066 2.875 ;
     RECT  15.876 2.461 18.897 2.875 ;
     RECT  32.184 2.533 33.714 2.911 ;
     RECT  12.204 2.831 12.258 3.029 ;
     RECT  12.24 3.029 12.258 3.101 ;
     RECT  2.34 2.831 2.754 3.181 ;
     RECT  3.528 2.839 3.978 3.181 ;
     RECT  31.464 2.911 33.714 3.181 ;
     RECT  2.34 3.181 3.978 3.379 ;
     RECT  2.34 3.379 4.554 3.437 ;
     RECT  31.464 3.181 34.002 3.605 ;
     RECT  2.376 3.437 4.554 3.641 ;
     RECT  2.415 3.641 4.554 3.649 ;
     RECT  10.944 3.181 10.962 3.649 ;
     RECT  10.944 3.649 10.998 3.685 ;
     RECT  10.908 3.685 10.998 3.721 ;
     RECT  13.215 2.875 18.954 3.721 ;
     RECT  10.836 3.721 10.998 3.811 ;
     RECT  2.415 3.649 4.986 3.839 ;
     RECT  10.764 3.811 10.998 3.839 ;
     RECT  9.288 3.721 9.306 3.911 ;
     RECT  4.536 3.839 4.554 3.947 ;
     RECT  10.764 3.839 10.962 3.947 ;
     RECT  10.836 3.947 10.962 3.983 ;
     RECT  13.032 3.721 18.99 3.991 ;
     RECT  20.628 3.721 20.646 4.157 ;
     RECT  13.032 3.991 19.134 4.181 ;
     RECT  14.328 4.181 19.134 4.189 ;
     RECT  31.824 3.605 34.002 4.205 ;
     RECT  22.788 4.117 22.806 4.217 ;
     RECT  30.78 3.847 30.798 4.217 ;
     RECT  31.824 4.205 33.57 4.379 ;
     RECT  13.032 4.181 13.497 4.451 ;
     RECT  31.824 4.379 32.562 4.451 ;
     RECT  32.436 4.451 32.562 4.487 ;
     RECT  32.544 4.487 32.562 4.523 ;
     RECT  14.328 4.189 19.386 4.559 ;
     RECT  2.415 3.839 3.726 4.621 ;
     RECT  14.832 4.559 19.386 4.649 ;
     RECT  14.832 4.649 19.134 4.691 ;
     RECT  15.12 4.691 19.134 4.721 ;
     RECT  5.976 4.621 5.994 4.765 ;
     RECT  6.984 4.729 7.002 4.765 ;
     RECT  35.352 3.955 35.37 4.795 ;
     RECT  2.415 4.621 4.41 4.801 ;
     RECT  0.108 4.495 0.126 4.829 ;
     RECT  15.804 4.721 19.134 4.835 ;
     RECT  17.1 4.835 19.134 4.877 ;
     RECT  10.908 4.801 10.926 4.891 ;
     RECT  10.836 4.891 10.926 4.919 ;
     RECT  15.804 4.835 16.362 4.919 ;
     RECT  17.1 4.877 17.478 4.955 ;
     RECT  17.172 4.955 17.478 4.973 ;
     RECT  10.836 4.919 10.854 4.991 ;
     RECT  17.172 4.973 17.298 5.027 ;
     RECT  33.444 4.379 33.57 5.035 ;
     RECT  18.216 4.877 19.134 5.063 ;
     RECT  5.76 4.765 7.002 5.099 ;
     RECT  15.804 4.919 16.326 5.099 ;
     RECT  2.415 4.801 4.59 5.131 ;
     RECT  33.444 5.035 33.822 5.161 ;
     RECT  35.316 4.795 35.37 5.165 ;
     RECT  2.304 5.131 4.59 5.189 ;
     RECT  5.76 5.099 6.246 5.189 ;
     RECT  16.092 5.099 16.326 5.189 ;
     RECT  2.304 5.189 3.222 5.225 ;
     RECT  16.092 5.189 16.11 5.225 ;
     RECT  18.615 5.063 19.134 5.225 ;
     RECT  5.76 5.189 6.102 5.341 ;
     RECT  5.472 5.341 6.102 5.459 ;
     RECT  17.208 5.027 17.298 5.459 ;
     RECT  35.316 5.165 35.334 5.461 ;
     RECT  7.815 2.413 8.097 5.467 ;
     RECT  5.76 5.459 6.102 5.495 ;
     RECT  34.776 5.461 35.334 5.501 ;
     RECT  2.34 5.225 2.97 5.504 ;
     RECT  7.272 5.467 8.097 5.563 ;
     RECT  8.82 3.991 8.838 5.563 ;
     RECT  7.272 5.563 8.838 5.603 ;
     RECT  4.104 5.189 4.59 5.611 ;
     RECT  33.336 5.161 33.822 5.701 ;
     RECT  4.104 5.611 4.698 5.729 ;
     RECT  17.28 5.459 17.298 5.729 ;
     RECT  4.104 5.729 4.59 5.765 ;
     RECT  33.336 5.701 34.218 5.845 ;
     RECT  35.316 5.501 35.334 5.909 ;
     RECT  33.264 5.845 34.218 5.971 ;
     RECT  2.415 5.504 2.97 6.043 ;
     RECT  32.796 5.971 34.218 6.071 ;
     RECT  2.415 6.043 3.078 6.151 ;
     RECT  0.108 6.043 0.126 6.173 ;
     RECT  34.2 6.071 34.218 6.173 ;
     RECT  5.76 5.495 5.886 6.241 ;
     RECT  2.415 6.151 3.402 6.269 ;
     RECT  7.272 5.603 8.097 6.305 ;
     RECT  2.415 6.269 3.222 6.385 ;
     RECT  2.304 6.385 3.222 6.509 ;
     RECT  33.264 6.071 33.354 6.539 ;
     RECT  5.76 6.241 5.958 6.547 ;
     RECT  4.32 5.765 4.59 6.575 ;
     RECT  5.76 6.547 5.994 6.575 ;
     RECT  5.94 6.575 5.994 6.691 ;
     RECT  5.94 6.691 6.138 6.719 ;
     RECT  34.74 6.475 34.758 6.808 ;
     RECT  2.415 6.509 3.222 6.845 ;
     RECT  33.336 6.539 33.354 6.925 ;
     RECT  4.32 6.575 4.554 6.961 ;
     RECT  4.284 6.961 4.554 7.115 ;
     RECT  34.74 6.808 35.334 7.181 ;
     RECT  35.316 7.181 35.334 7.231 ;
     RECT  33.336 6.925 33.822 7.349 ;
     RECT  2.415 6.845 3.114 7.483 ;
     RECT  5.976 6.719 6.138 7.501 ;
     RECT  18.615 5.225 18.897 7.501 ;
     RECT  35.316 7.231 35.37 7.517 ;
     RECT  18.615 7.501 19.278 7.619 ;
     RECT  5.688 7.501 6.138 7.663 ;
     RECT  2.304 7.483 3.114 7.771 ;
     RECT  5.292 7.663 6.138 7.771 ;
     RECT  4.752 7.771 6.138 7.901 ;
     RECT  2.304 7.771 3.906 7.933 ;
     RECT  33.336 7.349 33.678 7.933 ;
     RECT  5.292 7.901 6.138 8.041 ;
     RECT  7.815 6.305 8.097 8.041 ;
     RECT  8.82 5.603 8.838 8.041 ;
     RECT  33.12 7.933 33.678 8.131 ;
     RECT  5.292 8.041 6.174 8.159 ;
     RECT  5.292 8.159 5.994 8.189 ;
     RECT  2.304 7.933 4.374 8.195 ;
     RECT  7.815 8.041 8.838 8.195 ;
     RECT  35.316 7.517 35.334 8.195 ;
     RECT  33.12 8.131 34.218 8.275 ;
     RECT  5.292 8.189 5.31 8.303 ;
     RECT  33.084 8.275 34.218 8.401 ;
     RECT  32.832 8.401 34.218 8.525 ;
     RECT  30.78 8.131 30.798 8.537 ;
     RECT  32.832 8.525 33.678 8.671 ;
     RECT  17.784 8.581 17.802 8.699 ;
     RECT  31.608 8.581 31.626 8.699 ;
     RECT  32.58 8.671 33.678 8.699 ;
     RECT  32.58 8.699 32.598 8.771 ;
     RECT  35.352 8.401 35.37 8.861 ;
     RECT  2.304 8.195 4.086 9.163 ;
     RECT  2.268 9.163 4.086 9.211 ;
     RECT  14.868 9.121 14.886 9.238 ;
     RECT  5.4 9.121 5.418 9.239 ;
     RECT  6.264 9.163 6.282 9.239 ;
     RECT  2.268 9.211 4.482 9.275 ;
     RECT  2.304 9.275 4.482 9.383 ;
     RECT  33.624 8.699 33.678 9.391 ;
     RECT  14.868 9.238 14.922 9.481 ;
     RECT  2.304 9.383 2.862 9.509 ;
     RECT  14.832 9.481 14.922 9.509 ;
     RECT  14.832 9.509 14.85 9.581 ;
     RECT  33.624 9.391 33.714 9.625 ;
     RECT  3.96 9.383 4.482 9.661 ;
     RECT  32.508 9.211 32.526 9.661 ;
     RECT  32.508 9.661 32.562 9.751 ;
     RECT  3.96 9.661 4.734 9.779 ;
     RECT  17.784 9.553 17.802 9.779 ;
     RECT  33.372 9.625 33.786 9.779 ;
     RECT  3.96 9.779 4.266 9.815 ;
     RECT  32.148 9.751 32.562 9.815 ;
     RECT  3.96 9.815 4.23 9.887 ;
     RECT  6.228 9.391 6.246 10.027 ;
     RECT  32.148 9.815 32.166 10.049 ;
     RECT  3.96 9.887 3.978 10.085 ;
     RECT  5.76 10.027 6.246 10.085 ;
     RECT  33.372 9.779 33.39 10.201 ;
     RECT  6.228 10.085 6.246 10.291 ;
     RECT  6.228 10.291 6.858 10.319 ;
     RECT  2.304 9.509 2.79 10.471 ;
     RECT  6.768 10.319 6.858 10.471 ;
     RECT  33.192 10.201 33.39 10.561 ;
     RECT  32.472 10.561 33.39 10.625 ;
     RECT  0.108 10.507 0.126 10.637 ;
     RECT  19.728 10.561 19.746 10.859 ;
     RECT  6.768 10.471 7.074 10.903 ;
     RECT  7.815 8.195 8.097 10.903 ;
     RECT  8.82 8.195 8.838 10.903 ;
     RECT  14.868 10.867 14.886 10.967 ;
     RECT  2.304 10.471 3.402 11.011 ;
     RECT  4.536 10.843 4.554 11.011 ;
     RECT  32.472 10.625 32.49 11.011 ;
     RECT  6.768 10.903 8.838 11.039 ;
     RECT  19.692 10.939 19.71 11.039 ;
     RECT  35.316 9.163 35.334 11.128 ;
     RECT  32.184 11.011 32.49 11.165 ;
     RECT  6.768 11.039 8.097 11.201 ;
     RECT  18.615 7.619 18.897 11.245 ;
     RECT  6.768 11.201 7.002 11.281 ;
     RECT  17.892 11.245 18.897 11.281 ;
     RECT  35.28 11.128 35.334 11.281 ;
     RECT  2.304 11.011 4.554 11.399 ;
     RECT  6.696 11.281 7.002 11.399 ;
     RECT  17.784 11.281 18.897 11.399 ;
     RECT  31.464 11.245 31.482 11.399 ;
     RECT  5.832 10.831 5.85 11.407 ;
     RECT  34.776 11.281 35.334 11.501 ;
     RECT  33.48 11.281 33.498 11.515 ;
     RECT  3.888 11.399 4.554 11.551 ;
     RECT  5.76 11.407 5.85 11.551 ;
     RECT  33.3 11.515 33.57 11.669 ;
     RECT  3.888 11.551 5.922 11.705 ;
     RECT  2.304 11.399 2.862 11.803 ;
     RECT  5.472 11.705 5.922 11.813 ;
     RECT  32.472 11.165 32.49 11.821 ;
     RECT  33.3 11.669 33.318 11.821 ;
     RECT  5.472 11.813 5.886 11.939 ;
     RECT  32.472 11.821 33.318 11.939 ;
     RECT  3.888 11.705 4.698 11.975 ;
     RECT  18.615 11.399 18.897 12.091 ;
     RECT  0.108 11.947 0.126 12.173 ;
     RECT  18.615 12.091 19.602 12.181 ;
     RECT  5.472 11.939 5.49 12.209 ;
     RECT  18.615 12.181 19.746 12.209 ;
     RECT  32.472 11.939 32.814 12.217 ;
     RECT  2.268 11.803 2.862 12.245 ;
     RECT  22.788 12.217 22.806 12.317 ;
     RECT  6.984 11.399 7.002 12.361 ;
     RECT  7.815 11.201 8.097 12.361 ;
     RECT  2.304 12.245 2.862 12.389 ;
     RECT  19.728 12.209 19.746 12.389 ;
     RECT  6.984 12.361 8.097 12.479 ;
     RECT  35.28 11.501 35.334 12.479 ;
     RECT  2.304 12.389 2.754 12.515 ;
     RECT  32.004 12.217 32.814 12.721 ;
     RECT  31.896 12.721 32.814 12.865 ;
     RECT  33.768 12.451 33.786 12.865 ;
     RECT  3.924 11.975 4.698 12.901 ;
     RECT  5.868 12.859 5.886 12.901 ;
     RECT  5.868 12.901 6.03 13.019 ;
     RECT  31.896 12.865 33.786 13.019 ;
     RECT  32.508 13.019 33.786 13.091 ;
     RECT  3.924 12.901 5.13 13.171 ;
     RECT  3.924 13.171 5.706 13.261 ;
     RECT  19.8 13.171 19.818 13.289 ;
     RECT  2.304 12.515 2.697 13.405 ;
     RECT  2.268 13.405 2.697 13.441 ;
     RECT  6.984 12.479 7.002 13.441 ;
     RECT  7.815 12.479 8.097 13.441 ;
     RECT  2.268 13.441 2.898 13.517 ;
     RECT  2.304 13.517 2.898 13.531 ;
     RECT  3.672 13.261 5.706 13.531 ;
     RECT  6.984 13.441 8.097 13.531 ;
     RECT  6.588 13.531 8.097 13.559 ;
     RECT  14.832 13.441 14.85 13.559 ;
     RECT  6.588 13.559 7.002 13.631 ;
     RECT  2.304 13.531 5.706 13.667 ;
     RECT  18.615 12.209 18.897 13.711 ;
     RECT  35.316 12.479 35.334 13.801 ;
     RECT  19.872 13.441 19.89 13.829 ;
     RECT  4.104 13.667 5.706 13.865 ;
     RECT  32.508 13.091 33.462 13.945 ;
     RECT  5.58 13.865 5.706 13.981 ;
     RECT  32.508 13.945 33.75 13.981 ;
     RECT  2.304 13.667 3.222 14.009 ;
     RECT  18.615 13.711 18.954 14.009 ;
     RECT  2.304 14.009 2.898 14.099 ;
     RECT  4.104 13.865 4.842 14.099 ;
     RECT  5.58 13.981 5.814 14.099 ;
     RECT  32.472 13.981 33.75 14.099 ;
     RECT  18.615 14.009 18.897 14.107 ;
     RECT  4.176 14.099 4.842 14.135 ;
     RECT  4.536 14.135 4.842 14.243 ;
     RECT  6.804 13.631 7.002 14.243 ;
     RECT  6.804 14.243 6.822 14.369 ;
     RECT  18.072 14.107 18.897 14.369 ;
     RECT  34.776 13.801 35.334 14.369 ;
     RECT  5.58 14.099 5.598 14.405 ;
     RECT  32.544 14.099 33.642 14.827 ;
     RECT  34.74 14.491 34.758 14.827 ;
     RECT  2.304 14.099 2.697 14.881 ;
     RECT  32.544 14.827 34.758 14.881 ;
     RECT  2.304 14.881 3.15 14.981 ;
     RECT  2.304 14.981 2.862 15.025 ;
     RECT  2.268 15.025 2.862 15.053 ;
     RECT  4.536 14.243 4.554 15.061 ;
     RECT  5.976 15.025 5.994 15.101 ;
     RECT  32.04 14.881 34.758 15.151 ;
     RECT  32.04 15.151 34.794 15.179 ;
     RECT  2.268 15.053 2.826 15.197 ;
     RECT  32.364 15.179 34.794 15.251 ;
     RECT  3.996 15.061 4.554 15.331 ;
     RECT  18.615 14.369 18.897 15.331 ;
     RECT  3.852 15.331 4.662 15.421 ;
     RECT  2.304 15.197 2.826 15.485 ;
     RECT  34.776 15.251 34.794 15.533 ;
     RECT  5.616 15.601 5.634 15.677 ;
     RECT  32.364 15.251 33.786 15.719 ;
     RECT  3.852 15.421 4.698 15.755 ;
     RECT  2.415 15.485 2.826 15.787 ;
     RECT  4.464 15.755 4.698 15.871 ;
     RECT  4.464 15.871 4.842 15.989 ;
     RECT  17.892 15.331 18.897 15.989 ;
     RECT  4.464 15.989 4.626 16.025 ;
     RECT  32.364 15.719 33.426 16.141 ;
     RECT  2.415 15.787 2.862 16.231 ;
     RECT  7.815 13.559 8.097 16.231 ;
     RECT  8.82 11.039 8.838 16.231 ;
     RECT  17.388 16.141 17.406 16.259 ;
     RECT  32.04 16.141 33.426 16.259 ;
     RECT  0.108 16.123 0.126 16.301 ;
     RECT  2.415 16.231 3.51 16.375 ;
     RECT  5.688 16.339 5.706 16.411 ;
     RECT  35.316 15.787 35.334 16.507 ;
     RECT  5.472 16.411 5.706 16.529 ;
     RECT  7.815 16.231 8.838 16.529 ;
     RECT  18.432 15.989 18.897 16.529 ;
     RECT  32.364 16.259 33.426 16.645 ;
     RECT  32.364 16.645 33.534 16.673 ;
     RECT  32.472 16.673 33.534 16.771 ;
     RECT  4.5 16.025 4.626 16.799 ;
     RECT  2.304 16.375 3.51 16.835 ;
     RECT  32.472 16.771 33.786 16.871 ;
     RECT  5.688 16.529 5.706 16.915 ;
     RECT  4.5 16.799 4.518 16.943 ;
     RECT  35.28 16.507 35.334 16.951 ;
     RECT  3.492 16.835 3.51 16.979 ;
     RECT  32.472 16.871 33.678 17.069 ;
     RECT  5.688 16.915 5.886 17.491 ;
     RECT  7.815 16.529 8.097 17.491 ;
     RECT  8.82 16.529 8.838 17.491 ;
     RECT  34.776 16.951 35.334 17.501 ;
     RECT  7.815 17.491 8.838 17.609 ;
     RECT  28.512 17.041 28.53 17.609 ;
     RECT  5.688 17.491 5.994 17.645 ;
     RECT  18.615 16.529 18.897 17.761 ;
     RECT  0.108 17.653 0.126 17.837 ;
     RECT  5.292 17.761 5.598 17.879 ;
     RECT  18.072 17.761 18.897 17.879 ;
     RECT  32.688 17.069 33.678 17.995 ;
     RECT  5.436 17.879 5.598 18.029 ;
     RECT  2.304 16.835 2.697 18.031 ;
     RECT  3.6 17.041 4.374 18.031 ;
     RECT  32.688 17.995 33.786 18.031 ;
     RECT  2.304 18.031 4.374 18.149 ;
     RECT  5.544 18.029 5.598 18.149 ;
     RECT  14.832 17.887 14.85 18.149 ;
     RECT  32.472 18.031 33.786 18.301 ;
     RECT  7.815 17.609 8.097 18.379 ;
     RECT  8.82 17.609 8.838 18.379 ;
     RECT  7.815 18.379 8.838 18.427 ;
     RECT  5.544 18.149 5.562 18.455 ;
     RECT  10.908 18.301 10.926 18.455 ;
     RECT  35.316 17.501 35.334 18.463 ;
     RECT  7.092 18.427 8.838 18.464 ;
     RECT  34.74 18.463 35.334 18.509 ;
     RECT  3.6 18.149 4.374 18.527 ;
     RECT  31.392 18.427 31.41 18.661 ;
     RECT  32.256 18.301 33.786 18.661 ;
     RECT  31.392 18.661 33.786 18.689 ;
     RECT  18.468 17.879 18.897 18.869 ;
     RECT  2.304 18.149 2.826 19.111 ;
     RECT  3.78 18.527 4.374 19.111 ;
     RECT  3.78 19.111 4.482 19.265 ;
     RECT  31.752 18.689 33.786 19.435 ;
     RECT  0.108 19.345 0.126 19.469 ;
     RECT  4.356 19.265 4.482 19.471 ;
     RECT  5.58 19.381 5.598 19.483 ;
     RECT  3.6 19.345 3.618 19.499 ;
     RECT  5.58 19.483 5.778 19.499 ;
     RECT  17.784 19.381 17.802 19.499 ;
     RECT  31.752 19.435 33.93 19.499 ;
     RECT  31.752 19.499 33.786 19.535 ;
     RECT  18.615 18.869 18.897 19.543 ;
     RECT  18.615 19.543 18.918 19.643 ;
     RECT  4.356 19.471 4.662 19.651 ;
     RECT  5.688 19.499 5.778 19.651 ;
     RECT  5.688 19.651 5.922 19.769 ;
     RECT  7.815 18.464 8.838 19.769 ;
     RECT  26.784 19.543 26.802 19.769 ;
     RECT  32.004 19.535 33.786 19.769 ;
     RECT  35.316 18.509 35.334 19.813 ;
     RECT  30.78 19.471 30.798 19.841 ;
     RECT  4.356 19.651 4.806 19.949 ;
     RECT  6.84 19.921 6.858 20.039 ;
     RECT  5.688 19.769 5.706 20.075 ;
     RECT  17.172 19.921 17.19 20.219 ;
     RECT  32.004 19.769 32.922 20.309 ;
     RECT  2.304 19.111 2.862 20.461 ;
     RECT  4.356 19.949 4.626 20.461 ;
     RECT  18.615 19.643 18.897 20.461 ;
     RECT  33.66 19.769 33.786 20.489 ;
     RECT  5.76 20.539 5.994 20.551 ;
     RECT  18.036 20.461 18.897 20.579 ;
     RECT  32.184 20.309 32.922 20.615 ;
     RECT  32.22 20.615 32.922 20.659 ;
     RECT  33.66 20.489 33.714 20.659 ;
     RECT  5.76 20.551 6.246 20.857 ;
     RECT  4.14 20.461 4.626 21.001 ;
     RECT  30.78 20.821 30.798 21.029 ;
     RECT  34.776 19.813 35.334 21.115 ;
     RECT  2.304 20.461 3.33 21.119 ;
     RECT  4.14 21.001 4.842 21.119 ;
     RECT  5.76 20.857 6.858 21.127 ;
     RECT  22.716 21.091 22.734 21.127 ;
     RECT  5.76 21.127 6.966 21.155 ;
     RECT  6.696 21.155 6.966 21.163 ;
     RECT  22.716 21.127 22.806 21.191 ;
     RECT  34.74 21.115 35.334 21.191 ;
     RECT  22.788 21.191 22.806 21.263 ;
     RECT  4.14 21.119 4.59 21.271 ;
     RECT  35.316 21.191 35.334 21.271 ;
     RECT  6.696 21.163 7.038 21.397 ;
     RECT  32.22 20.659 33.714 21.505 ;
     RECT  5.76 21.155 5.778 21.643 ;
     RECT  32.22 21.505 33.822 21.659 ;
     RECT  35.316 21.271 35.406 21.659 ;
     RECT  4.104 21.271 4.59 21.677 ;
     RECT  35.352 21.659 35.406 21.869 ;
     RECT  2.304 21.119 2.697 21.937 ;
     RECT  6.696 21.397 7.074 22.009 ;
     RECT  7.815 19.769 8.097 22.009 ;
     RECT  18.615 20.579 18.897 22.045 ;
     RECT  2.268 21.937 2.697 22.081 ;
     RECT  4.104 21.677 4.554 22.081 ;
     RECT  5.544 21.643 5.778 22.081 ;
     RECT  6.696 22.009 8.097 22.081 ;
     RECT  18.144 22.045 18.897 22.081 ;
     RECT  2.268 22.081 2.754 22.157 ;
     RECT  35.388 21.869 35.406 22.157 ;
     RECT  5.544 22.081 8.097 22.171 ;
     RECT  5.472 22.171 8.097 22.199 ;
     RECT  18.072 22.081 18.897 22.199 ;
     RECT  32.652 21.659 33.822 22.459 ;
     RECT  17.676 22.207 17.694 22.469 ;
     RECT  2.304 22.157 2.754 22.477 ;
     RECT  7.056 22.199 8.097 22.505 ;
     RECT  14.832 22.477 14.85 22.649 ;
     RECT  32.652 22.459 34.218 22.649 ;
     RECT  7.2 22.505 8.097 22.739 ;
     RECT  30.78 22.477 30.798 22.739 ;
     RECT  32.652 22.649 33.822 22.739 ;
     RECT  32.652 22.739 33.642 22.783 ;
     RECT  32.58 22.783 33.642 23.009 ;
     RECT  32.58 23.009 33.534 23.045 ;
     RECT  2.304 22.477 2.826 23.161 ;
     RECT  3.708 22.081 4.554 23.161 ;
     RECT  5.472 22.199 5.778 23.161 ;
     RECT  18.615 22.199 18.897 23.161 ;
     RECT  2.304 23.161 5.778 23.179 ;
     RECT  18.615 23.161 19.314 23.431 ;
     RECT  0.108 23.287 0.126 23.501 ;
     RECT  6.696 23.431 6.714 23.563 ;
     RECT  32.58 23.045 33.354 23.593 ;
     RECT  2.268 23.179 5.778 23.665 ;
     RECT  18.615 23.431 19.386 23.701 ;
     RECT  6.696 23.563 6.966 23.741 ;
     RECT  35.28 22.783 35.334 23.791 ;
     RECT  32.112 23.593 33.354 23.819 ;
     RECT  32.544 23.819 33.354 23.827 ;
     RECT  34.776 23.791 35.334 23.837 ;
     RECT  2.268 23.665 5.922 23.855 ;
     RECT  2.268 23.855 4.482 23.927 ;
     RECT  7.815 22.739 8.097 23.935 ;
     RECT  18.615 23.701 19.458 23.935 ;
     RECT  18.396 23.935 19.458 23.999 ;
     RECT  7.524 23.935 8.097 24.089 ;
     RECT  18.396 23.999 19.098 24.089 ;
     RECT  32.544 23.827 33.534 24.089 ;
     RECT  2.304 23.927 4.482 24.125 ;
     RECT  5.328 23.855 5.922 24.125 ;
     RECT  32.652 24.089 33.534 24.205 ;
     RECT  7.56 24.089 8.097 24.233 ;
     RECT  5.76 24.125 5.922 24.241 ;
     RECT  35.316 23.837 35.334 24.241 ;
     RECT  5.76 24.241 6.282 24.539 ;
     RECT  35.316 24.241 35.37 24.557 ;
     RECT  7.815 24.233 8.097 24.619 ;
     RECT  8.82 19.769 8.838 24.619 ;
     RECT  35.316 24.557 35.334 24.811 ;
     RECT  6.696 24.781 6.714 24.871 ;
     RECT  6.696 24.871 6.822 24.899 ;
     RECT  17.244 24.781 17.262 24.899 ;
     RECT  18.615 24.089 19.098 24.899 ;
     RECT  34.74 24.811 35.334 24.899 ;
     RECT  2.415 24.125 4.482 24.971 ;
     RECT  18.615 24.899 19.062 24.979 ;
     RECT  4.248 24.971 4.482 25.051 ;
     RECT  7.815 24.619 8.838 25.085 ;
     RECT  0.108 24.571 0.126 25.181 ;
     RECT  31.896 25.177 31.914 25.213 ;
     RECT  18.252 24.979 19.062 25.241 ;
     RECT  17.352 25.051 17.37 25.277 ;
     RECT  4.248 25.051 4.59 25.285 ;
     RECT  4.248 25.285 4.914 25.321 ;
     RECT  5.76 24.539 5.778 25.321 ;
     RECT  18.615 25.241 19.062 25.349 ;
     RECT  2.415 24.971 3.33 25.439 ;
     RECT  6.804 24.899 6.822 25.439 ;
     RECT  14.832 24.907 14.85 25.439 ;
     RECT  31.824 25.213 31.914 25.439 ;
     RECT  2.415 25.439 2.97 25.483 ;
     RECT  4.248 25.321 5.778 25.511 ;
     RECT  34.776 24.899 35.334 25.517 ;
     RECT  2.304 25.483 2.97 25.583 ;
     RECT  32.652 24.205 33.642 25.591 ;
     RECT  4.248 25.511 4.446 25.709 ;
     RECT  4.248 25.709 4.266 25.745 ;
     RECT  32.184 25.591 33.75 25.781 ;
     RECT  35.28 25.517 35.334 25.889 ;
     RECT  5.76 25.511 5.778 26.131 ;
     RECT  0.108 26.059 0.126 26.189 ;
     RECT  2.34 25.583 2.97 26.365 ;
     RECT  18.615 25.349 18.897 26.365 ;
     RECT  32.184 25.781 32.886 26.365 ;
     RECT  3.996 26.131 4.014 26.401 ;
     RECT  5.76 26.131 5.922 26.401 ;
     RECT  18.036 26.365 18.897 26.401 ;
     RECT  35.316 25.889 35.334 26.429 ;
     RECT  7.815 25.085 8.097 26.491 ;
     RECT  8.82 25.085 8.838 26.491 ;
     RECT  33.66 25.781 33.75 26.491 ;
     RECT  6.768 26.401 6.786 26.519 ;
     RECT  31.932 26.365 32.886 26.519 ;
     RECT  2.304 26.365 2.97 26.525 ;
     RECT  2.34 26.525 2.97 26.555 ;
     RECT  32.004 26.519 32.886 26.563 ;
     RECT  33.66 26.491 34.218 26.563 ;
     RECT  32.004 26.563 34.218 26.591 ;
     RECT  5.688 26.401 5.994 26.635 ;
     RECT  3.78 26.401 4.014 26.671 ;
     RECT  17.964 26.401 18.897 26.671 ;
     RECT  3.78 26.671 4.518 26.779 ;
     RECT  5.688 26.635 6.174 26.779 ;
     RECT  3.78 26.779 6.174 26.789 ;
     RECT  17.784 26.671 18.897 26.789 ;
     RECT  30.78 26.527 30.798 26.789 ;
     RECT  32.004 26.591 33.786 26.789 ;
     RECT  3.78 26.789 6.138 26.861 ;
     RECT  36.18 26.671 36.198 26.861 ;
     RECT  32.004 26.789 33.282 27.059 ;
     RECT  17.892 26.789 18.897 27.175 ;
     RECT  7.815 26.491 8.838 27.211 ;
     RECT  17.892 27.175 19.422 27.239 ;
     RECT  4.068 26.861 6.138 27.329 ;
     RECT  18.615 27.239 19.422 27.329 ;
     RECT  32.004 27.059 32.814 27.401 ;
     RECT  2.34 26.555 2.862 27.499 ;
     RECT  4.068 27.329 5.85 27.599 ;
     RECT  33.768 27.571 33.786 27.671 ;
     RECT  2.304 27.499 2.862 27.751 ;
     RECT  4.068 27.599 5.058 27.751 ;
     RECT  7.815 27.211 9.054 27.751 ;
     RECT  32.076 27.401 32.814 27.841 ;
     RECT  5.832 27.599 5.85 27.869 ;
     RECT  7.815 27.751 9.09 27.869 ;
     RECT  17.568 27.679 17.694 27.869 ;
     RECT  18.615 27.329 19.062 27.869 ;
     RECT  2.304 27.751 5.058 27.905 ;
     RECT  7.815 27.869 8.838 27.917 ;
     RECT  35.316 27.163 35.334 28.111 ;
     RECT  17.676 27.869 17.694 28.139 ;
     RECT  32.076 27.841 33.642 28.291 ;
     RECT  32.04 28.291 33.642 28.381 ;
     RECT  34.776 28.111 35.334 28.381 ;
     RECT  2.412 27.905 5.058 28.481 ;
     RECT  31.968 28.381 33.642 28.481 ;
     RECT  17.712 28.381 17.73 28.679 ;
     RECT  4.176 28.481 5.058 28.759 ;
     RECT  2.412 28.481 3.258 28.795 ;
     RECT  4.176 28.759 5.742 28.831 ;
     RECT  7.815 27.917 8.097 28.831 ;
     RECT  32.472 28.481 33.642 28.831 ;
     RECT  4.176 28.831 6.246 28.939 ;
     RECT  7.344 28.831 8.097 28.957 ;
     RECT  4.176 28.939 6.426 28.993 ;
     RECT  18.615 27.869 18.897 29.101 ;
     RECT  4.176 28.993 6.534 29.129 ;
     RECT  6.516 29.129 6.534 29.179 ;
     RECT  7.272 28.957 8.097 29.179 ;
     RECT  6.516 29.179 8.097 29.219 ;
     RECT  17.892 29.101 18.897 29.219 ;
     RECT  2.304 28.795 3.258 29.255 ;
     RECT  7.272 29.219 8.097 29.255 ;
     RECT  7.815 29.255 8.097 29.335 ;
     RECT  8.82 27.917 8.838 29.335 ;
     RECT  32.472 28.831 33.714 29.335 ;
     RECT  32.472 29.335 33.75 29.371 ;
     RECT  7.815 29.335 8.874 29.489 ;
     RECT  4.176 29.129 5.742 29.497 ;
     RECT  34.776 28.381 35.37 29.501 ;
     RECT  32.472 29.371 34.002 29.605 ;
     RECT  2.415 29.255 3.258 29.641 ;
     RECT  4.032 29.497 5.742 29.641 ;
     RECT  7.815 29.489 8.226 29.645 ;
     RECT  17.964 29.219 18.897 29.759 ;
     RECT  2.415 29.641 5.742 29.795 ;
     RECT  35.316 29.501 35.37 29.837 ;
     RECT  2.415 29.795 3.438 30.029 ;
     RECT  2.415 30.029 3.402 30.091 ;
     RECT  4.248 29.795 5.742 30.235 ;
     RECT  4.248 30.235 5.994 30.335 ;
     RECT  17.1 30.181 17.118 30.335 ;
     RECT  31.932 29.605 34.002 30.365 ;
     RECT  31.932 30.365 33.786 30.415 ;
     RECT  6.84 30.307 6.858 30.451 ;
     RECT  7.815 29.645 8.097 30.451 ;
     RECT  31.752 30.415 33.786 30.569 ;
     RECT  35.316 29.837 35.334 30.571 ;
     RECT  18.108 29.759 18.897 30.605 ;
     RECT  6.84 30.451 8.097 30.677 ;
     RECT  4.248 30.335 5.778 30.721 ;
     RECT  6.84 30.677 6.858 30.847 ;
     RECT  6.516 30.847 6.858 30.875 ;
     RECT  0.108 30.763 0.126 30.893 ;
     RECT  36.18 30.763 36.198 30.893 ;
     RECT  10.8 30.847 10.818 30.983 ;
     RECT  2.304 30.091 3.402 30.991 ;
     RECT  4.176 30.721 5.778 30.991 ;
     RECT  34.92 30.571 35.334 30.991 ;
     RECT  7.704 30.677 8.097 31.019 ;
     RECT  2.304 30.991 5.778 31.145 ;
     RECT  6.516 30.875 6.534 31.145 ;
     RECT  30.852 30.847 30.87 31.217 ;
     RECT  5.724 31.145 5.778 31.261 ;
     RECT  2.304 31.145 4.59 31.415 ;
     RECT  32.616 30.569 33.786 31.459 ;
     RECT  2.34 31.415 4.59 31.685 ;
     RECT  32.004 31.459 33.786 31.721 ;
     RECT  18.615 30.605 18.897 31.729 ;
     RECT  32.004 31.721 33.714 31.801 ;
     RECT  5.724 31.261 6.246 31.891 ;
     RECT  34.776 30.991 35.334 31.891 ;
     RECT  31.5 31.801 33.714 31.919 ;
     RECT  2.34 31.685 2.79 32.155 ;
     RECT  17.928 31.729 19.386 32.189 ;
     RECT  5.652 31.891 6.246 32.305 ;
     RECT  18.615 32.189 19.386 32.305 ;
     RECT  5.4 32.305 6.246 32.341 ;
     RECT  7.815 31.019 8.097 32.341 ;
     RECT  3.924 31.685 4.59 32.459 ;
     RECT  18.615 32.305 19.782 32.459 ;
     RECT  32.112 31.919 33.714 32.467 ;
     RECT  32.112 32.467 33.786 32.495 ;
     RECT  4.068 32.459 4.59 32.611 ;
     RECT  34.776 31.891 35.37 32.621 ;
     RECT  5.4 32.341 6.534 32.731 ;
     RECT  7.452 32.341 8.097 32.731 ;
     RECT  5.4 32.731 8.406 32.771 ;
     RECT  4.068 32.611 4.626 32.881 ;
     RECT  5.4 32.771 8.097 32.881 ;
     RECT  17.136 32.845 17.154 32.881 ;
     RECT  17.136 32.881 17.262 32.999 ;
     RECT  31.608 32.881 31.626 32.999 ;
     RECT  2.304 32.155 2.79 33.019 ;
     RECT  4.068 32.881 8.097 33.035 ;
     RECT  34.776 32.621 35.334 33.053 ;
     RECT  4.068 33.035 5.454 33.305 ;
     RECT  6.228 33.035 8.097 33.305 ;
     RECT  32.472 32.495 33.786 33.305 ;
     RECT  2.304 33.019 2.862 33.421 ;
     RECT  4.068 33.305 4.842 33.421 ;
     RECT  18.615 32.459 19.314 33.449 ;
     RECT  2.304 33.421 4.842 33.499 ;
     RECT  2.268 33.499 4.842 33.539 ;
     RECT  32.112 33.313 32.13 33.539 ;
     RECT  0.54 33.583 0.558 33.773 ;
     RECT  33.084 33.305 33.786 33.809 ;
     RECT  2.268 33.539 3.258 33.845 ;
     RECT  35.316 33.053 35.334 33.931 ;
     RECT  33.084 33.809 33.714 34.051 ;
     RECT  5.76 33.925 5.922 34.079 ;
     RECT  14.832 32.971 14.85 34.079 ;
     RECT  32.796 34.051 33.714 34.151 ;
     RECT  4.068 33.539 4.842 34.231 ;
     RECT  18.615 33.449 18.897 34.231 ;
     RECT  18.54 34.231 18.897 34.321 ;
     RECT  4.068 34.231 5.634 34.349 ;
     RECT  18.54 34.321 18.954 34.421 ;
     RECT  2.34 33.845 3.258 34.465 ;
     RECT  4.068 34.349 4.842 34.465 ;
     RECT  18.54 34.421 18.897 34.501 ;
     RECT  26.784 34.357 26.802 34.529 ;
     RECT  35.28 33.931 35.334 34.591 ;
     RECT  18.216 34.501 18.897 34.619 ;
     RECT  6.84 33.305 8.097 34.655 ;
     RECT  34.776 34.591 35.334 34.685 ;
     RECT  6.912 34.655 8.097 34.781 ;
     RECT  32.832 34.151 33.714 35.005 ;
     RECT  32.832 35.005 33.786 35.041 ;
     RECT  2.34 34.465 4.842 35.083 ;
     RECT  31.464 34.627 31.482 35.131 ;
     RECT  32.472 35.041 33.786 35.131 ;
     RECT  2.304 35.083 4.842 35.167 ;
     RECT  5.616 34.349 5.634 35.167 ;
     RECT  2.304 35.167 5.634 35.275 ;
     RECT  2.304 35.275 5.994 35.465 ;
     RECT  31.464 35.131 33.786 35.473 ;
     RECT  6.912 34.781 6.93 35.509 ;
     RECT  31.356 35.473 33.786 35.509 ;
     RECT  30.78 35.509 33.786 35.609 ;
     RECT  7.815 34.781 8.097 35.659 ;
     RECT  26.784 35.437 26.802 35.671 ;
     RECT  6.84 35.509 6.93 35.699 ;
     RECT  16.812 35.581 16.83 35.699 ;
     RECT  31.356 35.609 33.786 35.699 ;
     RECT  7.815 35.659 8.154 35.743 ;
     RECT  35.316 34.685 35.334 35.743 ;
     RECT  5.688 35.465 5.994 35.755 ;
     RECT  6.84 35.699 6.858 35.755 ;
     RECT  26.784 35.671 26.874 35.771 ;
     RECT  7.815 35.743 8.298 35.789 ;
     RECT  34.776 35.743 35.334 35.789 ;
     RECT  26.784 35.771 26.802 35.843 ;
     RECT  31.788 35.699 33.786 35.843 ;
     RECT  14.832 35.707 14.85 35.879 ;
     RECT  5.688 35.755 6.858 36.113 ;
     RECT  32.724 35.843 33.786 36.355 ;
     RECT  2.304 35.465 4.806 36.391 ;
     RECT  5.688 36.113 6.822 36.391 ;
     RECT  32.724 36.355 33.822 36.427 ;
     RECT  2.304 36.391 6.822 36.461 ;
     RECT  32.724 36.427 34.218 36.661 ;
     RECT  35.316 35.789 35.334 36.661 ;
     RECT  31.5 36.517 31.518 36.751 ;
     RECT  28.512 36.211 28.53 36.779 ;
     RECT  18.615 34.619 18.897 36.787 ;
     RECT  2.304 36.461 6.246 36.815 ;
     RECT  18.144 36.787 18.897 36.823 ;
     RECT  32.4 36.661 34.218 36.823 ;
     RECT  35.316 36.661 35.37 36.823 ;
     RECT  7.815 35.789 8.097 36.859 ;
     RECT  17.712 36.823 18.897 36.859 ;
     RECT  26.784 36.787 26.802 36.887 ;
     RECT  30.996 36.751 31.518 36.887 ;
     RECT  31.14 36.887 31.518 36.895 ;
     RECT  32.4 36.823 35.37 36.895 ;
     RECT  31.14 36.895 35.37 36.941 ;
     RECT  7.815 36.859 8.298 36.955 ;
     RECT  31.14 36.941 34.218 36.959 ;
     RECT  2.304 36.815 4.698 37.049 ;
     RECT  7.344 36.955 8.298 37.049 ;
     RECT  31.14 36.959 33.822 37.049 ;
     RECT  35.28 36.941 35.37 37.133 ;
     RECT  5.436 36.815 6.246 37.201 ;
     RECT  17.712 36.859 19.206 37.201 ;
     RECT  9.252 37.201 9.27 37.319 ;
     RECT  17.712 37.201 19.314 37.319 ;
     RECT  4.14 37.049 4.698 37.355 ;
     RECT  5.436 37.201 6.858 37.469 ;
     RECT  7.815 37.049 8.298 37.471 ;
     RECT  10.836 37.327 10.854 37.499 ;
     RECT  14.832 37.327 14.85 37.499 ;
     RECT  18.615 37.319 19.314 37.499 ;
     RECT  7.815 37.471 8.406 37.589 ;
     RECT  32.22 37.049 33.786 37.589 ;
     RECT  5.58 37.469 6.858 37.625 ;
     RECT  7.815 37.589 8.19 37.819 ;
     RECT  10.764 37.741 10.782 37.859 ;
     RECT  2.304 37.049 3.114 37.895 ;
     RECT  35.28 37.133 35.334 38.011 ;
     RECT  4.356 37.355 4.698 38.101 ;
     RECT  32.364 37.589 33.786 38.101 ;
     RECT  32.364 38.101 33.93 38.137 ;
     RECT  34.74 38.011 35.334 38.137 ;
     RECT  32.364 38.137 35.334 38.173 ;
     RECT  4.284 38.101 4.698 38.203 ;
     RECT  4.284 38.203 5.094 38.237 ;
     RECT  32.364 38.173 35.37 38.285 ;
     RECT  18.615 37.499 18.897 38.443 ;
     RECT  6.912 37.819 8.19 38.471 ;
     RECT  32.364 38.285 35.334 38.477 ;
     RECT  6.912 38.471 8.154 38.539 ;
     RECT  19.8 38.515 19.818 38.551 ;
     RECT  32.364 38.477 34.218 38.551 ;
     RECT  6.156 38.539 8.154 38.579 ;
     RECT  6.156 38.579 8.097 38.635 ;
     RECT  18.108 38.443 18.897 38.669 ;
     RECT  19.8 38.551 19.89 38.669 ;
     RECT  31.86 38.551 34.218 38.669 ;
     RECT  2.304 37.895 2.697 38.713 ;
     RECT  3.888 38.635 3.906 38.713 ;
     RECT  5.976 38.635 8.097 38.717 ;
     RECT  4.824 38.237 5.094 38.731 ;
     RECT  5.976 38.717 6.174 38.731 ;
     RECT  32.076 38.669 34.218 38.741 ;
     RECT  6.948 38.717 8.097 38.765 ;
     RECT  35.316 38.477 35.334 38.939 ;
     RECT  4.824 38.731 6.174 39.209 ;
     RECT  18.288 38.669 18.897 39.209 ;
     RECT  19.62 39.091 19.746 39.209 ;
     RECT  2.304 38.713 3.906 39.217 ;
     RECT  4.824 39.209 6.138 39.217 ;
     RECT  19.728 39.209 19.746 39.317 ;
     RECT  2.304 39.217 6.138 39.389 ;
     RECT  32.508 38.741 34.218 39.559 ;
     RECT  32.508 39.559 34.794 39.629 ;
     RECT  32.508 39.629 34.218 39.857 ;
     RECT  7.815 38.765 8.097 39.865 ;
     RECT  35.316 39.787 35.334 39.865 ;
     RECT  7.416 39.865 8.097 39.901 ;
     RECT  2.415 39.389 6.138 39.917 ;
     RECT  18.615 39.209 18.897 39.991 ;
     RECT  32.508 39.857 33.93 39.991 ;
     RECT  32.256 39.991 33.93 40.019 ;
     RECT  32.256 40.019 32.634 40.027 ;
     RECT  14.832 40.027 14.85 40.127 ;
     RECT  10.8 40.027 10.818 40.199 ;
     RECT  17.676 39.829 17.694 40.199 ;
     RECT  31.932 40.027 32.634 40.261 ;
     RECT  5.94 39.917 6.138 40.289 ;
     RECT  31.86 40.261 32.634 40.361 ;
     RECT  33.588 40.019 33.93 40.361 ;
     RECT  5.976 40.289 6.138 40.445 ;
     RECT  2.415 39.917 5.202 40.507 ;
     RECT  2.304 40.507 5.202 40.559 ;
     RECT  6.984 39.901 8.097 40.559 ;
     RECT  33.588 40.361 33.822 40.559 ;
     RECT  2.304 40.559 2.862 40.595 ;
     RECT  6.12 40.445 6.138 40.595 ;
     RECT  19.764 39.865 19.782 40.595 ;
     RECT  6.984 40.559 7.002 40.603 ;
     RECT  35.316 39.865 35.37 40.747 ;
     RECT  19.692 40.603 19.71 40.829 ;
     RECT  31.824 40.711 31.842 40.829 ;
     RECT  35.28 40.747 35.37 40.829 ;
     RECT  3.996 40.559 5.202 40.973 ;
     RECT  35.316 40.829 35.37 40.973 ;
     RECT  30.78 40.837 30.798 41.009 ;
     RECT  4.14 40.973 5.202 41.035 ;
     RECT  4.14 41.035 5.31 41.099 ;
     RECT  4.14 41.099 5.238 41.171 ;
     RECT  32.58 40.361 32.634 41.179 ;
     RECT  33.588 40.559 33.786 41.179 ;
     RECT  18.576 39.991 18.897 41.251 ;
     RECT  10.836 41.251 10.854 41.369 ;
     RECT  18.288 41.251 18.897 41.369 ;
     RECT  6.84 40.603 7.002 41.462 ;
     RECT  7.815 40.559 8.097 41.462 ;
     RECT  32.58 41.179 33.786 41.477 ;
     RECT  32.58 41.477 33.714 41.521 ;
     RECT  30.852 41.341 30.87 41.549 ;
     RECT  6.84 41.462 8.097 41.639 ;
     RECT  18.36 41.369 18.897 41.639 ;
     RECT  35.316 40.973 35.334 41.647 ;
     RECT  2.304 40.595 2.697 41.659 ;
     RECT  9.036 41.143 9.054 41.683 ;
     RECT  34.776 41.647 35.334 41.693 ;
     RECT  4.14 41.171 5.13 41.791 ;
     RECT  4.032 41.791 5.13 41.899 ;
     RECT  6.444 41.881 6.642 41.899 ;
     RECT  22.788 41.791 22.806 41.909 ;
     RECT  31.068 41.791 31.374 41.909 ;
     RECT  2.304 41.659 2.754 41.945 ;
     RECT  10.8 41.917 10.818 42.017 ;
     RECT  2.304 41.945 2.697 42.025 ;
     RECT  9.036 41.683 9.126 42.089 ;
     RECT  2.268 42.025 2.697 42.125 ;
     RECT  4.032 41.899 6.642 42.151 ;
     RECT  32.544 41.521 33.714 42.151 ;
     RECT  3.42 42.151 6.642 42.179 ;
     RECT  31.068 41.909 31.086 42.179 ;
     RECT  3.42 42.179 6.246 42.224 ;
     RECT  18.432 41.639 18.897 42.331 ;
     RECT  18.432 42.331 19.098 42.449 ;
     RECT  18.432 42.449 18.99 42.565 ;
     RECT  32.472 42.151 33.714 42.565 ;
     RECT  17.892 42.565 18.99 42.719 ;
     RECT  32.364 42.565 33.714 42.719 ;
     RECT  32.544 42.719 33.714 42.727 ;
     RECT  3.42 42.224 5.598 42.755 ;
     RECT  7.56 41.639 8.097 42.871 ;
     RECT  11.736 42.763 11.754 42.989 ;
     RECT  17.964 42.719 18.99 42.989 ;
     RECT  35.316 41.693 35.334 42.997 ;
     RECT  10.836 42.961 10.854 43.003 ;
     RECT  0.108 42.727 0.126 43.037 ;
     RECT  10.836 43.003 10.926 43.061 ;
     RECT  22.788 42.997 22.806 43.097 ;
     RECT  9.108 42.089 9.126 43.169 ;
     RECT  18.615 42.989 18.99 43.169 ;
     RECT  10.908 43.061 10.926 43.181 ;
     RECT  12.06 43.141 12.078 43.181 ;
     RECT  2.304 42.125 2.697 43.243 ;
     RECT  3.42 42.755 5.166 43.259 ;
     RECT  34.776 42.997 35.334 43.277 ;
     RECT  2.268 43.243 2.697 43.367 ;
     RECT  32.544 42.727 33.786 43.411 ;
     RECT  32.544 43.411 34.218 43.501 ;
     RECT  3.672 43.259 4.698 43.529 ;
     RECT  7.056 42.871 8.097 43.681 ;
     RECT  6.768 43.681 8.097 43.799 ;
     RECT  17.568 43.681 17.838 43.799 ;
     RECT  14.832 43.771 14.85 43.871 ;
     RECT  2.304 43.367 2.697 43.915 ;
     RECT  32.22 43.501 34.218 44.041 ;
     RECT  35.316 43.277 35.334 44.069 ;
     RECT  4.104 43.529 4.698 44.221 ;
     RECT  5.796 43.807 5.814 44.221 ;
     RECT  18.615 43.169 18.897 44.221 ;
     RECT  32.148 44.041 34.218 44.249 ;
     RECT  2.304 43.915 2.754 44.311 ;
     RECT  4.104 44.221 5.814 44.311 ;
     RECT  32.148 44.249 33.822 44.311 ;
     RECT  6.804 43.799 8.097 44.339 ;
     RECT  32.076 44.311 33.822 44.411 ;
     RECT  2.304 44.311 5.814 44.443 ;
     RECT  2.304 44.443 6.066 44.609 ;
     RECT  30.78 44.491 30.798 44.609 ;
     RECT  5.832 44.609 5.886 44.645 ;
     RECT  2.304 44.609 4.914 44.725 ;
     RECT  18.504 44.221 18.897 44.761 ;
     RECT  2.268 44.725 4.914 44.861 ;
     RECT  34.776 44.341 34.794 44.861 ;
     RECT  5.832 44.645 5.85 44.879 ;
     RECT  6.948 44.339 8.097 44.879 ;
     RECT  9.108 44.761 9.126 44.879 ;
     RECT  18.144 44.761 18.897 44.879 ;
     RECT  32.472 44.411 33.822 44.879 ;
     RECT  14.832 44.887 14.85 44.987 ;
     RECT  2.304 44.861 4.914 45.023 ;
     RECT  10.8 44.887 10.818 45.023 ;
     RECT  30.852 44.761 30.978 45.031 ;
     RECT  30.852 45.031 31.374 45.427 ;
     RECT  30.78 45.427 31.374 45.527 ;
     RECT  6.948 44.879 7.074 45.547 ;
     RECT  6.696 45.547 7.074 45.599 ;
     RECT  6.804 45.599 7.074 45.689 ;
     RECT  5.616 45.571 5.634 45.725 ;
     RECT  2.304 45.023 4.662 45.761 ;
     RECT  0.54 45.229 0.558 45.773 ;
     RECT  7.056 45.689 7.074 45.773 ;
     RECT  4.104 45.761 4.662 45.835 ;
     RECT  4.104 45.835 4.878 45.875 ;
     RECT  32.472 44.879 33.786 45.931 ;
     RECT  2.304 45.761 3.114 45.959 ;
     RECT  31.5 45.697 31.518 45.959 ;
     RECT  35.316 45.067 35.334 45.979 ;
     RECT  2.304 45.959 2.898 45.995 ;
     RECT  26.784 45.967 26.802 46.067 ;
     RECT  32.436 45.931 33.786 46.171 ;
     RECT  32.436 46.171 33.894 46.301 ;
     RECT  4.104 45.875 4.806 46.373 ;
     RECT  32.436 46.301 33.714 46.381 ;
     RECT  4.104 46.373 4.698 46.499 ;
     RECT  32.364 46.381 33.714 46.535 ;
     RECT  4.104 46.499 4.626 46.651 ;
     RECT  35.28 45.979 35.334 46.651 ;
     RECT  7.815 44.879 8.097 46.741 ;
     RECT  7.596 46.741 8.097 46.747 ;
     RECT  5.688 46.747 5.706 46.805 ;
     RECT  7.128 46.747 8.097 46.921 ;
     RECT  7.128 46.921 8.226 47.075 ;
     RECT  18.615 44.879 18.897 47.155 ;
     RECT  2.304 45.995 2.862 47.191 ;
     RECT  3.96 46.651 4.626 47.191 ;
     RECT  18.18 47.155 18.897 47.191 ;
     RECT  2.304 47.191 4.626 47.309 ;
     RECT  7.128 47.075 8.097 47.309 ;
     RECT  8.82 47.191 8.838 47.309 ;
     RECT  35.28 46.651 35.37 47.357 ;
     RECT  4.464 47.309 4.626 47.461 ;
     RECT  31.644 47.389 31.662 47.461 ;
     RECT  32.436 46.535 33.714 47.461 ;
     RECT  4.464 47.461 4.698 47.489 ;
     RECT  17.676 47.191 18.897 47.579 ;
     RECT  31.644 47.461 33.714 47.579 ;
     RECT  30.78 46.849 30.798 47.587 ;
     RECT  4.68 47.489 4.698 47.695 ;
     RECT  5.472 47.155 5.49 47.695 ;
     RECT  31.86 47.579 33.714 47.695 ;
     RECT  30.78 47.587 30.87 47.723 ;
     RECT  35.28 47.357 35.334 47.731 ;
     RECT  34.776 47.731 35.334 47.789 ;
     RECT  18.036 47.579 18.897 47.849 ;
     RECT  30.78 47.723 30.798 47.849 ;
     RECT  31.86 47.695 33.75 47.849 ;
     RECT  4.68 47.695 5.49 47.851 ;
     RECT  32.004 47.849 33.75 47.995 ;
     RECT  4.68 47.851 5.562 48.001 ;
     RECT  32.004 47.995 34.218 48.191 ;
     RECT  4.68 48.001 5.706 48.299 ;
     RECT  2.304 47.309 2.697 48.427 ;
     RECT  4.68 48.299 5.202 48.541 ;
     RECT  3.96 48.541 5.202 48.659 ;
     RECT  6.984 48.541 7.002 48.659 ;
     RECT  17.46 48.505 17.586 48.659 ;
     RECT  4.248 48.659 4.914 48.701 ;
     RECT  2.304 48.427 2.754 48.739 ;
     RECT  6.84 48.775 6.858 48.811 ;
     RECT  2.304 48.739 2.862 48.839 ;
     RECT  14.832 48.667 14.85 48.839 ;
     RECT  6.3 48.811 6.858 48.845 ;
     RECT  35.316 47.789 35.334 48.907 ;
     RECT  6.3 48.845 6.534 48.929 ;
     RECT  19.872 48.271 19.89 48.929 ;
     RECT  32.004 48.191 33.93 49.001 ;
     RECT  35.28 48.907 35.334 49.001 ;
     RECT  18.615 47.849 18.897 49.081 ;
     RECT  0.108 48.973 0.126 49.181 ;
     RECT  5.832 49.081 5.85 49.199 ;
     RECT  17.1 48.901 17.118 49.199 ;
     RECT  18.072 49.081 18.897 49.199 ;
     RECT  31.536 49.171 31.734 49.243 ;
     RECT  31.356 49.243 31.734 49.469 ;
     RECT  4.896 48.701 4.914 49.549 ;
     RECT  30.852 49.477 30.87 49.577 ;
     RECT  4.896 49.549 5.778 49.621 ;
     RECT  7.815 47.309 8.097 49.621 ;
     RECT  4.176 49.621 5.778 49.739 ;
     RECT  10.8 49.621 10.818 49.739 ;
     RECT  18.216 49.199 18.897 49.739 ;
     RECT  30.78 49.585 30.798 49.739 ;
     RECT  2.304 48.839 2.697 49.747 ;
     RECT  32.544 49.001 33.714 49.855 ;
     RECT  32.544 49.855 33.786 49.891 ;
     RECT  2.304 49.747 3.33 49.919 ;
     RECT  31.752 49.819 31.77 49.919 ;
     RECT  32.544 49.891 33.93 49.981 ;
     RECT  14.832 49.747 14.85 50.009 ;
     RECT  19.944 49.621 19.962 50.009 ;
     RECT  32.256 49.981 33.93 50.009 ;
     RECT  22.752 49.981 22.77 50.017 ;
     RECT  35.316 49.001 35.334 50.045 ;
     RECT  7.668 49.621 8.097 50.059 ;
     RECT  22.752 50.017 22.842 50.081 ;
     RECT  32.256 50.009 33.894 50.081 ;
     RECT  6.66 49.855 6.678 50.093 ;
     RECT  2.304 49.919 3.258 50.141 ;
     RECT  22.824 50.081 22.842 50.153 ;
     RECT  2.304 50.141 2.754 50.251 ;
     RECT  4.572 49.739 5.778 50.279 ;
     RECT  32.364 50.081 33.894 50.279 ;
     RECT  2.268 50.251 2.754 50.585 ;
     RECT  32.508 50.279 33.894 50.621 ;
     RECT  5.364 50.279 5.778 50.635 ;
     RECT  18.615 49.739 18.897 50.701 ;
     RECT  7.56 50.059 8.097 50.729 ;
     RECT  34.776 50.245 34.794 50.731 ;
     RECT  3.528 50.701 3.546 50.765 ;
     RECT  4.572 50.279 4.59 50.827 ;
     RECT  18 50.701 18.897 50.855 ;
     RECT  30.852 50.863 30.87 50.899 ;
     RECT  2.304 50.585 2.754 50.923 ;
     RECT  34.74 50.731 34.794 50.923 ;
     RECT  4.5 50.827 4.59 51.005 ;
     RECT  5.364 50.635 5.814 51.089 ;
     RECT  5.364 51.089 5.598 51.125 ;
     RECT  34.74 50.923 35.334 51.197 ;
     RECT  32.508 50.621 33.786 51.331 ;
     RECT  18.252 50.855 18.897 51.367 ;
     RECT  7.812 50.729 8.097 51.395 ;
     RECT  7.815 51.395 8.097 51.403 ;
     RECT  14.868 51.331 14.958 51.431 ;
     RECT  32.364 51.331 33.786 51.431 ;
     RECT  0.108 50.827 0.126 51.437 ;
     RECT  30.78 50.899 30.87 51.439 ;
     RECT  6.804 51.331 6.822 51.475 ;
     RECT  14.868 51.431 14.886 51.475 ;
     RECT  30.78 51.439 31.086 51.475 ;
     RECT  14.832 51.475 14.886 51.476 ;
     RECT  6.732 51.475 6.822 51.499 ;
     RECT  18.252 51.367 19.638 51.503 ;
     RECT  2.304 50.923 2.79 51.511 ;
     RECT  4.176 51.331 4.338 51.511 ;
     RECT  5.364 51.125 5.562 51.511 ;
     RECT  6.732 51.499 6.858 51.511 ;
     RECT  30.78 51.475 31.446 51.511 ;
     RECT  5.256 51.511 5.562 51.629 ;
     RECT  6.336 51.511 6.894 51.629 ;
     RECT  7.815 51.403 8.802 51.629 ;
     RECT  18.252 51.503 18.897 51.629 ;
     RECT  19.62 51.503 19.638 51.629 ;
     RECT  30.78 51.511 31.878 51.629 ;
     RECT  2.304 51.511 3.006 51.643 ;
     RECT  3.744 51.511 4.338 51.643 ;
     RECT  32.652 51.431 33.786 51.643 ;
     RECT  31.86 51.629 31.878 51.665 ;
     RECT  14.832 51.476 14.85 51.701 ;
     RECT  30.78 51.629 30.798 51.737 ;
     RECT  6.804 51.629 6.894 51.809 ;
     RECT  2.304 51.643 4.338 51.899 ;
     RECT  2.304 51.899 3.402 51.935 ;
     RECT  32.652 51.643 34.218 51.971 ;
     RECT  35.316 51.197 35.334 52.075 ;
     RECT  35.28 52.075 35.334 52.169 ;
     RECT  2.304 51.935 2.934 52.277 ;
     RECT  6.84 51.809 6.894 52.285 ;
     RECT  7.815 51.629 8.097 52.285 ;
     RECT  6.84 52.285 8.097 52.313 ;
     RECT  4.248 51.899 4.338 52.411 ;
     RECT  32.652 51.971 33.786 52.411 ;
     RECT  17.1 52.321 17.118 52.439 ;
     RECT  32.04 52.411 33.786 52.547 ;
     RECT  5.256 51.629 5.274 52.555 ;
     RECT  18.615 51.629 18.897 52.555 ;
     RECT  4.248 52.411 4.518 52.681 ;
     RECT  22.824 52.591 22.842 52.681 ;
     RECT  5.256 52.555 5.634 52.699 ;
     RECT  18.615 52.555 19.53 52.709 ;
     RECT  2.304 52.277 2.79 52.745 ;
     RECT  5.256 52.699 5.778 52.745 ;
     RECT  22.716 52.681 22.842 52.745 ;
     RECT  22.716 52.745 22.806 52.781 ;
     RECT  4.176 52.681 4.518 52.795 ;
     RECT  5.256 52.745 5.49 52.795 ;
     RECT  14.832 52.717 14.85 52.817 ;
     RECT  4.176 52.795 5.49 52.825 ;
     RECT  32.508 52.547 33.786 52.825 ;
     RECT  7.128 52.313 8.097 52.889 ;
     RECT  22.788 52.781 22.806 52.889 ;
     RECT  3.528 52.825 5.49 52.979 ;
     RECT  32.508 52.825 33.858 52.979 ;
     RECT  32.796 52.979 33.858 52.987 ;
     RECT  32.796 52.987 34.218 53.015 ;
     RECT  3.528 52.979 4.698 53.249 ;
     RECT  6.948 53.131 6.966 53.249 ;
     RECT  2.304 52.745 2.697 53.401 ;
     RECT  6.768 53.365 6.786 53.405 ;
     RECT  2.268 53.401 2.697 53.453 ;
     RECT  5.472 52.979 5.49 53.519 ;
     RECT  17.784 53.401 17.802 53.519 ;
     RECT  5.58 53.56 5.598 53.671 ;
     RECT  4.5 53.249 4.698 53.789 ;
     RECT  33.336 53.015 34.218 53.789 ;
     RECT  3.528 53.249 3.69 53.825 ;
     RECT  4.5 53.789 4.626 53.861 ;
     RECT  35.316 52.169 35.334 53.899 ;
     RECT  32.508 53.869 32.526 53.941 ;
     RECT  33.336 53.789 33.714 53.941 ;
     RECT  34.74 53.899 35.334 53.969 ;
     RECT  34.776 53.969 35.334 54.103 ;
     RECT  34.776 54.103 35.37 54.173 ;
     RECT  7.815 52.889 8.097 54.175 ;
     RECT  17.1 54.103 17.118 54.203 ;
     RECT  18.615 52.709 18.897 54.211 ;
     RECT  3.42 54.175 3.438 54.329 ;
     RECT  4.32 54.283 4.338 54.329 ;
     RECT  6.552 54.211 6.57 54.329 ;
     RECT  10.908 54.175 10.926 54.329 ;
     RECT  7.308 54.175 8.097 54.331 ;
     RECT  0.54 54.067 0.558 54.365 ;
     RECT  5.58 53.671 5.778 54.365 ;
     RECT  6.912 54.331 8.097 54.409 ;
     RECT  2.304 53.453 2.697 54.481 ;
     RECT  32.508 53.941 33.714 54.481 ;
     RECT  34.776 54.173 35.334 54.605 ;
     RECT  0.108 54.571 0.126 54.701 ;
     RECT  18.615 54.211 19.062 54.715 ;
     RECT  6.912 54.409 8.154 54.751 ;
     RECT  6.912 54.751 8.298 54.869 ;
     RECT  9.072 54.751 9.09 54.869 ;
     RECT  31.356 54.841 31.374 54.877 ;
     RECT  14.832 54.751 14.85 54.941 ;
     RECT  22.716 54.841 22.734 55.021 ;
     RECT  22.716 55.021 22.806 55.049 ;
     RECT  32.148 54.481 33.714 55.111 ;
     RECT  22.788 55.049 22.806 55.139 ;
     RECT  30.924 54.877 31.374 55.139 ;
     RECT  32.148 55.111 33.786 55.139 ;
     RECT  7.632 54.869 8.154 55.277 ;
     RECT  4.392 54.751 4.41 55.291 ;
     RECT  3.96 55.291 4.482 55.381 ;
     RECT  18.615 54.715 19.494 55.381 ;
     RECT  35.316 54.605 35.334 55.409 ;
     RECT  5.76 54.365 5.778 55.453 ;
     RECT  18.615 55.381 19.53 55.481 ;
     RECT  32.364 55.139 33.786 55.483 ;
     RECT  2.304 54.481 3.114 55.489 ;
     RECT  3.924 55.381 4.482 55.489 ;
     RECT  2.304 55.489 4.482 55.561 ;
     RECT  5.472 55.453 5.778 55.561 ;
     RECT  10.8 55.489 10.818 55.589 ;
     RECT  7.632 55.277 8.097 55.613 ;
     RECT  32.364 55.483 34.218 55.651 ;
     RECT  2.304 55.561 4.59 55.679 ;
     RECT  7.704 55.613 8.097 55.679 ;
     RECT  30.78 55.291 30.798 55.679 ;
     RECT  5.472 55.561 6.75 55.687 ;
     RECT  5.472 55.687 6.93 55.715 ;
     RECT  6.732 55.715 6.93 55.787 ;
     RECT  6.84 55.787 6.93 55.823 ;
     RECT  32.364 55.651 34.794 56.021 ;
     RECT  2.304 55.679 4.518 56.101 ;
     RECT  5.472 55.715 5.778 56.101 ;
     RECT  2.268 56.101 4.518 56.141 ;
     RECT  32.364 56.021 33.786 56.191 ;
     RECT  5.4 56.101 5.778 56.219 ;
     RECT  18.615 55.481 19.422 56.219 ;
     RECT  32.292 56.191 33.786 56.219 ;
     RECT  31.5 56.101 31.518 56.255 ;
     RECT  2.304 56.141 4.518 56.489 ;
     RECT  17.676 56.371 17.694 56.489 ;
     RECT  34.74 56.021 34.794 56.489 ;
     RECT  6.84 55.823 6.858 56.569 ;
     RECT  7.815 55.679 8.097 56.569 ;
     RECT  10.8 56.497 10.818 56.669 ;
     RECT  4.5 56.489 4.518 57.001 ;
     RECT  32.292 56.219 33.714 57.001 ;
     RECT  2.304 56.489 3.546 57.029 ;
     RECT  0.108 56.803 0.126 57.101 ;
     RECT  6.84 56.569 8.097 57.109 ;
     RECT  4.5 57.001 4.626 57.173 ;
     RECT  2.304 57.029 2.697 57.259 ;
     RECT  3.528 57.029 3.546 57.299 ;
     RECT  6.84 57.109 8.334 57.341 ;
     RECT  4.5 57.173 4.518 57.379 ;
     RECT  6.84 57.341 6.858 57.379 ;
     RECT  18.615 56.219 18.897 57.415 ;
     RECT  4.428 57.379 4.518 57.451 ;
     RECT  5.76 56.219 5.778 57.451 ;
     RECT  6.804 57.379 6.858 57.451 ;
     RECT  7.815 57.341 8.334 57.451 ;
     RECT  35.316 56.587 35.334 57.541 ;
     RECT  10.8 57.415 10.818 57.569 ;
     RECT  34.776 57.541 35.334 57.581 ;
     RECT  2.268 57.259 2.697 57.605 ;
     RECT  3.924 57.451 4.518 57.641 ;
     RECT  5.76 57.451 6.858 57.685 ;
     RECT  18.432 57.415 18.897 57.685 ;
     RECT  31.788 57.001 33.714 57.721 ;
     RECT  7.815 57.451 8.514 57.839 ;
     RECT  31.5 57.721 33.714 57.839 ;
     RECT  18.396 57.685 18.897 57.883 ;
     RECT  9.324 57.721 9.342 57.911 ;
     RECT  31.68 57.839 33.714 57.919 ;
     RECT  14.868 57.847 14.886 57.947 ;
     RECT  4.5 57.641 4.518 57.991 ;
     RECT  5.256 57.685 6.858 57.991 ;
     RECT  17.856 57.883 18.897 57.991 ;
     RECT  30.78 57.883 30.798 58.019 ;
     RECT  4.5 57.991 6.858 58.109 ;
     RECT  17.856 57.991 18.954 58.109 ;
     RECT  35.316 57.581 35.334 58.117 ;
     RECT  7.815 57.839 8.406 58.157 ;
     RECT  35.316 58.117 35.37 58.205 ;
     RECT  18 58.109 18.897 58.253 ;
     RECT  18.576 58.253 18.897 58.289 ;
     RECT  5.112 58.109 6.858 58.379 ;
     RECT  31.68 57.919 33.786 58.379 ;
     RECT  35.316 58.205 35.334 58.411 ;
     RECT  0.54 58.117 0.558 58.445 ;
     RECT  31.968 58.379 33.786 58.451 ;
     RECT  5.472 58.379 6.858 58.507 ;
     RECT  7.815 58.157 8.097 58.507 ;
     RECT  26.784 58.423 26.802 58.523 ;
     RECT  2.304 57.605 2.697 58.531 ;
     RECT  29.415 2.413 29.697 58.531 ;
     RECT  5.472 58.507 8.097 58.559 ;
     RECT  32.58 58.451 33.786 58.603 ;
     RECT  34.92 58.411 35.334 58.603 ;
     RECT  32.58 58.603 35.334 58.649 ;
     RECT  32.616 58.649 35.334 58.721 ;
     RECT  5.472 58.559 6.894 58.757 ;
     RECT  29.415 58.531 30.222 58.919 ;
     RECT  2.304 58.531 3.114 59.071 ;
     RECT  4.428 59.071 4.446 59.117 ;
     RECT  6.444 58.757 6.894 59.189 ;
     RECT  14.868 59.035 14.886 59.189 ;
     RECT  7.815 58.559 8.097 59.275 ;
     RECT  3.996 59.341 4.122 59.405 ;
     RECT  20.016 59.341 20.034 59.431 ;
     RECT  6.804 59.189 6.894 59.459 ;
     RECT  9.288 59.341 9.306 59.459 ;
     RECT  17.676 59.197 17.694 59.459 ;
     RECT  20.016 59.431 20.178 59.459 ;
     RECT  7.815 59.275 8.37 59.495 ;
     RECT  34.776 58.721 35.334 59.503 ;
     RECT  6.876 59.459 6.894 59.567 ;
     RECT  22.824 59.467 22.842 59.567 ;
     RECT  31.356 59.431 31.374 59.575 ;
     RECT  34.74 59.503 35.334 59.597 ;
     RECT  31.356 59.575 31.734 59.611 ;
     RECT  32.616 58.721 33.786 59.611 ;
     RECT  3.996 59.405 4.086 59.639 ;
     RECT  31.356 59.611 33.786 59.639 ;
     RECT  5.472 58.757 5.598 59.701 ;
     RECT  26.784 59.611 26.802 59.729 ;
     RECT  31.356 59.639 33.714 59.729 ;
     RECT  29.415 58.919 29.697 59.737 ;
     RECT  20.16 59.459 20.178 59.765 ;
     RECT  32.436 59.729 33.714 59.765 ;
     RECT  2.304 59.071 3.15 59.881 ;
     RECT  4.896 59.701 5.598 59.881 ;
     RECT  18.615 58.289 18.897 59.881 ;
     RECT  4.896 59.881 5.778 59.909 ;
     RECT  2.304 59.881 3.294 59.999 ;
     RECT  17.892 59.881 18.897 59.999 ;
     RECT  29.088 59.737 29.697 59.999 ;
     RECT  2.304 59.999 3.114 60.035 ;
     RECT  32.544 59.765 33.714 60.035 ;
     RECT  4.896 59.909 4.914 60.221 ;
     RECT  5.724 59.909 5.778 60.241 ;
     RECT  4.032 59.639 4.086 60.269 ;
     RECT  4.86 60.379 4.878 60.427 ;
     RECT  4.5 60.427 4.878 60.539 ;
     RECT  19.728 60.421 19.746 60.539 ;
     RECT  30.924 60.421 30.942 60.539 ;
     RECT  32.796 60.035 33.714 60.655 ;
     RECT  4.5 60.539 4.698 60.809 ;
     RECT  18 59.999 18.897 60.809 ;
     RECT  31.392 60.691 31.41 60.809 ;
     RECT  32.796 60.655 33.786 60.817 ;
     RECT  2.304 60.035 2.934 60.907 ;
     RECT  26.784 60.817 26.802 60.953 ;
     RECT  5.724 60.241 6.426 60.989 ;
     RECT  2.304 60.907 3.33 61.045 ;
     RECT  4.5 60.809 4.626 61.115 ;
     RECT  35.316 59.597 35.334 61.147 ;
     RECT  2.304 61.045 3.582 61.231 ;
     RECT  6.84 61.123 6.858 61.231 ;
     RECT  32.436 60.817 33.786 61.231 ;
     RECT  26.856 61.087 26.874 61.259 ;
     RECT  32.22 61.231 33.786 61.259 ;
     RECT  6.84 61.231 6.93 61.339 ;
     RECT  4.608 61.115 4.626 61.349 ;
     RECT  5.724 60.989 5.886 61.349 ;
     RECT  20.016 61.231 20.034 61.349 ;
     RECT  32.22 61.259 33.678 61.349 ;
     RECT  34.74 61.147 35.334 61.349 ;
     RECT  17.676 60.961 17.766 61.385 ;
     RECT  32.76 61.349 33.678 61.385 ;
     RECT  6.84 61.339 7.074 61.501 ;
     RECT  7.815 59.495 8.097 61.501 ;
     RECT  5.724 61.349 5.778 61.531 ;
     RECT  5.508 61.531 5.778 61.579 ;
     RECT  2.304 61.231 3.726 61.619 ;
     RECT  5.328 61.579 5.778 61.655 ;
     RECT  6.84 61.501 8.097 61.735 ;
     RECT  18.615 60.809 18.897 61.735 ;
     RECT  2.304 61.619 3.474 61.763 ;
     RECT  18.615 61.735 19.062 61.861 ;
     RECT  6.696 61.735 8.097 61.867 ;
     RECT  9.072 61.771 9.09 61.889 ;
     RECT  17.352 61.771 17.478 61.889 ;
     RECT  6.588 61.867 8.097 61.897 ;
     RECT  5.76 61.655 5.778 61.925 ;
     RECT  6.588 61.897 8.154 61.949 ;
     RECT  33.084 61.385 33.678 62.005 ;
     RECT  10.836 61.969 10.854 62.069 ;
     RECT  22.788 61.897 22.806 62.069 ;
     RECT  6.588 61.949 7.002 62.155 ;
     RECT  6.408 62.155 7.002 62.195 ;
     RECT  18.615 61.861 19.782 62.195 ;
     RECT  17.46 61.889 17.478 62.231 ;
     RECT  31.788 61.771 31.806 62.311 ;
     RECT  33.084 62.005 33.786 62.311 ;
     RECT  20.16 62.311 20.178 62.429 ;
     RECT  31.788 62.311 34.218 62.429 ;
     RECT  4.536 61.861 4.554 62.509 ;
     RECT  18.615 62.195 19.206 62.509 ;
     RECT  30.852 62.167 30.87 62.509 ;
     RECT  32.364 62.429 34.218 62.525 ;
     RECT  3.78 62.509 3.798 62.581 ;
     RECT  4.536 62.509 4.662 62.581 ;
     RECT  5.472 62.545 5.49 62.581 ;
     RECT  30.78 62.509 31.446 62.609 ;
     RECT  3.78 62.581 5.49 62.699 ;
     RECT  6.84 62.195 7.002 62.699 ;
     RECT  7.776 61.949 8.097 62.699 ;
     RECT  18 62.509 19.206 62.699 ;
     RECT  30.78 62.609 30.798 62.699 ;
     RECT  32.364 62.525 33.786 62.735 ;
     RECT  36.18 62.671 36.198 62.765 ;
     RECT  2.304 61.763 2.97 62.851 ;
     RECT  3.78 62.699 5.346 62.851 ;
     RECT  2.304 62.851 5.346 62.969 ;
     RECT  6.84 62.699 6.858 63.121 ;
     RECT  35.28 61.349 35.334 63.121 ;
     RECT  2.304 62.969 3.222 63.163 ;
     RECT  34.776 63.121 35.334 63.197 ;
     RECT  2.268 63.163 3.222 63.275 ;
     RECT  7.815 62.699 8.097 63.355 ;
     RECT  32.544 62.735 33.786 63.355 ;
     RECT  0.54 63.121 0.558 63.437 ;
     RECT  29.415 59.999 29.697 63.481 ;
     RECT  19.836 63.391 19.854 63.509 ;
     RECT  32.544 63.355 33.822 63.509 ;
     RECT  2.268 63.275 2.862 63.545 ;
     RECT  6.804 63.121 6.858 63.547 ;
     RECT  7.815 63.355 8.154 63.547 ;
     RECT  18.615 62.699 18.897 63.625 ;
     RECT  32.544 63.509 33.714 63.625 ;
     RECT  6.804 63.547 6.894 63.643 ;
     RECT  6.156 63.643 6.894 63.661 ;
     RECT  7.815 63.547 8.298 63.661 ;
     RECT  3.96 62.969 5.346 63.751 ;
     RECT  32.472 63.625 33.714 63.751 ;
     RECT  6.156 63.661 8.298 63.779 ;
     RECT  10.836 63.661 10.926 63.779 ;
     RECT  20.016 63.661 20.034 63.787 ;
     RECT  7.815 63.779 8.154 63.821 ;
     RECT  32.364 63.751 33.714 63.823 ;
     RECT  3.672 63.751 5.346 63.835 ;
     RECT  6.156 63.779 7.074 63.835 ;
     RECT  10.908 63.779 10.926 63.851 ;
     RECT  22.788 63.751 22.806 63.851 ;
     RECT  0.108 63.823 0.126 63.869 ;
     RECT  3.672 63.835 7.074 63.869 ;
     RECT  20.016 63.787 20.178 63.887 ;
     RECT  3.96 63.869 7.074 64.049 ;
     RECT  29.088 63.481 29.697 64.049 ;
     RECT  35.28 63.197 35.334 64.057 ;
     RECT  4.104 64.049 7.074 64.085 ;
     RECT  6.372 64.085 7.074 64.157 ;
     RECT  2.304 63.545 2.862 64.315 ;
     RECT  32.292 63.823 33.714 64.315 ;
     RECT  34.776 64.057 35.334 64.315 ;
     RECT  32.292 64.315 35.334 64.363 ;
     RECT  32.292 64.363 35.37 64.435 ;
     RECT  18.54 63.625 18.897 64.471 ;
     RECT  31.788 64.435 35.37 64.561 ;
     RECT  4.104 64.085 5.634 64.589 ;
     RECT  18.54 64.471 19.494 64.589 ;
     RECT  31.788 64.561 35.406 64.589 ;
     RECT  2.304 64.315 2.97 64.625 ;
     RECT  32.544 64.589 35.406 64.661 ;
     RECT  6.84 64.157 7.074 64.669 ;
     RECT  7.815 63.821 8.097 64.669 ;
     RECT  6.84 64.669 8.097 64.741 ;
     RECT  18.54 64.589 18.897 64.741 ;
     RECT  4.104 64.589 5.094 64.769 ;
     RECT  2.304 64.625 2.79 64.781 ;
     RECT  6.84 64.741 8.298 64.781 ;
     RECT  34.776 64.661 35.406 64.781 ;
     RECT  6.912 64.781 8.298 64.859 ;
     RECT  32.544 64.661 33.93 64.859 ;
     RECT  4.104 64.769 4.842 64.867 ;
     RECT  2.376 64.781 2.79 64.895 ;
     RECT  4.068 64.867 4.842 65.011 ;
     RECT  0.108 64.867 0.126 65.021 ;
     RECT  3.996 65.011 4.842 65.129 ;
     RECT  35.316 64.781 35.406 65.399 ;
     RECT  18.036 64.741 18.897 65.407 ;
     RECT  2.415 64.895 2.79 65.435 ;
     RECT  35.352 65.399 35.406 65.453 ;
     RECT  3.996 65.129 4.806 65.515 ;
     RECT  32.544 64.859 33.786 65.551 ;
     RECT  18.036 65.407 19.242 65.579 ;
     RECT  32.22 65.551 33.786 65.659 ;
     RECT  3.708 65.515 4.806 65.669 ;
     RECT  32.22 65.659 34.218 65.669 ;
     RECT  18.615 65.579 19.242 65.677 ;
     RECT  18.615 65.677 19.314 65.849 ;
     RECT  2.415 65.435 2.697 65.899 ;
     RECT  35.352 65.453 35.37 65.933 ;
     RECT  7.092 64.859 8.097 65.947 ;
     RECT  6.768 65.947 8.097 65.975 ;
     RECT  5.76 65.785 5.85 66.245 ;
     RECT  30.852 66.253 30.87 66.353 ;
     RECT  18.615 65.849 18.897 66.361 ;
     RECT  35.316 66.139 35.334 66.379 ;
     RECT  9.108 65.749 9.126 66.389 ;
     RECT  3.996 65.669 4.806 66.451 ;
     RECT  35.28 66.379 35.334 66.479 ;
     RECT  32.328 65.669 34.218 66.605 ;
     RECT  18.216 66.361 18.897 66.631 ;
     RECT  32.328 66.605 33.822 66.631 ;
     RECT  18.108 66.631 18.897 66.749 ;
     RECT  32.22 66.631 33.822 66.749 ;
     RECT  3.996 66.451 5.13 66.829 ;
     RECT  32.256 66.749 33.822 66.845 ;
     RECT  2.304 65.899 2.697 66.901 ;
     RECT  3.888 66.829 5.13 66.901 ;
     RECT  3.528 66.901 5.13 66.929 ;
     RECT  35.28 66.479 35.298 66.991 ;
     RECT  17.856 66.901 17.874 67.019 ;
     RECT  32.256 66.845 33.786 67.019 ;
     RECT  2.304 66.901 2.79 67.099 ;
     RECT  3.528 66.929 4.302 67.099 ;
     RECT  0.108 67.003 0.126 67.132 ;
     RECT  0.108 67.132 0.162 67.133 ;
     RECT  6.768 65.975 6.786 67.171 ;
     RECT  5.04 66.929 5.13 67.195 ;
     RECT  5.904 66.325 5.922 67.195 ;
     RECT  14.832 67.027 14.85 67.199 ;
     RECT  6.768 67.171 6.858 67.229 ;
     RECT  7.815 65.975 8.097 67.243 ;
     RECT  34.776 66.991 35.298 67.243 ;
     RECT  0.144 67.133 0.162 67.277 ;
     RECT  2.304 67.099 4.302 67.559 ;
     RECT  5.04 67.195 5.922 67.559 ;
     RECT  18.615 66.749 18.897 67.675 ;
     RECT  32.256 67.019 32.922 67.675 ;
     RECT  18.615 67.675 19.494 67.711 ;
     RECT  32.076 67.675 32.922 67.711 ;
     RECT  34.776 67.243 35.334 67.757 ;
     RECT  3.96 67.559 4.302 67.771 ;
     RECT  5.04 67.559 5.778 67.771 ;
     RECT  35.316 67.757 35.334 67.801 ;
     RECT  3.96 67.771 5.778 67.805 ;
     RECT  3.96 67.805 5.634 67.829 ;
     RECT  7.776 67.243 8.097 67.829 ;
     RECT  8.82 67.711 8.838 67.829 ;
     RECT  14.868 67.711 14.886 67.829 ;
     RECT  18.615 67.711 19.566 67.829 ;
     RECT  31.356 67.711 32.922 67.945 ;
     RECT  33.696 67.019 33.786 67.945 ;
     RECT  31.356 67.945 33.786 67.981 ;
     RECT  18.615 67.829 19.278 68.009 ;
     RECT  5.616 67.829 5.634 68.099 ;
     RECT  30.78 67.981 33.786 68.099 ;
     RECT  3.96 67.829 4.842 68.135 ;
     RECT  31.5 68.099 33.786 68.171 ;
     RECT  6.768 67.229 6.786 68.251 ;
     RECT  2.304 67.559 3.222 68.369 ;
     RECT  6.768 68.251 6.858 68.369 ;
     RECT  18.615 68.009 19.206 68.369 ;
     RECT  35.316 67.801 35.37 68.429 ;
     RECT  4.284 68.135 4.842 68.639 ;
     RECT  17.784 68.521 17.802 68.639 ;
     RECT  31.5 68.171 31.878 68.711 ;
     RECT  35.316 68.429 35.334 68.791 ;
     RECT  4.284 68.639 4.698 68.881 ;
     RECT  34.776 68.791 35.334 68.909 ;
     RECT  32.724 68.171 33.714 68.917 ;
     RECT  32.148 68.917 33.714 69.025 ;
     RECT  4.212 68.881 4.698 69.061 ;
     RECT  6.768 68.369 6.786 69.061 ;
     RECT  32.148 69.025 33.822 69.179 ;
     RECT  31.212 69.151 31.23 69.251 ;
     RECT  6.12 69.061 6.786 69.295 ;
     RECT  32.58 69.179 33.822 69.331 ;
     RECT  2.304 68.369 3.078 69.421 ;
     RECT  4.176 69.061 4.698 69.421 ;
     RECT  5.904 69.295 6.786 69.449 ;
     RECT  20.34 69.295 20.358 69.449 ;
     RECT  17.568 69.493 17.586 69.601 ;
     RECT  2.304 69.421 4.698 69.719 ;
     RECT  17.568 69.601 17.838 69.719 ;
     RECT  6.66 69.449 6.786 69.763 ;
     RECT  7.815 67.829 8.097 69.763 ;
     RECT  6.66 69.763 6.966 69.835 ;
     RECT  7.815 69.763 8.586 69.835 ;
     RECT  32.58 69.331 33.93 69.835 ;
     RECT  5.868 69.565 5.886 69.871 ;
     RECT  6.66 69.835 8.586 69.899 ;
     RECT  14.832 69.691 14.85 69.899 ;
     RECT  34.776 68.909 34.83 69.931 ;
     RECT  32.58 69.835 34.002 69.961 ;
     RECT  6.66 69.899 8.097 69.989 ;
     RECT  32.364 69.961 34.002 69.989 ;
     RECT  3.888 69.719 4.698 70.103 ;
     RECT  5.796 69.871 5.886 70.103 ;
     RECT  6.768 69.989 8.097 70.109 ;
     RECT  17.568 69.719 17.586 70.259 ;
     RECT  2.304 69.719 3.006 70.367 ;
     RECT  2.34 70.367 3.006 70.403 ;
     RECT  6.804 70.109 8.097 70.403 ;
     RECT  3.888 70.103 5.886 70.529 ;
     RECT  20.088 70.411 20.106 70.529 ;
     RECT  14.868 70.267 14.886 70.601 ;
     RECT  3.888 70.529 4.986 70.645 ;
     RECT  5.868 70.529 5.886 70.645 ;
     RECT  34.776 69.931 35.334 70.685 ;
     RECT  32.364 69.989 33.786 70.771 ;
     RECT  28.008 70.573 28.026 70.799 ;
     RECT  32.328 70.771 33.786 70.799 ;
     RECT  5.868 70.645 6.03 70.835 ;
     RECT  26.784 70.771 26.802 70.871 ;
     RECT  6.804 70.403 6.894 70.943 ;
     RECT  3.852 70.645 4.986 71.069 ;
     RECT  6.012 70.835 6.03 71.069 ;
     RECT  32.328 70.799 33.39 71.185 ;
     RECT  7.815 70.403 8.097 71.311 ;
     RECT  18.615 68.369 18.897 71.311 ;
     RECT  31.968 71.185 33.39 71.339 ;
     RECT  35.28 70.685 35.334 71.339 ;
     RECT  6.624 71.275 6.642 71.375 ;
     RECT  22.788 70.573 22.806 71.411 ;
     RECT  18.615 71.311 18.954 71.419 ;
     RECT  3.852 71.069 4.878 71.491 ;
     RECT  7.596 71.311 8.097 71.519 ;
     RECT  2.34 70.403 2.862 71.563 ;
     RECT  18.615 71.419 18.99 71.581 ;
     RECT  32.472 71.339 33.39 71.609 ;
     RECT  29.415 64.049 29.697 71.617 ;
     RECT  32.508 71.609 33.39 71.681 ;
     RECT  32.544 71.681 33.39 71.725 ;
     RECT  34.2 71.371 34.218 71.725 ;
     RECT  3.744 71.491 4.878 71.803 ;
     RECT  29.088 71.617 29.697 71.879 ;
     RECT  14.832 71.419 14.85 71.959 ;
     RECT  3.744 71.803 4.914 71.995 ;
     RECT  3.744 71.995 5.346 72.031 ;
     RECT  14.832 71.959 14.886 72.031 ;
     RECT  3.744 72.031 5.85 72.121 ;
     RECT  3.744 72.121 6.246 72.149 ;
     RECT  14.832 72.031 14.958 72.149 ;
     RECT  14.832 72.149 14.886 72.185 ;
     RECT  2.304 71.563 2.862 72.235 ;
     RECT  3.744 72.149 5.49 72.235 ;
     RECT  7.668 71.519 8.097 72.301 ;
     RECT  18 71.581 18.99 72.301 ;
     RECT  14.832 72.185 14.85 72.329 ;
     RECT  6.228 72.149 6.246 72.419 ;
     RECT  0.108 72.265 0.126 72.461 ;
     RECT  32.544 71.725 34.218 72.571 ;
     RECT  2.304 72.235 5.49 72.599 ;
     RECT  32.22 72.571 34.218 72.599 ;
     RECT  35.316 71.339 35.334 72.715 ;
     RECT  2.304 72.599 4.698 72.725 ;
     RECT  18 72.301 19.386 72.805 ;
     RECT  7.452 72.301 8.097 72.841 ;
     RECT  32.22 72.599 33.534 72.841 ;
     RECT  5.472 72.599 5.49 72.907 ;
     RECT  4.536 72.725 4.698 72.959 ;
     RECT  6.804 72.841 8.298 72.959 ;
     RECT  9.072 72.841 9.09 72.959 ;
     RECT  17.64 72.805 19.386 72.959 ;
     RECT  4.536 72.959 4.59 73.037 ;
     RECT  7.815 72.959 8.298 73.111 ;
     RECT  17.676 72.959 19.386 73.111 ;
     RECT  35.28 72.715 35.334 73.147 ;
     RECT  34.74 73.147 35.334 73.229 ;
     RECT  7.815 73.111 8.658 73.265 ;
     RECT  4.572 73.037 4.59 73.373 ;
     RECT  5.472 72.907 5.706 73.381 ;
     RECT  6.804 72.959 7.074 73.381 ;
     RECT  6.552 73.381 7.074 73.499 ;
     RECT  17.676 73.111 19.422 73.499 ;
     RECT  31.932 72.841 33.534 73.499 ;
     RECT  32.544 73.499 33.534 73.507 ;
     RECT  6.804 73.499 7.074 73.535 ;
     RECT  14.832 73.309 14.85 73.535 ;
     RECT  18.504 73.499 19.422 73.535 ;
     RECT  18.615 73.535 19.422 73.579 ;
     RECT  32.544 73.507 33.714 73.651 ;
     RECT  18.615 73.579 19.566 73.679 ;
     RECT  34.776 73.229 35.334 73.679 ;
     RECT  7.815 73.265 8.334 73.723 ;
     RECT  7.596 73.723 8.334 73.769 ;
     RECT  18.615 73.679 19.494 73.769 ;
     RECT  31.788 73.651 31.806 73.769 ;
     RECT  7.815 73.769 8.334 73.805 ;
     RECT  0.54 73.507 0.558 73.853 ;
     RECT  5.472 73.381 5.778 73.921 ;
     RECT  10.8 73.777 10.818 73.949 ;
     RECT  2.304 72.725 3.798 74.039 ;
     RECT  6.804 73.535 6.822 74.039 ;
     RECT  30.78 73.777 30.798 74.039 ;
     RECT  5.148 73.921 5.778 74.075 ;
     RECT  34.776 73.679 34.794 74.093 ;
     RECT  32.544 73.651 33.93 74.299 ;
     RECT  18.615 73.769 19.278 74.309 ;
     RECT  4.536 74.443 4.662 74.461 ;
     RECT  32.544 74.299 34.218 74.461 ;
     RECT  3.996 74.461 4.662 74.579 ;
     RECT  18.615 74.309 18.99 74.579 ;
     RECT  32.364 74.461 34.218 74.579 ;
     RECT  0.108 74.047 0.126 74.621 ;
     RECT  3.996 74.579 4.014 74.651 ;
     RECT  32.832 74.579 34.218 74.651 ;
     RECT  7.815 73.805 8.097 74.683 ;
     RECT  5.472 74.075 5.778 74.731 ;
     RECT  18.615 74.579 18.897 74.731 ;
     RECT  31.86 74.623 32.094 74.821 ;
     RECT  18.324 74.731 18.897 74.849 ;
     RECT  2.304 74.039 3.258 74.885 ;
     RECT  7.815 74.683 8.37 74.885 ;
     RECT  29.415 71.879 29.697 74.893 ;
     RECT  14.832 74.857 14.85 74.957 ;
     RECT  18.504 74.849 18.897 74.957 ;
     RECT  35.316 74.731 35.334 74.971 ;
     RECT  5.472 74.731 6.39 75.001 ;
     RECT  34.74 74.971 35.334 75.029 ;
     RECT  20.052 75.001 20.07 75.119 ;
     RECT  31.356 74.821 32.094 75.119 ;
     RECT  4.932 75.001 6.39 75.155 ;
     RECT  34.776 75.029 35.334 75.197 ;
     RECT  5.508 75.155 6.39 75.271 ;
     RECT  31.716 75.119 32.094 75.361 ;
     RECT  32.832 74.651 33.822 75.361 ;
     RECT  3.78 75.001 3.798 75.505 ;
     RECT  3.78 75.505 3.87 75.541 ;
     RECT  31.716 75.361 33.822 75.631 ;
     RECT  29.088 74.893 29.697 75.659 ;
     RECT  31.716 75.631 33.93 75.677 ;
     RECT  2.304 74.885 2.79 75.739 ;
     RECT  3.78 75.541 4.698 75.739 ;
     RECT  30.78 75.667 30.798 75.767 ;
     RECT  0.108 75.643 0.126 75.773 ;
     RECT  18.615 74.957 18.897 75.811 ;
     RECT  31.716 75.677 33.786 75.929 ;
     RECT  2.304 75.739 4.698 76.009 ;
     RECT  5.508 75.271 6.822 76.009 ;
     RECT  35.316 75.197 35.334 76.075 ;
     RECT  2.304 76.009 6.822 76.081 ;
     RECT  18.615 75.811 18.99 76.081 ;
     RECT  17.352 75.811 17.37 76.199 ;
     RECT  18.432 76.081 18.99 76.199 ;
     RECT  31.788 75.929 33.714 76.199 ;
     RECT  2.304 76.081 6.966 76.235 ;
     RECT  35.28 76.075 35.334 76.279 ;
     RECT  14.832 76.207 14.85 76.307 ;
     RECT  35.28 76.279 35.37 76.315 ;
     RECT  2.415 76.235 6.966 76.343 ;
     RECT  4.176 76.343 6.966 76.379 ;
     RECT  7.815 74.885 8.097 76.459 ;
     RECT  4.176 76.379 6.93 76.469 ;
     RECT  18.615 76.199 18.99 76.477 ;
     RECT  6.696 76.469 6.93 76.505 ;
     RECT  7.815 76.459 8.298 76.505 ;
     RECT  4.176 76.469 5.778 76.577 ;
     RECT  7.815 76.505 8.097 76.585 ;
     RECT  10.8 76.549 10.818 76.649 ;
     RECT  17.46 76.351 17.478 76.649 ;
     RECT  7.776 76.585 8.097 76.739 ;
     RECT  18.615 76.477 19.602 76.739 ;
     RECT  31.788 76.199 31.806 76.739 ;
     RECT  4.176 76.577 5.706 76.847 ;
     RECT  6.768 76.505 6.93 76.883 ;
     RECT  30.78 76.783 30.798 76.883 ;
     RECT  32.544 76.199 33.714 76.891 ;
     RECT  2.415 76.343 3.438 76.987 ;
     RECT  35.244 76.315 35.37 76.987 ;
     RECT  4.176 76.847 5.022 77.009 ;
     RECT  4.176 77.009 4.194 77.045 ;
     RECT  2.304 76.987 3.438 77.161 ;
     RECT  32.544 76.891 34.002 77.161 ;
     RECT  34.74 76.987 35.37 77.189 ;
     RECT  2.268 77.161 3.438 77.261 ;
     RECT  18.615 76.739 18.897 77.287 ;
     RECT  2.304 77.261 3.438 77.359 ;
     RECT  5.832 77.419 5.85 77.431 ;
     RECT  6.768 76.883 6.858 77.431 ;
     RECT  5.832 77.431 6.858 77.549 ;
     RECT  5.004 77.009 5.022 77.585 ;
     RECT  2.304 77.359 4.014 77.621 ;
     RECT  5.832 77.549 5.994 77.657 ;
     RECT  32.292 77.161 34.002 77.665 ;
     RECT  31.932 77.665 34.002 77.693 ;
     RECT  6.768 77.549 6.858 77.701 ;
     RECT  7.815 76.739 8.097 77.701 ;
     RECT  19.656 76.891 19.674 77.729 ;
     RECT  6.768 77.701 8.097 77.819 ;
     RECT  26.856 77.701 26.874 77.855 ;
     RECT  6.768 77.819 6.93 77.999 ;
     RECT  5.832 77.657 5.922 78.061 ;
     RECT  2.304 77.621 3.762 78.125 ;
     RECT  34.776 77.189 35.37 78.173 ;
     RECT  18 77.287 18.897 78.241 ;
     RECT  31.932 77.693 33.786 78.241 ;
     RECT  2.304 78.125 3.186 78.331 ;
     RECT  31.716 78.241 33.786 78.359 ;
     RECT  17.892 78.241 18.897 78.467 ;
     RECT  5.328 78.061 5.922 78.503 ;
     RECT  4.572 78.043 4.59 78.511 ;
     RECT  5.328 78.503 5.778 78.511 ;
     RECT  6.768 77.999 6.786 78.511 ;
     RECT  19.872 78.439 19.89 78.511 ;
     RECT  30.78 77.791 30.798 78.539 ;
     RECT  6.732 78.511 6.786 78.601 ;
     RECT  19.8 78.511 19.89 78.629 ;
     RECT  6.588 78.601 6.786 78.653 ;
     RECT  2.268 78.331 3.186 78.665 ;
     RECT  32.436 78.359 33.786 78.665 ;
     RECT  34.776 78.173 35.334 78.811 ;
     RECT  18.288 78.467 18.897 78.899 ;
     RECT  34.74 78.811 35.334 78.899 ;
     RECT  0.108 78.907 0.126 79.051 ;
     RECT  2.304 78.665 3.186 79.051 ;
     RECT  4.068 78.511 5.778 79.051 ;
     RECT  32.472 78.665 33.786 79.051 ;
     RECT  19.908 79.051 19.998 79.169 ;
     RECT  32.472 79.051 33.822 79.205 ;
     RECT  35.244 78.899 35.334 79.213 ;
     RECT  0.108 79.051 0.162 79.229 ;
     RECT  20.052 79.177 20.07 79.277 ;
     RECT  2.304 79.051 3.258 79.321 ;
     RECT  4.032 79.051 5.778 79.321 ;
     RECT  7.815 77.819 8.097 79.435 ;
     RECT  17.496 78.637 17.514 79.439 ;
     RECT  7.308 79.435 8.097 79.447 ;
     RECT  32.472 79.205 33.786 79.447 ;
     RECT  35.244 79.213 35.37 79.517 ;
     RECT  32.436 79.447 33.786 79.555 ;
     RECT  32.364 79.555 33.786 79.591 ;
     RECT  31.932 79.591 33.786 79.709 ;
     RECT  32.364 79.709 33.786 79.745 ;
     RECT  2.304 79.321 5.778 79.781 ;
     RECT  7.056 79.447 8.097 79.951 ;
     RECT  32.436 79.745 33.786 79.951 ;
     RECT  35.244 79.517 35.334 79.951 ;
     RECT  32.436 79.951 33.93 79.979 ;
     RECT  7.056 79.951 8.154 79.987 ;
     RECT  32.544 79.979 33.93 80.051 ;
     RECT  6.84 79.987 8.154 80.131 ;
     RECT  18.615 78.899 18.897 80.131 ;
     RECT  6.84 80.131 8.226 80.249 ;
     RECT  14.832 79.987 14.85 80.249 ;
     RECT  18.615 80.131 19.386 80.249 ;
     RECT  22.788 80.221 22.806 80.257 ;
     RECT  0.108 79.229 0.126 80.285 ;
     RECT  22.716 80.257 22.806 80.321 ;
     RECT  34.776 79.951 35.334 80.329 ;
     RECT  7.815 80.249 8.226 80.357 ;
     RECT  22.716 80.321 22.734 80.357 ;
     RECT  2.304 79.781 2.862 80.555 ;
     RECT  3.636 79.781 5.778 80.599 ;
     RECT  3.636 80.599 5.814 80.635 ;
     RECT  6.84 80.249 6.858 80.635 ;
     RECT  18.615 80.249 18.897 80.671 ;
     RECT  32.544 80.051 33.786 80.761 ;
     RECT  3.636 80.635 6.858 80.797 ;
     RECT  32.508 80.761 33.786 80.861 ;
     RECT  3.456 80.797 6.858 80.933 ;
     RECT  18.576 80.671 18.897 80.969 ;
     RECT  6.66 80.933 6.858 81.031 ;
     RECT  6.66 81.031 7.074 81.059 ;
     RECT  17.28 80.941 17.298 81.059 ;
     RECT  3.456 80.933 5.814 81.095 ;
     RECT  34.776 80.329 35.37 81.293 ;
     RECT  3.456 81.095 5.274 81.329 ;
     RECT  19.62 81.211 19.638 81.329 ;
     RECT  2.304 80.555 2.697 81.355 ;
     RECT  3.456 81.329 5.202 81.355 ;
     RECT  0.108 81.259 0.126 81.389 ;
     RECT  31.68 80.941 31.698 81.715 ;
     RECT  32.544 80.861 33.786 81.715 ;
     RECT  18.615 80.969 18.897 81.751 ;
     RECT  31.68 81.715 33.786 81.751 ;
     RECT  18.615 81.751 19.53 81.869 ;
     RECT  31.464 81.751 33.786 81.869 ;
     RECT  6.732 81.059 7.074 81.877 ;
     RECT  2.304 81.355 5.202 81.905 ;
     RECT  31.932 81.869 33.786 81.905 ;
     RECT  34.776 81.293 35.334 82.049 ;
     RECT  6.588 81.877 7.074 82.111 ;
     RECT  7.815 80.357 8.097 82.111 ;
     RECT  6.588 82.111 8.097 82.139 ;
     RECT  7.056 82.139 8.097 82.183 ;
     RECT  0.54 81.751 0.558 82.205 ;
     RECT  7.056 82.183 8.154 82.291 ;
     RECT  14.904 82.147 14.922 82.291 ;
     RECT  14.832 82.291 14.922 82.319 ;
     RECT  7.056 82.291 8.226 82.409 ;
     RECT  3.744 81.905 5.202 82.445 ;
     RECT  7.056 82.409 8.097 82.445 ;
     RECT  3.744 82.445 3.762 82.517 ;
     RECT  4.608 82.445 5.202 82.561 ;
     RECT  14.832 82.319 14.85 82.589 ;
     RECT  7.056 82.445 7.074 82.637 ;
     RECT  17.1 82.381 17.118 82.679 ;
     RECT  30.78 82.687 30.798 82.795 ;
     RECT  30.78 82.795 30.834 82.859 ;
     RECT  36.18 82.699 36.198 82.859 ;
     RECT  34.776 82.049 34.794 82.891 ;
     RECT  3.672 82.831 3.69 82.985 ;
     RECT  34.74 82.891 34.794 83.029 ;
     RECT  4.608 82.561 5.274 83.065 ;
     RECT  18.615 81.869 18.897 83.065 ;
     RECT  6.228 82.417 6.246 83.101 ;
     RECT  30.816 82.859 30.834 83.101 ;
     RECT  4.608 83.065 5.49 83.179 ;
     RECT  6.228 83.101 7.038 83.179 ;
     RECT  18.615 83.065 19.062 83.179 ;
     RECT  19.836 83.101 19.962 83.179 ;
     RECT  4.5 83.179 7.038 83.219 ;
     RECT  18.615 83.179 20.034 83.219 ;
     RECT  30.816 83.101 30.906 83.219 ;
     RECT  31.932 81.905 33.75 83.263 ;
     RECT  4.5 83.219 6.102 83.371 ;
     RECT  18.615 83.219 18.897 83.371 ;
     RECT  31.752 83.263 33.75 83.371 ;
     RECT  2.304 81.905 2.862 83.461 ;
     RECT  6.876 83.219 7.038 83.489 ;
     RECT  0.108 83.065 0.126 83.533 ;
     RECT  2.304 83.461 2.934 83.533 ;
     RECT  0.108 83.533 0.522 83.597 ;
     RECT  7.815 82.445 8.097 83.641 ;
     RECT  31.284 83.371 34.002 83.641 ;
     RECT  34.74 83.029 35.37 83.641 ;
     RECT  2.304 83.533 3.402 83.731 ;
     RECT  4.14 83.371 6.102 83.731 ;
     RECT  29.415 75.659 29.697 83.731 ;
     RECT  31.284 83.641 35.37 83.731 ;
     RECT  7.164 83.641 8.097 83.759 ;
     RECT  18.216 83.371 18.897 83.759 ;
     RECT  31.284 83.731 35.406 83.759 ;
     RECT  0.504 83.597 0.522 83.767 ;
     RECT  31.32 83.759 35.406 83.767 ;
     RECT  2.304 83.731 6.102 83.795 ;
     RECT  18.432 83.759 18.897 84.001 ;
     RECT  0.504 83.767 0.558 84.037 ;
     RECT  18.432 84.001 18.954 84.073 ;
     RECT  22.716 84.181 22.806 84.299 ;
     RECT  2.304 83.795 5.994 84.307 ;
     RECT  0.504 84.037 0.594 84.343 ;
     RECT  1.692 84.307 5.994 84.343 ;
     RECT  14.868 84.271 14.886 84.371 ;
     RECT  22.716 84.299 22.734 84.371 ;
     RECT  0.504 84.343 5.994 84.613 ;
     RECT  7.815 83.759 8.097 84.613 ;
     RECT  18.432 84.073 19.35 84.721 ;
     RECT  31.32 83.767 35.478 84.811 ;
     RECT  0.504 84.613 6.57 84.911 ;
     RECT  8.964 84.721 8.982 84.911 ;
     RECT  7.815 84.613 8.19 84.991 ;
     RECT  29.415 83.731 30.222 85.109 ;
     RECT  0.504 84.911 5.886 85.117 ;
     RECT  6.696 84.991 8.19 85.495 ;
     RECT  22.716 85.387 22.734 85.495 ;
     RECT  27.36 85.153 27.378 85.523 ;
     RECT  18.324 84.721 19.35 85.531 ;
     RECT  18.324 85.531 19.386 85.649 ;
     RECT  30.996 84.811 35.478 85.661 ;
     RECT  10.8 85.621 10.818 85.693 ;
     RECT  0.108 85.117 5.886 85.729 ;
     RECT  6.696 85.495 8.91 85.729 ;
     RECT  18.615 85.649 19.386 85.729 ;
     RECT  18.615 85.729 20.07 85.765 ;
     RECT  0.108 85.729 8.91 85.793 ;
     RECT  10.764 85.693 10.818 85.793 ;
     RECT  14.976 85.765 14.994 85.801 ;
     RECT  26.244 85.423 26.262 85.801 ;
     RECT  10.8 85.793 10.818 85.829 ;
     RECT  21.132 85.729 21.15 85.829 ;
     RECT  26.244 85.801 26.334 85.829 ;
     RECT  0.108 85.793 8.37 85.853 ;
     RECT  35.28 85.661 35.478 85.853 ;
     RECT  26.316 85.829 26.334 85.891 ;
     RECT  0.576 85.853 8.37 85.919 ;
     RECT  7.815 85.919 8.37 85.955 ;
     RECT  18.615 85.765 20.394 85.955 ;
     RECT  0.576 85.919 7.038 85.991 ;
     RECT  14.832 85.801 14.994 85.991 ;
     RECT  30.996 85.661 34.29 85.991 ;
     RECT  0.576 85.991 6.03 85.997 ;
     RECT  14.832 85.991 14.922 86.027 ;
     RECT  19.944 85.955 20.394 86.027 ;
     RECT  26.316 85.891 26.874 86.027 ;
     RECT  7.815 85.955 8.226 86.045 ;
     RECT  20.376 86.027 20.394 86.063 ;
     RECT  22.716 85.495 22.806 86.063 ;
     RECT  26.316 86.027 26.334 86.063 ;
     RECT  29.415 85.109 29.697 86.071 ;
     RECT  30.996 85.991 31.338 86.071 ;
     RECT  0.576 85.997 4.014 86.099 ;
     RECT  5.04 85.997 6.03 86.099 ;
     RECT  29.415 86.071 31.338 86.099 ;
     RECT  0.576 86.099 3.942 86.147 ;
     RECT  7.815 86.045 8.097 86.147 ;
     RECT  13.215 4.451 13.497 86.147 ;
     RECT  18.615 85.955 18.897 86.147 ;
     RECT  24.015 2.413 24.297 86.147 ;
     RECT  3.348 86.147 3.942 86.189 ;
     RECT  6.804 85.991 7.038 86.189 ;
     RECT  29.415 86.099 31.302 86.189 ;
     RECT  3.348 86.189 3.726 86.225 ;
     RECT  5.04 86.099 5.886 86.225 ;
     RECT  32.112 85.991 34.29 86.225 ;
     RECT  20.448 86.071 20.466 86.261 ;
     RECT  22.788 86.063 22.806 86.261 ;
     RECT  7.02 86.189 7.038 86.333 ;
     RECT  3.348 86.225 3.618 86.369 ;
     RECT  7.815 86.147 7.974 86.369 ;
     RECT  14.832 86.027 14.85 86.369 ;
     RECT  32.112 86.225 32.13 86.369 ;
     RECT  32.904 86.225 34.29 86.369 ;
     RECT  7.815 86.369 7.905 86.417 ;
     RECT  13.215 86.147 13.305 86.417 ;
     RECT  18.615 86.147 18.705 86.417 ;
     RECT  24.015 86.147 24.105 86.417 ;
     RECT  29.415 86.189 29.505 86.417 ;
     RECT  0.576 86.147 2.574 86.573 ;
     RECT  33.12 86.369 34.29 86.573 ;
     RECT  33.12 86.573 34.074 86.639 ;
     RECT  2.304 86.573 2.574 86.765 ;
     RECT  35.28 85.853 35.37 86.765 ;
     RECT  0.576 86.573 1.242 87.005 ;
     RECT  33.876 86.639 34.074 87.005 ;
     RECT  2.304 86.765 2.394 87.197 ;
     RECT  33.12 86.639 33.138 87.197 ;
     RECT  1.224 87.005 1.242 87.437 ;
     RECT  35.28 86.765 35.298 87.437 ;
     RECT  3.348 86.369 3.366 87.629 ;
     RECT  33.984 87.005 34.074 87.629 ;
     RECT  2.376 87.197 2.394 87.917 ;
     RECT  34.056 87.629 34.074 87.917 ;
    LAYER M4 ;
     RECT  1.997 1.728 2.069 1.752 ;
     RECT  2.069 1.728 2.081 1.8 ;
     RECT  2.081 1.776 2.153 1.8 ;
     RECT  0.06 4.224 2.329 87.912 ;
     RECT  2.329 3.408 2.405 87.912 ;
     RECT  2.197 2.148 2.408 2.28 ;
     RECT  2.405 3.408 2.408 87.624 ;
     RECT  2.408 2.148 2.512 87.624 ;
     RECT  2.512 2.256 2.585 87.624 ;
     RECT  2.585 2.256 2.704 86.142 ;
     RECT  2.704 12.48 2.765 12.504 ;
     RECT  2.704 41.664 2.765 41.688 ;
     RECT  2.704 43.92 2.765 43.944 ;
     RECT  2.704 48.432 2.765 48.456 ;
     RECT  2.704 63.792 2.765 65.256 ;
     RECT  2.704 69.312 2.765 69.336 ;
     RECT  2.704 72.24 2.765 73.368 ;
     RECT  2.704 9.84 2.801 10.632 ;
     RECT  2.704 28.512 2.801 29.496 ;
     RECT  2.704 30.816 2.801 31.944 ;
     RECT  2.704 50.112 2.801 52.584 ;
     RECT  2.765 63.84 2.801 65.256 ;
     RECT  2.704 67.104 2.801 67.944 ;
     RECT  2.704 77.904 2.801 78.072 ;
     RECT  2.704 15.504 2.837 16.296 ;
     RECT  2.704 18.48 2.837 18.504 ;
     RECT  2.704 22.512 2.837 22.536 ;
     RECT  2.704 24.144 2.837 24.936 ;
     RECT  2.704 34.176 2.837 34.68 ;
     RECT  2.704 54.672 2.837 55.704 ;
     RECT  2.704 82.704 2.837 82.728 ;
     RECT  2.801 10.608 2.873 10.632 ;
     RECT  2.837 15.792 2.873 16.296 ;
     RECT  2.704 27.168 2.873 27.192 ;
     RECT  2.704 33.024 2.873 33.048 ;
     RECT  2.704 38.832 2.873 40.344 ;
     RECT  2.704 59.76 2.873 62.28 ;
     RECT  2.801 67.104 2.873 67.128 ;
     RECT  2.704 80.256 2.873 80.28 ;
     RECT  2.704 81.36 2.873 81.384 ;
     RECT  2.873 16.272 2.909 16.296 ;
     RECT  2.837 24.672 2.909 24.936 ;
     RECT  2.704 36.912 2.909 37.416 ;
     RECT  2.704 45.264 2.909 45.288 ;
     RECT  2.704 5.856 2.981 7.176 ;
     RECT  2.704 26.064 2.981 26.088 ;
     RECT  2.837 34.176 2.981 34.2 ;
     RECT  2.837 54.672 2.981 55.272 ;
     RECT  2.873 59.808 2.981 62.28 ;
     RECT  2.801 63.84 2.981 64.344 ;
     RECT  2.981 6.048 3.089 7.176 ;
     RECT  3.089 6.816 3.125 7.176 ;
     RECT  2.909 24.912 3.125 24.936 ;
     RECT  2.909 37.392 3.125 37.416 ;
     RECT  2.981 54.672 3.125 54.696 ;
     RECT  2.765 72.24 3.125 73.032 ;
     RECT  2.704 74.592 3.125 74.616 ;
     RECT  2.704 79.2 3.197 79.224 ;
     RECT  2.704 4.512 3.233 4.536 ;
     RECT  3.125 6.816 3.233 6.84 ;
     RECT  2.704 75.744 3.233 76.344 ;
     RECT  2.873 38.832 3.305 39.624 ;
     RECT  3.233 75.744 3.341 75.768 ;
     RECT  2.585 87.6 3.377 87.624 ;
     RECT  2.801 50.112 3.413 51.672 ;
     RECT  2.704 3.408 3.697 3.432 ;
     RECT  2.704 86.064 3.697 86.088 ;
     RECT  3.697 3.408 3.737 3.96 ;
     RECT  3.697 85.968 3.737 86.088 ;
     RECT  3.125 73.008 3.769 73.032 ;
     RECT  3.305 38.832 3.877 39.288 ;
     RECT  2.981 63.84 4.021 63.864 ;
     RECT  2.981 59.808 4.093 61.608 ;
     RECT  3.949 67.248 4.129 67.272 ;
     RECT  3.697 35.424 4.268 35.448 ;
     RECT  3.949 46.752 4.273 47.304 ;
     RECT  4.021 8.4 4.309 8.424 ;
     RECT  2.801 29.472 4.309 29.496 ;
     RECT  2.801 30.816 4.309 30.984 ;
     RECT  4.268 34.512 4.309 35.928 ;
     RECT  3.877 44.448 4.309 44.472 ;
     RECT  4.273 45.84 4.309 47.304 ;
     RECT  4.165 52.8 4.309 52.824 ;
     RECT  4.268 54.288 4.309 54.312 ;
     RECT  4.129 66.624 4.309 67.272 ;
     RECT  4.309 70.128 4.345 70.152 ;
     RECT  4.309 8.4 4.355 9.24 ;
     RECT  4.309 33.6 4.355 35.928 ;
     RECT  4.309 52.8 4.355 54.312 ;
     RECT  4.268 76.896 4.355 76.92 ;
     RECT  4.268 81.264 4.355 82.104 ;
     RECT  3.737 3.936 4.357 3.96 ;
     RECT  4.309 6.816 4.393 6.84 ;
     RECT  4.357 3.936 4.403 4.68 ;
     RECT  4.093 59.376 4.417 61.608 ;
     RECT  4.403 4.656 4.444 4.68 ;
     RECT  4.355 9.216 4.453 9.24 ;
     RECT  3.769 26.832 4.453 26.856 ;
     RECT  4.309 29.472 4.453 30.984 ;
     RECT  4.021 63.504 4.453 63.864 ;
     RECT  4.381 11.28 4.481 11.304 ;
     RECT  4.453 9.216 4.493 9.672 ;
     RECT  4.508 12.528 4.517 12.552 ;
     RECT  4.517 14.208 4.525 14.232 ;
     RECT  4.501 16.512 4.525 16.536 ;
     RECT  4.165 37.056 4.525 37.08 ;
     RECT  3.877 38.64 4.525 39.288 ;
     RECT  4.309 44.448 4.525 47.304 ;
     RECT  4.417 59.088 4.525 61.608 ;
     RECT  4.453 62.64 4.525 63.864 ;
     RECT  4.309 66.624 4.525 67.8 ;
     RECT  3.769 75.264 4.525 75.288 ;
     RECT  4.309 79.2 4.529 79.224 ;
     RECT  4.493 9.648 4.547 9.672 ;
     RECT  4.345 17.664 4.547 17.688 ;
     RECT  4.525 59.088 4.547 63.864 ;
     RECT  4.345 70.128 4.561 70.728 ;
     RECT  4.417 71.808 4.561 71.832 ;
     RECT  4.481 10.848 4.565 11.304 ;
     RECT  4.525 15.936 4.588 16.536 ;
     RECT  4.547 59.376 4.588 63.864 ;
     RECT  4.517 12.528 4.595 13.128 ;
     RECT  4.595 12.864 4.601 13.128 ;
     RECT  4.453 29.472 4.601 31.944 ;
     RECT  2.801 78.048 4.601 78.072 ;
     RECT  4.525 14.208 4.609 14.856 ;
     RECT  4.525 66.624 4.633 68.424 ;
     RECT  4.525 43.344 4.637 47.304 ;
     RECT  4.237 48.672 4.652 48.696 ;
     RECT  4.652 48.432 4.669 48.696 ;
     RECT  4.633 66.144 4.673 68.424 ;
     RECT  4.669 47.856 4.693 48.696 ;
     RECT  4.588 15.936 4.709 15.96 ;
     RECT  4.355 33.6 4.709 33.96 ;
     RECT  4.588 59.376 4.709 60.456 ;
     RECT  4.673 67.2 4.709 68.424 ;
     RECT  4.693 47.856 4.739 49.032 ;
     RECT  4.588 61.536 4.781 63.864 ;
     RECT  4.561 70.128 4.844 71.832 ;
     RECT  3.769 73.008 4.844 73.176 ;
     RECT  4.609 14.208 4.853 14.232 ;
     RECT  4.844 70.128 4.876 73.176 ;
     RECT  4.525 37.056 4.885 39.288 ;
     RECT  4.637 43.824 4.889 46.776 ;
     RECT  4.889 43.824 4.925 45 ;
     RECT  4.739 49.008 4.925 49.032 ;
     RECT  4.876 71.808 4.925 73.176 ;
     RECT  4.601 29.472 4.931 31.368 ;
     RECT  4.925 72.288 5.027 73.176 ;
     RECT  3.737 85.968 5.077 85.992 ;
     RECT  5.027 72.288 5.123 73.128 ;
     RECT  5.036 84.192 5.123 84.216 ;
     RECT  4.453 26.832 5.137 27.336 ;
     RECT  5.137 26.784 5.177 27.336 ;
     RECT  4.781 63.216 5.177 63.864 ;
     RECT  4.355 81.456 5.213 82.104 ;
     RECT  5.077 85.584 5.213 85.992 ;
     RECT  4.931 29.472 5.249 30.984 ;
     RECT  4.876 70.128 5.285 70.728 ;
     RECT  5.249 29.472 5.353 30.264 ;
     RECT  3.949 23.952 5.357 23.976 ;
     RECT  5.123 72.288 5.357 73.032 ;
     RECT  3.413 50.112 5.393 51.528 ;
     RECT  5.357 72.912 5.501 73.032 ;
     RECT  4.237 21.648 5.533 21.672 ;
     RECT  4.885 37.056 5.569 39.384 ;
     RECT  4.355 35.424 5.573 35.928 ;
     RECT  4.739 47.856 5.573 47.88 ;
     RECT  5.213 85.584 5.573 85.944 ;
     RECT  5.393 50.112 5.609 50.76 ;
     RECT  4.355 52.8 5.609 53.592 ;
     RECT  4.709 59.376 5.609 60.408 ;
     RECT  4.525 74.448 5.609 76.2 ;
     RECT  5.501 72.912 5.645 72.984 ;
     RECT  5.609 74.448 5.645 75.816 ;
     RECT  5.569 37.056 5.699 39.912 ;
     RECT  4.565 11.28 5.708 11.304 ;
     RECT  4.889 46.752 5.717 46.776 ;
     RECT  5.281 41.04 5.749 41.064 ;
     RECT  4.417 42.192 5.749 42.216 ;
     RECT  5.533 21.648 5.789 22.2 ;
     RECT  4.885 25.296 5.789 25.32 ;
     RECT  4.709 33.936 5.789 33.96 ;
     RECT  4.489 58.08 5.789 58.104 ;
     RECT  4.673 66.144 5.789 66.168 ;
     RECT  4.709 67.2 5.789 67.8 ;
     RECT  4.561 80.352 5.789 80.376 ;
     RECT  5.708 11.28 5.795 11.448 ;
     RECT  5.699 37.056 5.825 37.08 ;
     RECT  4.925 43.824 5.825 44.472 ;
     RECT  5.425 18 5.852 18.024 ;
     RECT  5.605 15.648 5.893 15.672 ;
     RECT  5.852 17.088 5.893 18.024 ;
     RECT  4.601 12.864 5.897 12.888 ;
     RECT  5.893 15.072 5.939 15.672 ;
     RECT  5.893 17.088 5.939 18.456 ;
     RECT  4.633 19.488 5.939 19.512 ;
     RECT  5.699 39.888 5.941 39.912 ;
     RECT  5.749 41.04 5.941 42.216 ;
     RECT  5.749 20.544 5.948 20.568 ;
     RECT  4.741 7.872 5.965 7.896 ;
     RECT  5.941 39.888 5.987 42.216 ;
     RECT  5.711 10.032 5.989 10.056 ;
     RECT  5.795 11.28 5.989 11.304 ;
     RECT  5.965 7.872 6.005 8.184 ;
     RECT  5.939 15.072 6.005 15.096 ;
     RECT  5.948 20.544 6.005 20.808 ;
     RECT  5.353 28.944 6.005 30.264 ;
     RECT  5.987 39.888 6.005 40.44 ;
     RECT  5.177 63.84 6.005 63.864 ;
     RECT  5.645 75.264 6.005 75.816 ;
     RECT  6.005 40.416 6.028 40.44 ;
     RECT  5.989 10.032 6.035 11.304 ;
     RECT  6.005 20.784 6.035 20.808 ;
     RECT  6.005 28.944 6.035 29.4 ;
     RECT  5.177 26.784 6.145 27.096 ;
     RECT  6.035 10.032 6.229 10.872 ;
     RECT  5.609 59.712 6.253 60.408 ;
     RECT  4.781 61.536 6.253 62.184 ;
     RECT  5.987 42.192 6.257 42.216 ;
     RECT  6.229 9.168 6.275 10.872 ;
     RECT  6.275 9.168 6.316 9.192 ;
     RECT  6.253 59.712 6.437 62.184 ;
     RECT  5.285 70.272 6.613 70.728 ;
     RECT  5.609 50.112 6.649 50.664 ;
     RECT  5.573 35.712 6.668 35.928 ;
     RECT  6.001 36.96 6.668 37.032 ;
     RECT  6.649 50.064 6.721 50.664 ;
     RECT  5.213 81.456 6.721 81.48 ;
     RECT  6.668 35.712 6.755 37.032 ;
     RECT  6.613 70.272 6.755 71.304 ;
     RECT  5.749 52.704 6.757 52.728 ;
     RECT  5.749 53.904 6.757 53.928 ;
     RECT  5.789 67.2 6.757 67.224 ;
     RECT  6.755 70.272 6.757 70.392 ;
     RECT  6.721 80.928 6.761 81.48 ;
     RECT  5.573 85.92 6.793 85.944 ;
     RECT  6.275 10.848 6.803 10.872 ;
     RECT  6.005 75.264 6.805 75.288 ;
     RECT  6.577 55.584 6.829 55.608 ;
     RECT  6.437 60.96 6.829 62.184 ;
     RECT  6.145 63.648 6.829 63.672 ;
     RECT  5.821 77.424 6.829 77.448 ;
     RECT  6.757 52.704 6.853 53.928 ;
     RECT  6.437 59.712 6.853 59.736 ;
     RECT  6.755 36.96 6.86 37.032 ;
     RECT  5.699 38.112 6.86 38.76 ;
     RECT  5.749 23.568 6.908 23.592 ;
     RECT  5.825 44.448 6.937 44.472 ;
     RECT  6.685 45.552 6.937 45.576 ;
     RECT  6.908 23.568 6.949 23.736 ;
     RECT  6.145 26.64 6.997 27.096 ;
     RECT  6.793 85.92 7.004 86.04 ;
     RECT  6.937 44.448 7.045 45.576 ;
     RECT  6.829 60.96 7.045 63.672 ;
     RECT  6.829 64.752 7.045 64.776 ;
     RECT  5.645 72.912 7.045 72.936 ;
     RECT  4.489 83.184 7.045 83.208 ;
     RECT  7.045 60.96 7.052 64.776 ;
     RECT  7.045 72.912 7.093 73.08 ;
     RECT  6.853 47.28 7.117 47.304 ;
     RECT  6.853 52.704 7.141 54.36 ;
     RECT  6.829 55.584 7.141 56.472 ;
     RECT  6.721 50.064 7.148 51.528 ;
     RECT  7.141 52.704 7.148 56.472 ;
     RECT  5.749 5.472 7.261 5.496 ;
     RECT  6.755 35.712 7.261 35.784 ;
     RECT  6.577 78.624 7.285 78.648 ;
     RECT  7.148 50.064 7.297 56.472 ;
     RECT  7.093 58.128 7.297 58.152 ;
     RECT  7.093 72.912 7.429 73.752 ;
     RECT  7.297 50.064 7.441 58.152 ;
     RECT  6.853 59.232 7.441 59.736 ;
     RECT  2.704 2.256 7.808 2.28 ;
     RECT  6.757 4.128 7.808 4.152 ;
     RECT  7.261 5.472 7.808 5.592 ;
     RECT  6.005 8.16 7.808 8.184 ;
     RECT  6.973 14.208 7.808 14.232 ;
     RECT  7.045 16.08 7.808 16.104 ;
     RECT  5.939 18.432 7.808 18.456 ;
     RECT  6.949 23.568 7.808 24.648 ;
     RECT  6.997 26.64 7.808 27.912 ;
     RECT  6.035 28.944 7.808 29.208 ;
     RECT  6.829 32.736 7.808 32.76 ;
     RECT  7.261 34.752 7.808 35.784 ;
     RECT  6.86 36.96 7.808 38.76 ;
     RECT  7.669 39.744 7.808 39.768 ;
     RECT  7.549 41.472 7.808 41.496 ;
     RECT  7.045 44.448 7.808 45.768 ;
     RECT  7.117 46.752 7.808 47.304 ;
     RECT  6.361 48.816 7.808 48.84 ;
     RECT  7.441 50.064 7.808 59.736 ;
     RECT  7.052 60.96 7.808 65.544 ;
     RECT  6.757 67.2 7.808 67.272 ;
     RECT  6.757 70.08 7.808 70.392 ;
     RECT  7.429 72.336 7.808 73.752 ;
     RECT  6.805 74.832 7.808 75.288 ;
     RECT  6.829 76.464 7.808 77.448 ;
     RECT  7.285 78.624 7.808 79.464 ;
     RECT  6.761 80.928 7.808 80.952 ;
     RECT  7.045 82.608 7.808 83.208 ;
     RECT  7.004 85.488 7.808 86.04 ;
     RECT  7.808 2.148 7.912 86.412 ;
     RECT  7.912 2.256 8.104 86.142 ;
     RECT  8.104 5.568 8.165 5.592 ;
     RECT  8.104 26.256 8.165 27.912 ;
     RECT  8.104 55.248 8.165 55.272 ;
     RECT  8.104 61.92 8.165 61.944 ;
     RECT  8.104 63.552 8.165 63.816 ;
     RECT  8.104 73.056 8.165 74.712 ;
     RECT  8.104 85.488 8.165 86.04 ;
     RECT  8.165 85.92 8.237 86.04 ;
     RECT  8.104 17.616 8.243 18.408 ;
     RECT  8.165 26.256 8.243 27.336 ;
     RECT  8.104 34.752 8.243 35.784 ;
     RECT  8.104 37.44 8.243 38.232 ;
     RECT  8.104 24.624 8.273 25.08 ;
     RECT  8.104 29.616 8.281 29.64 ;
     RECT  8.273 25.056 8.284 25.08 ;
     RECT  8.243 37.44 8.284 37.464 ;
     RECT  8.243 35.76 8.309 35.784 ;
     RECT  8.165 63.552 8.309 63.576 ;
     RECT  8.104 76.464 8.309 76.488 ;
     RECT  8.165 73.776 8.38 74.712 ;
     RECT  8.38 74.688 8.381 74.712 ;
     RECT  8.237 85.92 8.381 85.944 ;
     RECT  8.104 57.312 8.387 59.304 ;
     RECT  8.104 8.16 8.417 8.184 ;
     RECT  8.104 32.736 8.417 32.76 ;
     RECT  8.387 57.6 8.417 58.152 ;
     RECT  8.387 59.28 8.425 59.304 ;
     RECT  8.243 27.072 8.741 27.336 ;
     RECT  8.741 27.312 8.771 27.336 ;
     RECT  8.417 57.6 8.819 57.624 ;
     RECT  8.104 42.912 8.915 43.32 ;
     RECT  8.915 43.008 10.897 43.032 ;
     RECT  10.897 43.008 11.725 43.176 ;
     RECT  11.725 42.768 12.035 43.176 ;
     RECT  8.104 2.256 12.077 2.28 ;
     RECT  12.035 43.152 12.089 43.176 ;
     RECT  12.077 1.728 12.161 2.28 ;
     RECT  12.161 2.256 13.208 2.28 ;
     RECT  8.104 4.128 13.208 4.152 ;
     RECT  13.208 2.148 13.312 86.412 ;
     RECT  13.312 2.256 13.504 86.142 ;
     RECT  13.504 4.128 14.492 4.2 ;
     RECT  14.492 3.696 14.533 4.2 ;
     RECT  14.533 3.696 14.579 4.536 ;
     RECT  14.579 4.128 14.821 4.536 ;
     RECT  14.821 4.128 15.937 4.68 ;
     RECT  13.504 2.256 16.009 2.28 ;
     RECT  16.009 1.728 16.481 2.28 ;
     RECT  15.937 4.128 16.657 4.968 ;
     RECT  16.481 2.256 17.276 2.28 ;
     RECT  16.657 3.408 17.276 4.968 ;
     RECT  17.276 2.256 17.489 4.968 ;
     RECT  17.489 2.256 17.561 4.872 ;
     RECT  17.561 2.256 18.608 4.2 ;
     RECT  18.608 2.148 18.712 86.412 ;
     RECT  18.712 2.256 18.904 86.142 ;
     RECT  18.904 3.936 19.379 4.152 ;
     RECT  18.904 83.184 20.045 83.208 ;
     RECT  18.904 2.256 24.008 2.28 ;
     RECT  19.379 4.128 24.008 4.152 ;
     RECT  24.008 2.148 24.112 86.412 ;
     RECT  24.112 2.418 24.304 86.142 ;
     RECT  24.304 4.128 29.408 4.152 ;
     RECT  29.408 2.148 29.512 86.412 ;
     RECT  29.512 2.418 29.704 86.142 ;
     RECT  29.704 4.128 31.853 4.152 ;
     RECT  32.065 38.688 32.321 38.712 ;
     RECT  31.741 84.096 32.605 84.12 ;
     RECT  32.605 83.76 32.965 84.12 ;
     RECT  33.001 0.096 33.155 0.12 ;
     RECT  32.533 1.728 33.301 1.752 ;
     RECT  33.301 1.728 33.473 2.184 ;
     RECT  33.469 0.576 33.553 0.6 ;
     RECT  32.965 83.136 33.613 84.12 ;
     RECT  33.473 2.16 33.725 2.184 ;
     RECT  33.649 86.064 33.865 86.088 ;
     RECT  33.109 87.168 33.865 87.192 ;
     RECT  33.865 86.064 33.973 87.192 ;
     RECT  33.973 86.064 34.045 87.624 ;
     RECT  33.613 83.136 34.153 84.504 ;
     RECT  34.153 38.928 34.189 38.952 ;
     RECT  34.153 53.616 34.189 53.64 ;
     RECT  33.793 66.816 34.189 66.84 ;
     RECT  34.189 6.144 34.729 6.168 ;
     RECT  34.189 14.832 34.729 14.856 ;
     RECT  33.901 19.44 34.729 19.464 ;
     RECT  34.189 36.432 34.729 36.456 ;
     RECT  33.613 37.824 34.729 37.848 ;
     RECT  34.189 38.928 34.729 39.384 ;
     RECT  33.865 50.496 34.729 50.52 ;
     RECT  34.189 51.648 34.729 51.672 ;
     RECT  34.189 52.992 34.729 53.64 ;
     RECT  34.189 55.488 34.729 55.944 ;
     RECT  34.189 58.608 34.729 58.632 ;
     RECT  34.189 71.376 34.729 72.264 ;
     RECT  34.189 74.304 34.729 74.52 ;
     RECT  33.901 75.648 34.729 75.672 ;
     RECT  33.973 77.664 34.729 77.688 ;
     RECT  33.757 79.728 34.729 79.752 ;
     RECT  34.153 83.136 34.729 84.696 ;
     RECT  34.729 6.144 34.765 7.176 ;
     RECT  34.729 14.496 34.765 14.856 ;
     RECT  34.729 18.48 34.765 19.464 ;
     RECT  34.729 21.12 34.765 21.144 ;
     RECT  34.729 24.816 34.765 24.84 ;
     RECT  33.973 30.336 34.765 30.36 ;
     RECT  33.685 34.416 34.765 34.44 ;
     RECT  34.729 36.432 34.765 39.384 ;
     RECT  34.189 43.44 34.765 44.184 ;
     RECT  34.189 48 34.765 48.024 ;
     RECT  34.729 50.496 34.765 51.672 ;
     RECT  34.729 52.992 34.765 53.928 ;
     RECT  34.729 55.488 34.765 56.424 ;
     RECT  34.189 62.496 34.765 62.52 ;
     RECT  34.189 64.32 34.765 64.344 ;
     RECT  34.189 65.664 34.765 66.84 ;
     RECT  34.729 71.376 34.765 73.176 ;
     RECT  34.729 74.304 34.765 75.672 ;
     RECT  34.729 76.992 34.765 77.688 ;
     RECT  34.729 78.816 34.765 79.752 ;
     RECT  34.729 82.896 34.765 84.696 ;
     RECT  34.045 86.064 34.765 87.912 ;
     RECT  34.765 57.552 34.909 57.576 ;
     RECT  34.729 58.608 34.909 59.592 ;
     RECT  34.765 69.072 35.233 75.672 ;
     RECT  34.765 76.992 35.233 81.096 ;
     RECT  34.765 11.472 35.269 11.496 ;
     RECT  34.765 17.472 35.269 17.496 ;
     RECT  34.765 23.808 35.269 23.832 ;
     RECT  34.765 24.816 35.269 25.512 ;
     RECT  34.189 26.496 35.269 26.52 ;
     RECT  34.765 28.176 35.269 33.048 ;
     RECT  34.765 34.416 35.269 34.68 ;
     RECT  34.765 41.664 35.269 41.688 ;
     RECT  33.865 46.176 35.269 46.2 ;
     RECT  34.765 47.76 35.269 48.024 ;
     RECT  34.765 50.256 35.269 51.672 ;
     RECT  34.765 52.992 35.269 56.424 ;
     RECT  34.729 61.152 35.269 61.176 ;
     RECT  34.765 62.496 35.269 67.752 ;
     RECT  35.233 69.072 35.269 81.096 ;
     RECT  34.765 82.176 35.269 87.912 ;
     RECT  33.973 4.176 35.305 4.2 ;
     RECT  34.765 5.472 35.305 7.176 ;
     RECT  34.189 8.496 35.305 8.52 ;
     RECT  35.269 11.136 35.305 12.168 ;
     RECT  34.765 13.824 35.305 15.528 ;
     RECT  35.269 16.512 35.305 17.496 ;
     RECT  34.765 18.48 35.305 21.144 ;
     RECT  34.189 22.464 35.305 22.488 ;
     RECT  35.269 23.472 35.305 23.832 ;
     RECT  35.269 24.816 35.305 26.52 ;
     RECT  35.269 28.176 35.305 34.68 ;
     RECT  34.765 35.76 35.305 39.624 ;
     RECT  35.269 40.752 35.305 41.688 ;
     RECT  34.765 43.008 35.305 44.856 ;
     RECT  35.269 45.984 35.305 48.936 ;
     RECT  35.269 50.256 35.305 56.424 ;
     RECT  34.909 57.552 35.305 59.592 ;
     RECT  35.269 61.152 35.305 67.752 ;
     RECT  35.269 69.072 35.305 87.912 ;
     RECT  35.305 4.176 36.252 87.912 ;
    LAYER M5 ;
     RECT  33.024 0.016 33.528 0.611 ;
     RECT  2.016 0.016 2.232 1.763 ;
     RECT  12 0.016 12.12 1.763 ;
     RECT  16.032 0.016 16.344 1.763 ;
     RECT  33.024 0.611 33.432 1.763 ;
     RECT  2.112 1.763 2.232 1.811 ;
     RECT  16.128 1.763 16.344 1.811 ;
     RECT  2.208 1.811 2.232 2.137 ;
     RECT  2.208 2.137 2.52 2.151 ;
     RECT  7.8 2.137 7.92 2.151 ;
     RECT  13.2 2.137 13.32 2.151 ;
     RECT  18.6 2.137 18.72 2.151 ;
     RECT  24 2.137 24.12 2.151 ;
     RECT  29.4 2.137 29.52 2.151 ;
     RECT  33.312 1.763 33.336 2.195 ;
     RECT  16.32 1.811 16.344 2.243 ;
     RECT  2.208 2.151 2.712 2.291 ;
     RECT  18.6 2.151 18.912 3.925 ;
     RECT  17.328 3.061 17.352 3.971 ;
     RECT  18.6 3.925 19.368 4.163 ;
     RECT  14.544 3.685 14.568 4.547 ;
     RECT  4.368 3.925 4.392 4.691 ;
     RECT  6.768 4.117 6.792 8.149 ;
     RECT  4.32 6.805 4.344 9.251 ;
     RECT  6.24 8.149 6.792 10.021 ;
     RECT  4.512 9.637 4.536 10.883 ;
     RECT  5.76 10.021 6.792 10.883 ;
     RECT  5.76 10.883 6.024 11.459 ;
     RECT  4.56 12.517 4.584 13.139 ;
     RECT  7.8 2.151 8.112 14.197 ;
     RECT  4.56 14.197 4.584 14.867 ;
     RECT  6 11.459 6.024 15.061 ;
     RECT  7.056 14.197 8.112 16.115 ;
     RECT  7.8 16.115 8.112 17.605 ;
     RECT  4.512 16.501 4.536 17.699 ;
     RECT  7.8 17.605 8.232 18.419 ;
     RECT  5.904 15.061 6.024 20.579 ;
     RECT  6 20.579 6.024 23.701 ;
     RECT  7.8 18.419 8.112 23.701 ;
     RECT  6 23.701 8.112 24.659 ;
     RECT  7.8 24.659 8.112 25.045 ;
     RECT  7.8 25.045 8.232 26.291 ;
     RECT  7.8 26.291 8.112 27.301 ;
     RECT  7.8 27.301 8.76 27.877 ;
     RECT  7.008 27.877 8.76 29.219 ;
     RECT  6 24.659 6.024 29.365 ;
     RECT  5.472 29.365 6.024 29.411 ;
     RECT  5.472 29.411 5.496 30.229 ;
     RECT  4.896 30.229 5.496 31.379 ;
     RECT  4.32 34.501 4.344 35.939 ;
     RECT  6.72 35.701 6.744 36.997 ;
     RECT  7.8 29.219 8.76 36.997 ;
     RECT  6.72 36.997 8.76 37.043 ;
     RECT  5.472 31.379 5.496 37.621 ;
     RECT  5.472 37.621 5.688 37.667 ;
     RECT  6.912 37.043 8.76 38.675 ;
     RECT  5.664 37.667 5.688 39.395 ;
     RECT  7.68 38.675 8.76 41.507 ;
     RECT  5.952 40.405 5.976 41.939 ;
     RECT  12 1.763 12.024 42.803 ;
     RECT  7.8 41.507 8.76 42.901 ;
     RECT  7.8 42.901 8.904 43.331 ;
     RECT  7.8 43.331 8.808 44.965 ;
     RECT  6.96 44.965 8.808 45.587 ;
     RECT  7.152 45.587 8.808 47.269 ;
     RECT  4.704 48.421 4.728 49.043 ;
     RECT  6.864 47.269 8.808 50.099 ;
     RECT  4.56 50.965 4.584 51.539 ;
     RECT  7.2 50.099 8.808 52.693 ;
     RECT  4.32 53.557 4.344 54.323 ;
     RECT  6.864 52.693 8.808 54.371 ;
     RECT  7.152 54.371 8.808 55.573 ;
     RECT  6.864 55.573 8.808 56.483 ;
     RECT  7.2 56.483 8.808 57.635 ;
     RECT  7.2 57.635 8.376 58.117 ;
     RECT  7.104 58.117 8.376 59.221 ;
     RECT  6.864 59.221 8.376 59.315 ;
     RECT  6.864 59.315 8.112 62.723 ;
     RECT  4.512 59.077 4.536 63.539 ;
     RECT  7.104 62.723 8.112 70.069 ;
     RECT  6.816 70.069 8.112 70.357 ;
     RECT  6.72 70.357 8.112 71.315 ;
     RECT  4.8 70.933 4.824 71.843 ;
     RECT  4.896 72.277 4.92 72.949 ;
     RECT  4.896 72.949 5.112 73.139 ;
     RECT  4.992 73.139 5.016 73.187 ;
     RECT  7.104 71.315 8.112 73.765 ;
     RECT  7.104 73.765 8.328 74.723 ;
     RECT  7.104 74.723 8.112 74.821 ;
     RECT  6.816 74.821 8.112 75.299 ;
     RECT  4.32 76.885 4.344 78.083 ;
     RECT  7.104 75.299 8.112 80.963 ;
     RECT  4.32 79.189 4.344 82.115 ;
     RECT  7.8 80.963 8.112 82.597 ;
     RECT  7.056 82.597 8.112 85.523 ;
     RECT  5.088 84.181 5.112 85.619 ;
     RECT  2.4 2.291 2.712 86.409 ;
     RECT  7.8 85.523 8.112 86.409 ;
     RECT  13.2 2.151 13.512 86.409 ;
     RECT  18.6 4.163 18.912 86.409 ;
     RECT  24 2.151 24.312 86.409 ;
     RECT  29.4 2.151 29.712 86.409 ;
     RECT  2.4 86.409 2.52 86.423 ;
     RECT  7.8 86.409 7.92 86.423 ;
     RECT  13.2 86.409 13.32 86.423 ;
     RECT  18.6 86.409 18.72 86.423 ;
     RECT  24 86.409 24.12 86.423 ;
     RECT  29.4 86.409 29.52 86.423 ;
     RECT  12.024 1.763 12.12 2.137 ;
     RECT  12.024 2.137 13.2 42.803 ;
     RECT  17.352 3.061 18.6 3.971 ;
     RECT  13.512 3.685 14.544 4.547 ;
     RECT  6.792 4.117 7.8 10.883 ;
     RECT  4.536 10.021 5.76 10.883 ;
     RECT  5.76 11.459 6 12.517 ;
     RECT  4.584 12.517 6 13.139 ;
     RECT  4.56 13.139 6 14.197 ;
     RECT  4.584 14.197 6 14.867 ;
     RECT  6.024 14.197 7.056 16.115 ;
     RECT  5.904 14.867 6 15.061 ;
     RECT  4.536 16.501 5.904 17.699 ;
     RECT  8.112 26.291 8.232 27.301 ;
     RECT  6.024 27.877 7.008 29.219 ;
     RECT  4.344 34.501 5.472 35.939 ;
     RECT  5.496 35.701 6.72 37.043 ;
     RECT  6.744 35.701 7.8 36.997 ;
     RECT  5.496 37.043 6.912 37.621 ;
     RECT  5.688 37.621 6.912 38.675 ;
     RECT  6.864 54.371 7.152 55.573 ;
     RECT  4.32 78.083 4.344 79.189 ;
  END
END ot_engc_ctl_x
END LIBRARY
